VERSION 5.7 ;
  NOWIREEXTENSIONATPIN ON ;
  DIVIDERCHAR "/" ;
  BUSBITCHARS "[]" ;
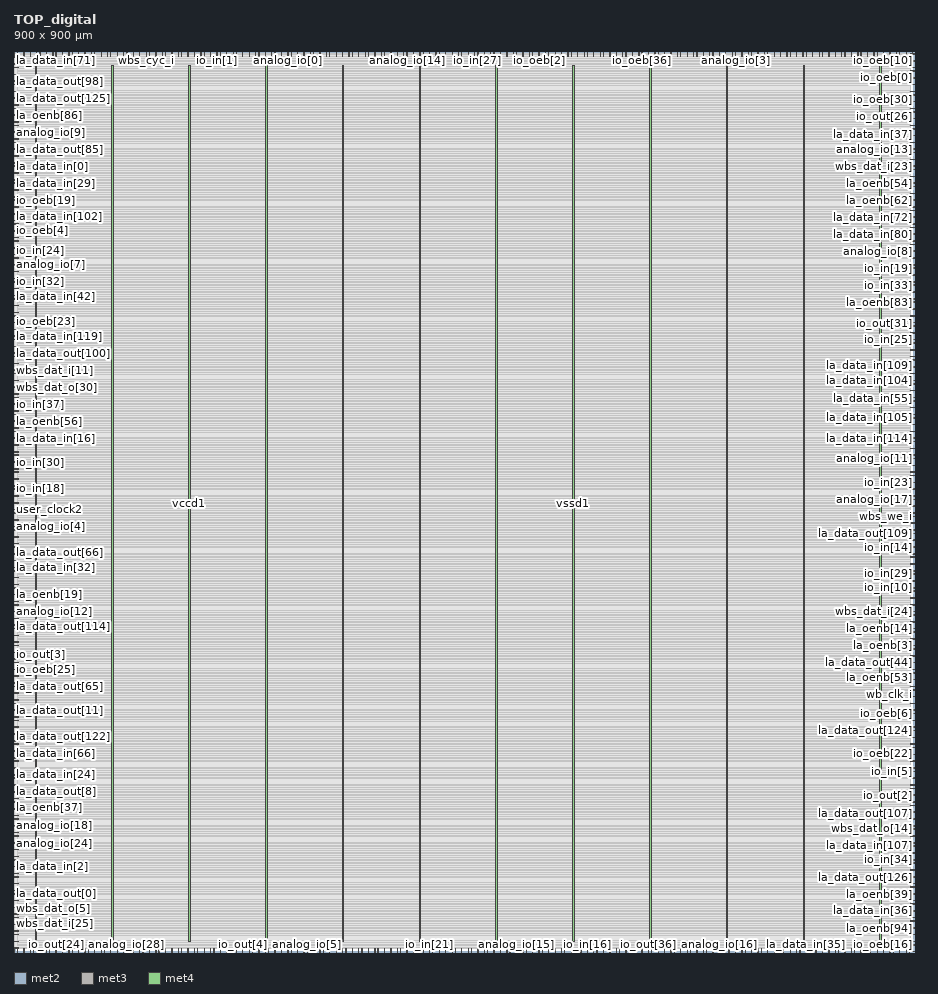
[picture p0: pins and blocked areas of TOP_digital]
MACRO TOP_digital
  CLASS BLOCK ;
  FOREIGN TOP_digital ;
  ORIGIN 0.000 0.000 ;
  SIZE 900.000 BY 900.000 ;
  PIN analog_io[0]
    DIRECTION INOUT ;
    USE SIGNAL ;
    PORT
      LAYER met2 ;
        RECT 273.790 896.000 274.070 900.000 ;
    END
  END analog_io[0]
  PIN analog_io[10]
    DIRECTION INOUT ;
    USE SIGNAL ;
    PORT
      LAYER met2 ;
        RECT 77.370 896.000 77.650 900.000 ;
    END
  END analog_io[10]
  PIN analog_io[11]
    DIRECTION INOUT ;
    USE SIGNAL ;
    PORT
      LAYER met3 ;
        RECT 896.000 493.040 900.000 493.640 ;
    END
  END analog_io[11]
  PIN analog_io[12]
    DIRECTION INOUT ;
    USE SIGNAL ;
    PORT
      LAYER met3 ;
        RECT 0.000 340.040 4.000 340.640 ;
    END
  END analog_io[12]
  PIN analog_io[13]
    DIRECTION INOUT ;
    USE SIGNAL ;
    PORT
      LAYER met3 ;
        RECT 896.000 802.440 900.000 803.040 ;
    END
  END analog_io[13]
  PIN analog_io[14]
    DIRECTION INOUT ;
    USE SIGNAL ;
    PORT
      LAYER met2 ;
        RECT 392.930 896.000 393.210 900.000 ;
    END
  END analog_io[14]
  PIN analog_io[15]
    DIRECTION INOUT ;
    USE SIGNAL ;
    PORT
      LAYER met2 ;
        RECT 502.410 0.000 502.690 4.000 ;
    END
  END analog_io[15]
  PIN analog_io[16]
    DIRECTION INOUT ;
    USE SIGNAL ;
    PORT
      LAYER met2 ;
        RECT 705.270 0.000 705.550 4.000 ;
    END
  END analog_io[16]
  PIN analog_io[17]
    DIRECTION INOUT ;
    USE SIGNAL ;
    PORT
      LAYER met3 ;
        RECT 896.000 452.240 900.000 452.840 ;
    END
  END analog_io[17]
  PIN analog_io[18]
    DIRECTION INOUT ;
    USE SIGNAL ;
    PORT
      LAYER met3 ;
        RECT 0.000 125.840 4.000 126.440 ;
    END
  END analog_io[18]
  PIN analog_io[19]
    DIRECTION INOUT ;
    USE SIGNAL ;
    PORT
      LAYER met3 ;
        RECT 0.000 537.240 4.000 537.840 ;
    END
  END analog_io[19]
  PIN analog_io[1]
    DIRECTION INOUT ;
    USE SIGNAL ;
    PORT
      LAYER met2 ;
        RECT 25.850 0.000 26.130 4.000 ;
    END
  END analog_io[1]
  PIN analog_io[20]
    DIRECTION INOUT ;
    USE SIGNAL ;
    PORT
      LAYER met2 ;
        RECT 512.070 0.000 512.350 4.000 ;
    END
  END analog_io[20]
  PIN analog_io[21]
    DIRECTION INOUT ;
    USE SIGNAL ;
    PORT
      LAYER met3 ;
        RECT 0.000 887.440 4.000 888.040 ;
    END
  END analog_io[21]
  PIN analog_io[22]
    DIRECTION INOUT ;
    USE SIGNAL ;
    PORT
      LAYER met3 ;
        RECT 896.000 799.040 900.000 799.640 ;
    END
  END analog_io[22]
  PIN analog_io[23]
    DIRECTION INOUT ;
    USE SIGNAL ;
    PORT
      LAYER met2 ;
        RECT 219.050 0.000 219.330 4.000 ;
    END
  END analog_io[23]
  PIN analog_io[24]
    DIRECTION INOUT ;
    USE SIGNAL ;
    PORT
      LAYER met3 ;
        RECT 0.000 115.640 4.000 116.240 ;
    END
  END analog_io[24]
  PIN analog_io[25]
    DIRECTION INOUT ;
    USE SIGNAL ;
    PORT
      LAYER met3 ;
        RECT 896.000 652.840 900.000 653.440 ;
    END
  END analog_io[25]
  PIN analog_io[26]
    DIRECTION INOUT ;
    USE SIGNAL ;
    PORT
      LAYER met2 ;
        RECT 714.930 0.000 715.210 4.000 ;
    END
  END analog_io[26]
  PIN analog_io[27]
    DIRECTION INOUT ;
    USE SIGNAL ;
    PORT
      LAYER met2 ;
        RECT 322.090 896.000 322.370 900.000 ;
    END
  END analog_io[27]
  PIN analog_io[28]
    DIRECTION INOUT ;
    USE SIGNAL ;
    PORT
      LAYER met2 ;
        RECT 112.790 0.000 113.070 4.000 ;
    END
  END analog_io[28]
  PIN analog_io[2]
    DIRECTION INOUT ;
    USE SIGNAL ;
    PORT
      LAYER met2 ;
        RECT 260.910 896.000 261.190 900.000 ;
    END
  END analog_io[2]
  PIN analog_io[3]
    DIRECTION INOUT ;
    USE SIGNAL ;
    PORT
      LAYER met2 ;
        RECT 721.370 896.000 721.650 900.000 ;
    END
  END analog_io[3]
  PIN analog_io[4]
    DIRECTION INOUT ;
    USE SIGNAL ;
    PORT
      LAYER met3 ;
        RECT 0.000 425.040 4.000 425.640 ;
    END
  END analog_io[4]
  PIN analog_io[5]
    DIRECTION INOUT ;
    USE SIGNAL ;
    PORT
      LAYER met2 ;
        RECT 293.110 0.000 293.390 4.000 ;
    END
  END analog_io[5]
  PIN analog_io[6]
    DIRECTION INOUT ;
    USE SIGNAL ;
    PORT
      LAYER met2 ;
        RECT 296.330 896.000 296.610 900.000 ;
    END
  END analog_io[6]
  PIN analog_io[7]
    DIRECTION INOUT ;
    USE SIGNAL ;
    PORT
      LAYER met3 ;
        RECT 0.000 686.840 4.000 687.440 ;
    END
  END analog_io[7]
  PIN analog_io[8]
    DIRECTION INOUT ;
    USE SIGNAL ;
    PORT
      LAYER met3 ;
        RECT 896.000 700.440 900.000 701.040 ;
    END
  END analog_io[8]
  PIN analog_io[9]
    DIRECTION INOUT ;
    USE SIGNAL ;
    PORT
      LAYER met3 ;
        RECT 0.000 819.440 4.000 820.040 ;
    END
  END analog_io[9]
  PIN analog_trigger_in
    DIRECTION INOUT ;
    USE SIGNAL ;
    PORT
      LAYER met3 ;
        RECT 0.000 78.240 4.000 78.840 ;
    END
  END analog_trigger_in
  PIN analog_trigger_out
    DIRECTION INOUT ;
    USE SIGNAL ;
    PORT
      LAYER met3 ;
        RECT 0.000 95.240 4.000 95.840 ;
    END
  END analog_trigger_out
  PIN io_in[0]
    DIRECTION INPUT ;
    USE SIGNAL ;
    PORT
      LAYER met2 ;
        RECT 151.430 896.000 151.710 900.000 ;
    END
  END io_in[0]
  PIN io_in[10]
    DIRECTION INPUT ;
    USE SIGNAL ;
    PORT
      LAYER met3 ;
        RECT 896.000 363.840 900.000 364.440 ;
    END
  END io_in[10]
  PIN io_in[11]
    DIRECTION INPUT ;
    USE SIGNAL ;
    PORT
      LAYER met2 ;
        RECT 673.070 896.000 673.350 900.000 ;
    END
  END io_in[11]
  PIN io_in[12]
    DIRECTION INPUT ;
    USE SIGNAL ;
    PORT
      LAYER met2 ;
        RECT 376.830 0.000 377.110 4.000 ;
    END
  END io_in[12]
  PIN io_in[13]
    DIRECTION INPUT ;
    USE SIGNAL ;
    PORT
      LAYER met3 ;
        RECT 896.000 455.640 900.000 456.240 ;
    END
  END io_in[13]
  PIN io_in[14]
    DIRECTION INPUT ;
    USE SIGNAL ;
    PORT
      LAYER met3 ;
        RECT 896.000 411.440 900.000 412.040 ;
    END
  END io_in[14]
  PIN io_in[15]
    DIRECTION INPUT ;
    USE SIGNAL ;
    PORT
      LAYER met3 ;
        RECT 896.000 10.240 900.000 10.840 ;
    END
  END io_in[15]
  PIN io_in[16]
    DIRECTION INPUT ;
    USE SIGNAL ;
    PORT
      LAYER met2 ;
        RECT 573.250 0.000 573.530 4.000 ;
    END
  END io_in[16]
  PIN io_in[17]
    DIRECTION INPUT ;
    USE SIGNAL ;
    PORT
      LAYER met2 ;
        RECT 109.570 896.000 109.850 900.000 ;
    END
  END io_in[17]
  PIN io_in[18]
    DIRECTION INPUT ;
    USE SIGNAL ;
    PORT
      LAYER met3 ;
        RECT 0.000 455.640 4.000 456.240 ;
    END
  END io_in[18]
  PIN io_in[19]
    DIRECTION INPUT ;
    USE SIGNAL ;
    PORT
      LAYER met3 ;
        RECT 896.000 683.440 900.000 684.040 ;
    END
  END io_in[19]
  PIN io_in[1]
    DIRECTION INPUT ;
    USE SIGNAL ;
    PORT
      LAYER met2 ;
        RECT 202.950 896.000 203.230 900.000 ;
    END
  END io_in[1]
  PIN io_in[20]
    DIRECTION INPUT ;
    USE SIGNAL ;
    PORT
      LAYER met3 ;
        RECT 896.000 421.640 900.000 422.240 ;
    END
  END io_in[20]
  PIN io_in[21]
    DIRECTION INPUT ;
    USE SIGNAL ;
    PORT
      LAYER met2 ;
        RECT 415.470 0.000 415.750 4.000 ;
    END
  END io_in[21]
  PIN io_in[22]
    DIRECTION INPUT ;
    USE SIGNAL ;
    PORT
      LAYER met2 ;
        RECT 48.390 896.000 48.670 900.000 ;
    END
  END io_in[22]
  PIN io_in[23]
    DIRECTION INPUT ;
    USE SIGNAL ;
    PORT
      LAYER met3 ;
        RECT 896.000 469.240 900.000 469.840 ;
    END
  END io_in[23]
  PIN io_in[24]
    DIRECTION INPUT ;
    USE SIGNAL ;
    PORT
      LAYER met3 ;
        RECT 0.000 693.640 4.000 694.240 ;
    END
  END io_in[24]
  PIN io_in[25]
    DIRECTION INPUT ;
    USE SIGNAL ;
    PORT
      LAYER met3 ;
        RECT 896.000 612.040 900.000 612.640 ;
    END
  END io_in[25]
  PIN io_in[26]
    DIRECTION INPUT ;
    USE SIGNAL ;
    PORT
      LAYER met3 ;
        RECT 896.000 445.440 900.000 446.040 ;
    END
  END io_in[26]
  PIN io_in[27]
    DIRECTION INPUT ;
    USE SIGNAL ;
    PORT
      LAYER met2 ;
        RECT 463.770 896.000 464.050 900.000 ;
    END
  END io_in[27]
  PIN io_in[28]
    DIRECTION INPUT ;
    USE SIGNAL ;
    PORT
      LAYER met2 ;
        RECT 135.330 896.000 135.610 900.000 ;
    END
  END io_in[28]
  PIN io_in[29]
    DIRECTION INPUT ;
    USE SIGNAL ;
    PORT
      LAYER met3 ;
        RECT 896.000 370.640 900.000 371.240 ;
    END
  END io_in[29]
  PIN io_in[2]
    DIRECTION INPUT ;
    USE SIGNAL ;
    PORT
      LAYER met2 ;
        RECT 80.590 896.000 80.870 900.000 ;
    END
  END io_in[2]
  PIN io_in[30]
    DIRECTION INPUT ;
    USE SIGNAL ;
    PORT
      LAYER met3 ;
        RECT 0.000 489.640 4.000 490.240 ;
    END
  END io_in[30]
  PIN io_in[31]
    DIRECTION INPUT ;
    USE SIGNAL ;
    PORT
      LAYER met2 ;
        RECT 376.830 896.000 377.110 900.000 ;
    END
  END io_in[31]
  PIN io_in[32]
    DIRECTION INPUT ;
    USE SIGNAL ;
    PORT
      LAYER met3 ;
        RECT 0.000 669.840 4.000 670.440 ;
    END
  END io_in[32]
  PIN io_in[33]
    DIRECTION INPUT ;
    USE SIGNAL ;
    PORT
      LAYER met3 ;
        RECT 896.000 666.440 900.000 667.040 ;
    END
  END io_in[33]
  PIN io_in[34]
    DIRECTION INPUT ;
    USE SIGNAL ;
    PORT
      LAYER met3 ;
        RECT 896.000 91.840 900.000 92.440 ;
    END
  END io_in[34]
  PIN io_in[35]
    DIRECTION INPUT ;
    USE SIGNAL ;
    PORT
      LAYER met2 ;
        RECT 80.590 0.000 80.870 4.000 ;
    END
  END io_in[35]
  PIN io_in[36]
    DIRECTION INPUT ;
    USE SIGNAL ;
    PORT
      LAYER met3 ;
        RECT 0.000 309.440 4.000 310.040 ;
    END
  END io_in[36]
  PIN io_in[37]
    DIRECTION INPUT ;
    USE SIGNAL ;
    PORT
      LAYER met3 ;
        RECT 0.000 547.440 4.000 548.040 ;
    END
  END io_in[37]
  PIN io_in[3]
    DIRECTION INPUT ;
    USE SIGNAL ;
    PORT
      LAYER met2 ;
        RECT 566.810 0.000 567.090 4.000 ;
    END
  END io_in[3]
  PIN io_in[4]
    DIRECTION INPUT ;
    USE SIGNAL ;
    PORT
      LAYER met3 ;
        RECT 0.000 275.440 4.000 276.040 ;
    END
  END io_in[4]
  PIN io_in[5]
    DIRECTION INPUT ;
    USE SIGNAL ;
    PORT
      LAYER met3 ;
        RECT 896.000 180.240 900.000 180.840 ;
    END
  END io_in[5]
  PIN io_in[6]
    DIRECTION INPUT ;
    USE SIGNAL ;
    PORT
      LAYER met2 ;
        RECT 347.850 0.000 348.130 4.000 ;
    END
  END io_in[6]
  PIN io_in[7]
    DIRECTION INPUT ;
    USE SIGNAL ;
    PORT
      LAYER met3 ;
        RECT 0.000 166.640 4.000 167.240 ;
    END
  END io_in[7]
  PIN io_in[8]
    DIRECTION INPUT ;
    USE SIGNAL ;
    PORT
      LAYER met3 ;
        RECT 896.000 394.440 900.000 395.040 ;
    END
  END io_in[8]
  PIN io_in[9]
    DIRECTION INPUT ;
    USE SIGNAL ;
    PORT
      LAYER met3 ;
        RECT 896.000 122.440 900.000 123.040 ;
    END
  END io_in[9]
  PIN io_oeb[0]
    DIRECTION OUTPUT TRISTATE ;
    USE SIGNAL ;
    ANTENNADIFFAREA 0.445500 ;
    PORT
      LAYER met3 ;
        RECT 896.000 873.840 900.000 874.440 ;
    END
  END io_oeb[0]
  PIN io_oeb[10]
    DIRECTION OUTPUT TRISTATE ;
    USE SIGNAL ;
    ANTENNADIFFAREA 0.445500 ;
    PORT
      LAYER met2 ;
        RECT 882.370 896.000 882.650 900.000 ;
    END
  END io_oeb[10]
  PIN io_oeb[11]
    DIRECTION OUTPUT TRISTATE ;
    USE SIGNAL ;
    ANTENNADIFFAREA 0.445500 ;
    PORT
      LAYER met3 ;
        RECT 0.000 595.040 4.000 595.640 ;
    END
  END io_oeb[11]
  PIN io_oeb[12]
    DIRECTION OUTPUT TRISTATE ;
    USE SIGNAL ;
    ANTENNADIFFAREA 0.445500 ;
    PORT
      LAYER met3 ;
        RECT 896.000 897.640 900.000 898.240 ;
    END
  END io_oeb[12]
  PIN io_oeb[13]
    DIRECTION OUTPUT TRISTATE ;
    USE SIGNAL ;
    ANTENNADIFFAREA 0.445500 ;
    PORT
      LAYER met2 ;
        RECT 344.630 896.000 344.910 900.000 ;
    END
  END io_oeb[13]
  PIN io_oeb[14]
    DIRECTION OUTPUT TRISTATE ;
    USE SIGNAL ;
    ANTENNADIFFAREA 0.445500 ;
    PORT
      LAYER met2 ;
        RECT 595.790 0.000 596.070 4.000 ;
    END
  END io_oeb[14]
  PIN io_oeb[15]
    DIRECTION OUTPUT TRISTATE ;
    USE SIGNAL ;
    ANTENNADIFFAREA 0.445500 ;
    PORT
      LAYER met2 ;
        RECT 251.250 896.000 251.530 900.000 ;
    END
  END io_oeb[15]
  PIN io_oeb[16]
    DIRECTION OUTPUT TRISTATE ;
    USE SIGNAL ;
    ANTENNADIFFAREA 0.445500 ;
    PORT
      LAYER met2 ;
        RECT 885.590 0.000 885.870 4.000 ;
    END
  END io_oeb[16]
  PIN io_oeb[17]
    DIRECTION OUTPUT TRISTATE ;
    USE SIGNAL ;
    ANTENNADIFFAREA 0.445500 ;
    PORT
      LAYER met3 ;
        RECT 896.000 758.240 900.000 758.840 ;
    END
  END io_oeb[17]
  PIN io_oeb[18]
    DIRECTION OUTPUT TRISTATE ;
    USE SIGNAL ;
    ANTENNADIFFAREA 0.445500 ;
    PORT
      LAYER met2 ;
        RECT 846.950 0.000 847.230 4.000 ;
    END
  END io_oeb[18]
  PIN io_oeb[19]
    DIRECTION OUTPUT TRISTATE ;
    USE SIGNAL ;
    ANTENNADIFFAREA 0.445500 ;
    PORT
      LAYER met3 ;
        RECT 0.000 751.440 4.000 752.040 ;
    END
  END io_oeb[19]
  PIN io_oeb[1]
    DIRECTION OUTPUT TRISTATE ;
    USE SIGNAL ;
    ANTENNADIFFAREA 0.445500 ;
    PORT
      LAYER met2 ;
        RECT 460.550 896.000 460.830 900.000 ;
    END
  END io_oeb[1]
  PIN io_oeb[20]
    DIRECTION OUTPUT TRISTATE ;
    USE SIGNAL ;
    ANTENNADIFFAREA 0.445500 ;
    PORT
      LAYER met3 ;
        RECT 896.000 132.640 900.000 133.240 ;
    END
  END io_oeb[20]
  PIN io_oeb[21]
    DIRECTION OUTPUT TRISTATE ;
    USE SIGNAL ;
    ANTENNADIFFAREA 0.445500 ;
    PORT
      LAYER met3 ;
        RECT 896.000 744.640 900.000 745.240 ;
    END
  END io_oeb[21]
  PIN io_oeb[22]
    DIRECTION OUTPUT TRISTATE ;
    USE SIGNAL ;
    ANTENNADIFFAREA 0.445500 ;
    PORT
      LAYER met3 ;
        RECT 896.000 190.440 900.000 191.040 ;
    END
  END io_oeb[22]
  PIN io_oeb[23]
    DIRECTION OUTPUT TRISTATE ;
    USE SIGNAL ;
    ANTENNADIFFAREA 0.445500 ;
    PORT
      LAYER met3 ;
        RECT 0.000 622.240 4.000 622.840 ;
    END
  END io_oeb[23]
  PIN io_oeb[24]
    DIRECTION OUTPUT TRISTATE ;
    USE SIGNAL ;
    ANTENNADIFFAREA 0.445500 ;
    PORT
      LAYER met3 ;
        RECT 0.000 34.040 4.000 34.640 ;
    END
  END io_oeb[24]
  PIN io_oeb[25]
    DIRECTION OUTPUT TRISTATE ;
    USE SIGNAL ;
    ANTENNADIFFAREA 0.445500 ;
    PORT
      LAYER met3 ;
        RECT 0.000 282.240 4.000 282.840 ;
    END
  END io_oeb[25]
  PIN io_oeb[26]
    DIRECTION OUTPUT TRISTATE ;
    USE SIGNAL ;
    ANTENNADIFFAREA 0.445500 ;
    PORT
      LAYER met2 ;
        RECT 772.890 896.000 773.170 900.000 ;
    END
  END io_oeb[26]
  PIN io_oeb[27]
    DIRECTION OUTPUT TRISTATE ;
    USE SIGNAL ;
    ANTENNADIFFAREA 0.445500 ;
    PORT
      LAYER met2 ;
        RECT 676.290 0.000 676.570 4.000 ;
    END
  END io_oeb[27]
  PIN io_oeb[28]
    DIRECTION OUTPUT TRISTATE ;
    USE SIGNAL ;
    ANTENNADIFFAREA 0.445500 ;
    PORT
      LAYER met2 ;
        RECT 305.990 0.000 306.270 4.000 ;
    END
  END io_oeb[28]
  PIN io_oeb[29]
    DIRECTION OUTPUT TRISTATE ;
    USE SIGNAL ;
    ANTENNADIFFAREA 0.445500 ;
    PORT
      LAYER met3 ;
        RECT 0.000 183.640 4.000 184.240 ;
    END
  END io_oeb[29]
  PIN io_oeb[2]
    DIRECTION OUTPUT TRISTATE ;
    USE SIGNAL ;
    ANTENNADIFFAREA 0.445500 ;
    PORT
      LAYER met2 ;
        RECT 524.950 896.000 525.230 900.000 ;
    END
  END io_oeb[2]
  PIN io_oeb[30]
    DIRECTION OUTPUT TRISTATE ;
    USE SIGNAL ;
    ANTENNADIFFAREA 0.445500 ;
    PORT
      LAYER met3 ;
        RECT 896.000 860.240 900.000 860.840 ;
    END
  END io_oeb[30]
  PIN io_oeb[31]
    DIRECTION OUTPUT TRISTATE ;
    USE SIGNAL ;
    ANTENNADIFFAREA 0.445500 ;
    PORT
      LAYER met2 ;
        RECT 827.630 896.000 827.910 900.000 ;
    END
  END io_oeb[31]
  PIN io_oeb[32]
    DIRECTION OUTPUT TRISTATE ;
    USE SIGNAL ;
    ANTENNADIFFAREA 0.445500 ;
    PORT
      LAYER met3 ;
        RECT 0.000 326.440 4.000 327.040 ;
    END
  END io_oeb[32]
  PIN io_oeb[33]
    DIRECTION OUTPUT TRISTATE ;
    USE SIGNAL ;
    ANTENNADIFFAREA 0.445500 ;
    PORT
      LAYER met3 ;
        RECT 0.000 754.840 4.000 755.440 ;
    END
  END io_oeb[33]
  PIN io_oeb[34]
    DIRECTION OUTPUT TRISTATE ;
    USE SIGNAL ;
    ANTENNADIFFAREA 0.445500 ;
    PORT
      LAYER met2 ;
        RECT 438.010 896.000 438.290 900.000 ;
    END
  END io_oeb[34]
  PIN io_oeb[35]
    DIRECTION OUTPUT TRISTATE ;
    USE SIGNAL ;
    ANTENNADIFFAREA 0.445500 ;
    PORT
      LAYER met3 ;
        RECT 0.000 829.640 4.000 830.240 ;
    END
  END io_oeb[35]
  PIN io_oeb[36]
    DIRECTION OUTPUT TRISTATE ;
    USE SIGNAL ;
    ANTENNADIFFAREA 0.445500 ;
    PORT
      LAYER met2 ;
        RECT 627.990 896.000 628.270 900.000 ;
    END
  END io_oeb[36]
  PIN io_oeb[37]
    DIRECTION OUTPUT TRISTATE ;
    USE SIGNAL ;
    ANTENNADIFFAREA 0.445500 ;
    PORT
      LAYER met2 ;
        RECT 3.310 896.000 3.590 900.000 ;
    END
  END io_oeb[37]
  PIN io_oeb[3]
    DIRECTION OUTPUT TRISTATE ;
    USE SIGNAL ;
    ANTENNADIFFAREA 0.445500 ;
    PORT
      LAYER met3 ;
        RECT 0.000 523.640 4.000 524.240 ;
    END
  END io_oeb[3]
  PIN io_oeb[4]
    DIRECTION OUTPUT TRISTATE ;
    USE SIGNAL ;
    ANTENNADIFFAREA 0.445500 ;
    PORT
      LAYER met3 ;
        RECT 0.000 720.840 4.000 721.440 ;
    END
  END io_oeb[4]
  PIN io_oeb[5]
    DIRECTION OUTPUT TRISTATE ;
    USE SIGNAL ;
    ANTENNADIFFAREA 0.445500 ;
    PORT
      LAYER met2 ;
        RECT 58.050 896.000 58.330 900.000 ;
    END
  END io_oeb[5]
  PIN io_oeb[6]
    DIRECTION OUTPUT TRISTATE ;
    USE SIGNAL ;
    ANTENNADIFFAREA 0.445500 ;
    PORT
      LAYER met3 ;
        RECT 896.000 238.040 900.000 238.640 ;
    END
  END io_oeb[6]
  PIN io_oeb[7]
    DIRECTION OUTPUT TRISTATE ;
    USE SIGNAL ;
    ANTENNADIFFAREA 0.445500 ;
    PORT
      LAYER met3 ;
        RECT 896.000 241.440 900.000 242.040 ;
    END
  END io_oeb[7]
  PIN io_oeb[8]
    DIRECTION OUTPUT TRISTATE ;
    USE SIGNAL ;
    ANTENNADIFFAREA 0.445500 ;
    PORT
      LAYER met2 ;
        RECT 895.250 0.000 895.530 4.000 ;
    END
  END io_oeb[8]
  PIN io_oeb[9]
    DIRECTION OUTPUT TRISTATE ;
    USE SIGNAL ;
    ANTENNADIFFAREA 0.445500 ;
    PORT
      LAYER met2 ;
        RECT 415.470 896.000 415.750 900.000 ;
    END
  END io_oeb[9]
  PIN io_out[0]
    DIRECTION OUTPUT TRISTATE ;
    USE SIGNAL ;
    ANTENNADIFFAREA 0.445500 ;
    PORT
      LAYER met2 ;
        RECT 74.150 0.000 74.430 4.000 ;
    END
  END io_out[0]
  PIN io_out[10]
    DIRECTION OUTPUT TRISTATE ;
    USE SIGNAL ;
    ANTENNADIFFAREA 0.445500 ;
    PORT
      LAYER met3 ;
        RECT 0.000 37.440 4.000 38.040 ;
    END
  END io_out[10]
  PIN io_out[11]
    DIRECTION OUTPUT TRISTATE ;
    USE SIGNAL ;
    ANTENNADIFFAREA 0.445500 ;
    PORT
      LAYER met2 ;
        RECT 180.410 896.000 180.690 900.000 ;
    END
  END io_out[11]
  PIN io_out[12]
    DIRECTION OUTPUT TRISTATE ;
    USE SIGNAL ;
    ANTENNADIFFAREA 0.445500 ;
    PORT
      LAYER met2 ;
        RECT 447.670 0.000 447.950 4.000 ;
    END
  END io_out[12]
  PIN io_out[13]
    DIRECTION OUTPUT TRISTATE ;
    USE SIGNAL ;
    ANTENNADIFFAREA 0.445500 ;
    PORT
      LAYER met3 ;
        RECT 0.000 448.840 4.000 449.440 ;
    END
  END io_out[13]
  PIN io_out[14]
    DIRECTION OUTPUT TRISTATE ;
    USE SIGNAL ;
    ANTENNADIFFAREA 0.445500 ;
    PORT
      LAYER met2 ;
        RECT 164.310 896.000 164.590 900.000 ;
    END
  END io_out[14]
  PIN io_out[15]
    DIRECTION OUTPUT TRISTATE ;
    USE SIGNAL ;
    ANTENNADIFFAREA 0.445500 ;
    PORT
      LAYER met3 ;
        RECT 0.000 697.040 4.000 697.640 ;
    END
  END io_out[15]
  PIN io_out[16]
    DIRECTION OUTPUT TRISTATE ;
    USE SIGNAL ;
    ANTENNADIFFAREA 0.445500 ;
    PORT
      LAYER met2 ;
        RECT 322.090 0.000 322.370 4.000 ;
    END
  END io_out[16]
  PIN io_out[17]
    DIRECTION OUTPUT TRISTATE ;
    USE SIGNAL ;
    ANTENNADIFFAREA 0.445500 ;
    PORT
      LAYER met2 ;
        RECT 157.870 0.000 158.150 4.000 ;
    END
  END io_out[17]
  PIN io_out[18]
    DIRECTION OUTPUT TRISTATE ;
    USE SIGNAL ;
    ANTENNADIFFAREA 0.445500 ;
    PORT
      LAYER met3 ;
        RECT 0.000 578.040 4.000 578.640 ;
    END
  END io_out[18]
  PIN io_out[19]
    DIRECTION OUTPUT TRISTATE ;
    USE SIGNAL ;
    ANTENNADIFFAREA 0.445500 ;
    PORT
      LAYER met2 ;
        RECT 96.690 896.000 96.970 900.000 ;
    END
  END io_out[19]
  PIN io_out[1]
    DIRECTION OUTPUT TRISTATE ;
    USE SIGNAL ;
    ANTENNADIFFAREA 0.445500 ;
    PORT
      LAYER met2 ;
        RECT 682.730 0.000 683.010 4.000 ;
    END
  END io_out[1]
  PIN io_out[20]
    DIRECTION OUTPUT TRISTATE ;
    USE SIGNAL ;
    ANTENNADIFFAREA 0.445500 ;
    PORT
      LAYER met2 ;
        RECT 846.950 896.000 847.230 900.000 ;
    END
  END io_out[20]
  PIN io_out[21]
    DIRECTION OUTPUT TRISTATE ;
    USE SIGNAL ;
    ANTENNADIFFAREA 0.445500 ;
    PORT
      LAYER met2 ;
        RECT 402.590 0.000 402.870 4.000 ;
    END
  END io_out[21]
  PIN io_out[22]
    DIRECTION OUTPUT TRISTATE ;
    USE SIGNAL ;
    ANTENNADIFFAREA 0.445500 ;
    PORT
      LAYER met2 ;
        RECT 135.330 0.000 135.610 4.000 ;
    END
  END io_out[22]
  PIN io_out[23]
    DIRECTION OUTPUT TRISTATE ;
    USE SIGNAL ;
    ANTENNADIFFAREA 0.445500 ;
    PORT
      LAYER met2 ;
        RECT 776.110 896.000 776.390 900.000 ;
    END
  END io_out[23]
  PIN io_out[24]
    DIRECTION OUTPUT TRISTATE ;
    USE SIGNAL ;
    ANTENNADIFFAREA 0.445500 ;
    PORT
      LAYER met2 ;
        RECT 41.950 0.000 42.230 4.000 ;
    END
  END io_out[24]
  PIN io_out[25]
    DIRECTION OUTPUT TRISTATE ;
    USE SIGNAL ;
    ANTENNADIFFAREA 0.445500 ;
    PORT
      LAYER met3 ;
        RECT 896.000 166.640 900.000 167.240 ;
    END
  END io_out[25]
  PIN io_out[26]
    DIRECTION OUTPUT TRISTATE ;
    USE SIGNAL ;
    ANTENNADIFFAREA 0.445500 ;
    PORT
      LAYER met3 ;
        RECT 896.000 843.240 900.000 843.840 ;
    END
  END io_out[26]
  PIN io_out[27]
    DIRECTION OUTPUT TRISTATE ;
    USE SIGNAL ;
    ANTENNADIFFAREA 0.445500 ;
    PORT
      LAYER met2 ;
        RECT 492.750 896.000 493.030 900.000 ;
    END
  END io_out[27]
  PIN io_out[28]
    DIRECTION OUTPUT TRISTATE ;
    USE SIGNAL ;
    ANTENNADIFFAREA 0.445500 ;
    PORT
      LAYER met2 ;
        RECT 589.350 0.000 589.630 4.000 ;
    END
  END io_out[28]
  PIN io_out[29]
    DIRECTION OUTPUT TRISTATE ;
    USE SIGNAL ;
    ANTENNADIFFAREA 0.445500 ;
    PORT
      LAYER met2 ;
        RECT 875.930 896.000 876.210 900.000 ;
    END
  END io_out[29]
  PIN io_out[2]
    DIRECTION OUTPUT TRISTATE ;
    USE SIGNAL ;
    ANTENNADIFFAREA 0.445500 ;
    PORT
      LAYER met3 ;
        RECT 896.000 156.440 900.000 157.040 ;
    END
  END io_out[2]
  PIN io_out[30]
    DIRECTION OUTPUT TRISTATE ;
    USE SIGNAL ;
    ANTENNADIFFAREA 0.445500 ;
    PORT
      LAYER met2 ;
        RECT 392.930 0.000 393.210 4.000 ;
    END
  END io_out[30]
  PIN io_out[31]
    DIRECTION OUTPUT TRISTATE ;
    USE SIGNAL ;
    ANTENNADIFFAREA 0.445500 ;
    PORT
      LAYER met3 ;
        RECT 896.000 635.840 900.000 636.440 ;
    END
  END io_out[31]
  PIN io_out[32]
    DIRECTION OUTPUT TRISTATE ;
    USE SIGNAL ;
    ANTENNADIFFAREA 0.445500 ;
    PORT
      LAYER met2 ;
        RECT 119.230 0.000 119.510 4.000 ;
    END
  END io_out[32]
  PIN io_out[33]
    DIRECTION OUTPUT TRISTATE ;
    USE SIGNAL ;
    ANTENNADIFFAREA 0.445500 ;
    PORT
      LAYER met2 ;
        RECT 354.290 0.000 354.570 4.000 ;
    END
  END io_out[33]
  PIN io_out[34]
    DIRECTION OUTPUT TRISTATE ;
    USE SIGNAL ;
    ANTENNADIFFAREA 0.445500 ;
    PORT
      LAYER met2 ;
        RECT 863.050 0.000 863.330 4.000 ;
    END
  END io_out[34]
  PIN io_out[35]
    DIRECTION OUTPUT TRISTATE ;
    USE SIGNAL ;
    ANTENNADIFFAREA 0.445500 ;
    PORT
      LAYER met3 ;
        RECT 0.000 894.240 4.000 894.840 ;
    END
  END io_out[35]
  PIN io_out[36]
    DIRECTION OUTPUT TRISTATE ;
    USE SIGNAL ;
    ANTENNADIFFAREA 0.445500 ;
    PORT
      LAYER met2 ;
        RECT 634.430 0.000 634.710 4.000 ;
    END
  END io_out[36]
  PIN io_out[37]
    DIRECTION OUTPUT TRISTATE ;
    USE SIGNAL ;
    ANTENNADIFFAREA 0.445500 ;
    PORT
      LAYER met2 ;
        RECT 148.210 896.000 148.490 900.000 ;
    END
  END io_out[37]
  PIN io_out[3]
    DIRECTION OUTPUT TRISTATE ;
    USE SIGNAL ;
    ANTENNADIFFAREA 0.445500 ;
    PORT
      LAYER met3 ;
        RECT 0.000 289.040 4.000 289.640 ;
    END
  END io_out[3]
  PIN io_out[4]
    DIRECTION OUTPUT TRISTATE ;
    USE SIGNAL ;
    ANTENNADIFFAREA 0.445500 ;
    PORT
      LAYER met2 ;
        RECT 228.710 0.000 228.990 4.000 ;
    END
  END io_out[4]
  PIN io_out[5]
    DIRECTION OUTPUT TRISTATE ;
    USE SIGNAL ;
    ANTENNADIFFAREA 0.445500 ;
    PORT
      LAYER met2 ;
        RECT 222.270 0.000 222.550 4.000 ;
    END
  END io_out[5]
  PIN io_out[6]
    DIRECTION OUTPUT TRISTATE ;
    USE SIGNAL ;
    ANTENNADIFFAREA 0.445500 ;
    PORT
      LAYER met2 ;
        RECT 54.830 0.000 55.110 4.000 ;
    END
  END io_out[6]
  PIN io_out[7]
    DIRECTION OUTPUT TRISTATE ;
    USE SIGNAL ;
    ANTENNADIFFAREA 0.445500 ;
    PORT
      LAYER met3 ;
        RECT 0.000 588.240 4.000 588.840 ;
    END
  END io_out[7]
  PIN io_out[8]
    DIRECTION OUTPUT TRISTATE ;
    USE SIGNAL ;
    ANTENNADIFFAREA 0.445500 ;
    PORT
      LAYER met3 ;
        RECT 0.000 397.840 4.000 398.440 ;
    END
  END io_out[8]
  PIN io_out[9]
    DIRECTION OUTPUT TRISTATE ;
    USE SIGNAL ;
    ANTENNADIFFAREA 0.445500 ;
    PORT
      LAYER met2 ;
        RECT 760.010 0.000 760.290 4.000 ;
    END
  END io_out[9]
  PIN la_data_in[0]
    DIRECTION INPUT ;
    USE SIGNAL ;
    ANTENNAGATEAREA 0.742500 ;
    PORT
      LAYER met3 ;
        RECT 0.000 785.440 4.000 786.040 ;
    END
  END la_data_in[0]
  PIN la_data_in[100]
    DIRECTION INPUT ;
    USE SIGNAL ;
    PORT
      LAYER met2 ;
        RECT 766.450 896.000 766.730 900.000 ;
    END
  END la_data_in[100]
  PIN la_data_in[101]
    DIRECTION INPUT ;
    USE SIGNAL ;
    PORT
      LAYER met2 ;
        RECT 805.090 896.000 805.370 900.000 ;
    END
  END la_data_in[101]
  PIN la_data_in[102]
    DIRECTION INPUT ;
    USE SIGNAL ;
    PORT
      LAYER met3 ;
        RECT 0.000 727.640 4.000 728.240 ;
    END
  END la_data_in[102]
  PIN la_data_in[103]
    DIRECTION INPUT ;
    USE SIGNAL ;
    PORT
      LAYER met2 ;
        RECT 219.050 896.000 219.330 900.000 ;
    END
  END la_data_in[103]
  PIN la_data_in[104]
    DIRECTION INPUT ;
    USE SIGNAL ;
    PORT
      LAYER met3 ;
        RECT 896.000 571.240 900.000 571.840 ;
    END
  END la_data_in[104]
  PIN la_data_in[105]
    DIRECTION INPUT ;
    USE SIGNAL ;
    PORT
      LAYER met3 ;
        RECT 896.000 533.840 900.000 534.440 ;
    END
  END la_data_in[105]
  PIN la_data_in[106]
    DIRECTION INPUT ;
    USE SIGNAL ;
    PORT
      LAYER met2 ;
        RECT 808.310 896.000 808.590 900.000 ;
    END
  END la_data_in[106]
  PIN la_data_in[107]
    DIRECTION INPUT ;
    USE SIGNAL ;
    PORT
      LAYER met3 ;
        RECT 896.000 98.640 900.000 99.240 ;
    END
  END la_data_in[107]
  PIN la_data_in[108]
    DIRECTION INPUT ;
    USE SIGNAL ;
    PORT
      LAYER met3 ;
        RECT 896.000 816.040 900.000 816.640 ;
    END
  END la_data_in[108]
  PIN la_data_in[109]
    DIRECTION INPUT ;
    USE SIGNAL ;
    PORT
      LAYER met3 ;
        RECT 896.000 578.040 900.000 578.640 ;
    END
  END la_data_in[109]
  PIN la_data_in[10]
    DIRECTION INPUT ;
    USE SIGNAL ;
    PORT
      LAYER met3 ;
        RECT 896.000 479.440 900.000 480.040 ;
    END
  END la_data_in[10]
  PIN la_data_in[110]
    DIRECTION INPUT ;
    USE SIGNAL ;
    PORT
      LAYER met2 ;
        RECT 238.370 0.000 238.650 4.000 ;
    END
  END la_data_in[110]
  PIN la_data_in[111]
    DIRECTION INPUT ;
    USE SIGNAL ;
    PORT
      LAYER met2 ;
        RECT 875.930 0.000 876.210 4.000 ;
    END
  END la_data_in[111]
  PIN la_data_in[112]
    DIRECTION INPUT ;
    USE SIGNAL ;
    PORT
      LAYER met2 ;
        RECT 257.690 896.000 257.970 900.000 ;
    END
  END la_data_in[112]
  PIN la_data_in[113]
    DIRECTION INPUT ;
    USE SIGNAL ;
    PORT
      LAYER met3 ;
        RECT 896.000 782.040 900.000 782.640 ;
    END
  END la_data_in[113]
  PIN la_data_in[114]
    DIRECTION INPUT ;
    USE SIGNAL ;
    PORT
      LAYER met3 ;
        RECT 896.000 513.440 900.000 514.040 ;
    END
  END la_data_in[114]
  PIN la_data_in[115]
    DIRECTION INPUT ;
    USE SIGNAL ;
    PORT
      LAYER met2 ;
        RECT 360.730 896.000 361.010 900.000 ;
    END
  END la_data_in[115]
  PIN la_data_in[116]
    DIRECTION INPUT ;
    USE SIGNAL ;
    PORT
      LAYER met3 ;
        RECT 0.000 680.040 4.000 680.640 ;
    END
  END la_data_in[116]
  PIN la_data_in[117]
    DIRECTION INPUT ;
    USE SIGNAL ;
    PORT
      LAYER met3 ;
        RECT 896.000 595.040 900.000 595.640 ;
    END
  END la_data_in[117]
  PIN la_data_in[118]
    DIRECTION INPUT ;
    USE SIGNAL ;
    PORT
      LAYER met2 ;
        RECT 692.390 0.000 692.670 4.000 ;
    END
  END la_data_in[118]
  PIN la_data_in[119]
    DIRECTION INPUT ;
    USE SIGNAL ;
    PORT
      LAYER met3 ;
        RECT 0.000 615.440 4.000 616.040 ;
    END
  END la_data_in[119]
  PIN la_data_in[11]
    DIRECTION INPUT ;
    USE SIGNAL ;
    PORT
      LAYER met3 ;
        RECT 0.000 496.440 4.000 497.040 ;
    END
  END la_data_in[11]
  PIN la_data_in[120]
    DIRECTION INPUT ;
    USE SIGNAL ;
    PORT
      LAYER met2 ;
        RECT 711.710 896.000 711.990 900.000 ;
    END
  END la_data_in[120]
  PIN la_data_in[121]
    DIRECTION INPUT ;
    USE SIGNAL ;
    PORT
      LAYER met3 ;
        RECT 0.000 44.240 4.000 44.840 ;
    END
  END la_data_in[121]
  PIN la_data_in[122]
    DIRECTION INPUT ;
    USE SIGNAL ;
    PORT
      LAYER met3 ;
        RECT 896.000 163.240 900.000 163.840 ;
    END
  END la_data_in[122]
  PIN la_data_in[123]
    DIRECTION INPUT ;
    USE SIGNAL ;
    PORT
      LAYER met2 ;
        RECT 212.610 0.000 212.890 4.000 ;
    END
  END la_data_in[123]
  PIN la_data_in[124]
    DIRECTION INPUT ;
    USE SIGNAL ;
    PORT
      LAYER met2 ;
        RECT 180.410 0.000 180.690 4.000 ;
    END
  END la_data_in[124]
  PIN la_data_in[125]
    DIRECTION INPUT ;
    USE SIGNAL ;
    PORT
      LAYER met3 ;
        RECT 896.000 353.640 900.000 354.240 ;
    END
  END la_data_in[125]
  PIN la_data_in[126]
    DIRECTION INPUT ;
    USE SIGNAL ;
    PORT
      LAYER met2 ;
        RECT 328.530 896.000 328.810 900.000 ;
    END
  END la_data_in[126]
  PIN la_data_in[127]
    DIRECTION INPUT ;
    USE SIGNAL ;
    PORT
      LAYER met2 ;
        RECT 547.490 896.000 547.770 900.000 ;
    END
  END la_data_in[127]
  PIN la_data_in[12]
    DIRECTION INPUT ;
    USE SIGNAL ;
    PORT
      LAYER met3 ;
        RECT 896.000 741.240 900.000 741.840 ;
    END
  END la_data_in[12]
  PIN la_data_in[13]
    DIRECTION INPUT ;
    USE SIGNAL ;
    PORT
      LAYER met3 ;
        RECT 896.000 707.240 900.000 707.840 ;
    END
  END la_data_in[13]
  PIN la_data_in[14]
    DIRECTION INPUT ;
    USE SIGNAL ;
    PORT
      LAYER met2 ;
        RECT 289.890 896.000 290.170 900.000 ;
    END
  END la_data_in[14]
  PIN la_data_in[15]
    DIRECTION INPUT ;
    USE SIGNAL ;
    PORT
      LAYER met3 ;
        RECT 896.000 336.640 900.000 337.240 ;
    END
  END la_data_in[15]
  PIN la_data_in[16]
    DIRECTION INPUT ;
    USE SIGNAL ;
    PORT
      LAYER met3 ;
        RECT 0.000 513.440 4.000 514.040 ;
    END
  END la_data_in[16]
  PIN la_data_in[17]
    DIRECTION INPUT ;
    USE SIGNAL ;
    PORT
      LAYER met2 ;
        RECT 431.570 0.000 431.850 4.000 ;
    END
  END la_data_in[17]
  PIN la_data_in[18]
    DIRECTION INPUT ;
    USE SIGNAL ;
    PORT
      LAYER met2 ;
        RECT 186.850 896.000 187.130 900.000 ;
    END
  END la_data_in[18]
  PIN la_data_in[19]
    DIRECTION INPUT ;
    USE SIGNAL ;
    PORT
      LAYER met2 ;
        RECT 518.510 896.000 518.790 900.000 ;
    END
  END la_data_in[19]
  PIN la_data_in[1]
    DIRECTION INPUT ;
    USE SIGNAL ;
    PORT
      LAYER met3 ;
        RECT 896.000 0.040 900.000 0.640 ;
    END
  END la_data_in[1]
  PIN la_data_in[20]
    DIRECTION INPUT ;
    USE SIGNAL ;
    PORT
      LAYER met2 ;
        RECT 409.030 896.000 409.310 900.000 ;
    END
  END la_data_in[20]
  PIN la_data_in[21]
    DIRECTION INPUT ;
    USE SIGNAL ;
    PORT
      LAYER met2 ;
        RECT 399.370 0.000 399.650 4.000 ;
    END
  END la_data_in[21]
  PIN la_data_in[22]
    DIRECTION INPUT ;
    USE SIGNAL ;
    PORT
      LAYER met2 ;
        RECT 579.690 896.000 579.970 900.000 ;
    END
  END la_data_in[22]
  PIN la_data_in[23]
    DIRECTION INPUT ;
    USE SIGNAL ;
    PORT
      LAYER met2 ;
        RECT 843.730 896.000 844.010 900.000 ;
    END
  END la_data_in[23]
  PIN la_data_in[24]
    DIRECTION INPUT ;
    USE SIGNAL ;
    PORT
      LAYER met3 ;
        RECT 0.000 176.840 4.000 177.440 ;
    END
  END la_data_in[24]
  PIN la_data_in[25]
    DIRECTION INPUT ;
    USE SIGNAL ;
    PORT
      LAYER met2 ;
        RECT 792.210 896.000 792.490 900.000 ;
    END
  END la_data_in[25]
  PIN la_data_in[26]
    DIRECTION INPUT ;
    USE SIGNAL ;
    PORT
      LAYER met2 ;
        RECT 682.730 896.000 683.010 900.000 ;
    END
  END la_data_in[26]
  PIN la_data_in[27]
    DIRECTION INPUT ;
    USE SIGNAL ;
    PORT
      LAYER met2 ;
        RECT 277.010 0.000 277.290 4.000 ;
    END
  END la_data_in[27]
  PIN la_data_in[28]
    DIRECTION INPUT ;
    USE SIGNAL ;
    PORT
      LAYER met2 ;
        RECT 673.070 0.000 673.350 4.000 ;
    END
  END la_data_in[28]
  PIN la_data_in[29]
    DIRECTION INPUT ;
    USE SIGNAL ;
    PORT
      LAYER met3 ;
        RECT 0.000 768.440 4.000 769.040 ;
    END
  END la_data_in[29]
  PIN la_data_in[2]
    DIRECTION INPUT ;
    USE SIGNAL ;
    PORT
      LAYER met3 ;
        RECT 0.000 85.040 4.000 85.640 ;
    END
  END la_data_in[2]
  PIN la_data_in[30]
    DIRECTION INPUT ;
    USE SIGNAL ;
    PORT
      LAYER met2 ;
        RECT 196.510 896.000 196.790 900.000 ;
    END
  END la_data_in[30]
  PIN la_data_in[31]
    DIRECTION INPUT ;
    USE SIGNAL ;
    PORT
      LAYER met2 ;
        RECT 502.410 896.000 502.690 900.000 ;
    END
  END la_data_in[31]
  PIN la_data_in[32]
    DIRECTION INPUT ;
    USE SIGNAL ;
    PORT
      LAYER met3 ;
        RECT 0.000 384.240 4.000 384.840 ;
    END
  END la_data_in[32]
  PIN la_data_in[33]
    DIRECTION INPUT ;
    USE SIGNAL ;
    PORT
      LAYER met2 ;
        RECT 331.750 0.000 332.030 4.000 ;
    END
  END la_data_in[33]
  PIN la_data_in[34]
    DIRECTION INPUT ;
    USE SIGNAL ;
    PORT
      LAYER met3 ;
        RECT 0.000 299.240 4.000 299.840 ;
    END
  END la_data_in[34]
  PIN la_data_in[35]
    DIRECTION INPUT ;
    USE SIGNAL ;
    PORT
      LAYER met2 ;
        RECT 792.210 0.000 792.490 4.000 ;
    END
  END la_data_in[35]
  PIN la_data_in[36]
    DIRECTION INPUT ;
    USE SIGNAL ;
    PORT
      LAYER met3 ;
        RECT 896.000 40.840 900.000 41.440 ;
    END
  END la_data_in[36]
  PIN la_data_in[37]
    DIRECTION INPUT ;
    USE SIGNAL ;
    PORT
      LAYER met3 ;
        RECT 896.000 809.240 900.000 809.840 ;
    END
  END la_data_in[37]
  PIN la_data_in[38]
    DIRECTION INPUT ;
    USE SIGNAL ;
    PORT
      LAYER met2 ;
        RECT 727.810 0.000 728.090 4.000 ;
    END
  END la_data_in[38]
  PIN la_data_in[39]
    DIRECTION INPUT ;
    USE SIGNAL ;
    PORT
      LAYER met3 ;
        RECT 0.000 778.640 4.000 779.240 ;
    END
  END la_data_in[39]
  PIN la_data_in[3]
    DIRECTION INPUT ;
    USE SIGNAL ;
    PORT
      LAYER met3 ;
        RECT 0.000 3.440 4.000 4.040 ;
    END
  END la_data_in[3]
  PIN la_data_in[40]
    DIRECTION INPUT ;
    USE SIGNAL ;
    PORT
      LAYER met3 ;
        RECT 896.000 278.840 900.000 279.440 ;
    END
  END la_data_in[40]
  PIN la_data_in[41]
    DIRECTION INPUT ;
    USE SIGNAL ;
    PORT
      LAYER met3 ;
        RECT 896.000 591.640 900.000 592.240 ;
    END
  END la_data_in[41]
  PIN la_data_in[42]
    DIRECTION INPUT ;
    USE SIGNAL ;
    PORT
      LAYER met3 ;
        RECT 0.000 663.040 4.000 663.640 ;
    END
  END la_data_in[42]
  PIN la_data_in[43]
    DIRECTION INPUT ;
    USE SIGNAL ;
    PORT
      LAYER met3 ;
        RECT 896.000 724.240 900.000 724.840 ;
    END
  END la_data_in[43]
  PIN la_data_in[44]
    DIRECTION INPUT ;
    USE SIGNAL ;
    PORT
      LAYER met2 ;
        RECT 16.190 0.000 16.470 4.000 ;
    END
  END la_data_in[44]
  PIN la_data_in[45]
    DIRECTION INPUT ;
    USE SIGNAL ;
    PORT
      LAYER met2 ;
        RECT 125.670 896.000 125.950 900.000 ;
    END
  END la_data_in[45]
  PIN la_data_in[46]
    DIRECTION INPUT ;
    USE SIGNAL ;
    PORT
      LAYER met3 ;
        RECT 0.000 605.240 4.000 605.840 ;
    END
  END la_data_in[46]
  PIN la_data_in[47]
    DIRECTION INPUT ;
    USE SIGNAL ;
    PORT
      LAYER met2 ;
        RECT 814.750 896.000 815.030 900.000 ;
    END
  END la_data_in[47]
  PIN la_data_in[48]
    DIRECTION INPUT ;
    USE SIGNAL ;
    PORT
      LAYER met3 ;
        RECT 896.000 360.440 900.000 361.040 ;
    END
  END la_data_in[48]
  PIN la_data_in[49]
    DIRECTION INPUT ;
    USE SIGNAL ;
    PORT
      LAYER met2 ;
        RECT 898.470 896.000 898.750 900.000 ;
    END
  END la_data_in[49]
  PIN la_data_in[4]
    DIRECTION INPUT ;
    USE SIGNAL ;
    PORT
      LAYER met2 ;
        RECT 334.970 896.000 335.250 900.000 ;
    END
  END la_data_in[4]
  PIN la_data_in[50]
    DIRECTION INPUT ;
    USE SIGNAL ;
    PORT
      LAYER met2 ;
        RECT 824.410 0.000 824.690 4.000 ;
    END
  END la_data_in[50]
  PIN la_data_in[51]
    DIRECTION INPUT ;
    USE SIGNAL ;
    PORT
      LAYER met2 ;
        RECT 718.150 896.000 718.430 900.000 ;
    END
  END la_data_in[51]
  PIN la_data_in[52]
    DIRECTION INPUT ;
    USE SIGNAL ;
    PORT
      LAYER met2 ;
        RECT 354.290 896.000 354.570 900.000 ;
    END
  END la_data_in[52]
  PIN la_data_in[53]
    DIRECTION INPUT ;
    USE SIGNAL ;
    PORT
      LAYER met2 ;
        RECT 367.170 896.000 367.450 900.000 ;
    END
  END la_data_in[53]
  PIN la_data_in[54]
    DIRECTION INPUT ;
    USE SIGNAL ;
    PORT
      LAYER met2 ;
        RECT 190.070 0.000 190.350 4.000 ;
    END
  END la_data_in[54]
  PIN la_data_in[55]
    DIRECTION INPUT ;
    USE SIGNAL ;
    PORT
      LAYER met3 ;
        RECT 896.000 561.040 900.000 561.640 ;
    END
  END la_data_in[55]
  PIN la_data_in[56]
    DIRECTION INPUT ;
    USE SIGNAL ;
    PORT
      LAYER met2 ;
        RECT 3.310 0.000 3.590 4.000 ;
    END
  END la_data_in[56]
  PIN la_data_in[57]
    DIRECTION INPUT ;
    USE SIGNAL ;
    PORT
      LAYER met3 ;
        RECT 896.000 319.640 900.000 320.240 ;
    END
  END la_data_in[57]
  PIN la_data_in[58]
    DIRECTION INPUT ;
    USE SIGNAL ;
    PORT
      LAYER met3 ;
        RECT 896.000 890.840 900.000 891.440 ;
    END
  END la_data_in[58]
  PIN la_data_in[59]
    DIRECTION INPUT ;
    USE SIGNAL ;
    PORT
      LAYER met3 ;
        RECT 896.000 629.040 900.000 629.640 ;
    END
  END la_data_in[59]
  PIN la_data_in[5]
    DIRECTION INPUT ;
    USE SIGNAL ;
    PORT
      LAYER met2 ;
        RECT 666.630 896.000 666.910 900.000 ;
    END
  END la_data_in[5]
  PIN la_data_in[60]
    DIRECTION INPUT ;
    USE SIGNAL ;
    PORT
      LAYER met2 ;
        RECT 351.070 896.000 351.350 900.000 ;
    END
  END la_data_in[60]
  PIN la_data_in[61]
    DIRECTION INPUT ;
    USE SIGNAL ;
    PORT
      LAYER met2 ;
        RECT 553.930 896.000 554.210 900.000 ;
    END
  END la_data_in[61]
  PIN la_data_in[62]
    DIRECTION INPUT ;
    USE SIGNAL ;
    PORT
      LAYER met2 ;
        RECT 731.030 0.000 731.310 4.000 ;
    END
  END la_data_in[62]
  PIN la_data_in[63]
    DIRECTION INPUT ;
    USE SIGNAL ;
    PORT
      LAYER met2 ;
        RECT 479.870 896.000 480.150 900.000 ;
    END
  END la_data_in[63]
  PIN la_data_in[64]
    DIRECTION INPUT ;
    USE SIGNAL ;
    PORT
      LAYER met3 ;
        RECT 896.000 822.840 900.000 823.440 ;
    END
  END la_data_in[64]
  PIN la_data_in[65]
    DIRECTION INPUT ;
    USE SIGNAL ;
    PORT
      LAYER met3 ;
        RECT 0.000 27.240 4.000 27.840 ;
    END
  END la_data_in[65]
  PIN la_data_in[66]
    DIRECTION INPUT ;
    USE SIGNAL ;
    PORT
      LAYER met3 ;
        RECT 0.000 190.440 4.000 191.040 ;
    END
  END la_data_in[66]
  PIN la_data_in[67]
    DIRECTION INPUT ;
    USE SIGNAL ;
    PORT
      LAYER met3 ;
        RECT 896.000 676.640 900.000 677.240 ;
    END
  END la_data_in[67]
  PIN la_data_in[68]
    DIRECTION INPUT ;
    USE SIGNAL ;
    PORT
      LAYER met2 ;
        RECT 0.090 896.000 0.370 900.000 ;
    END
  END la_data_in[68]
  PIN la_data_in[69]
    DIRECTION INPUT ;
    USE SIGNAL ;
    PORT
      LAYER met2 ;
        RECT 109.570 0.000 109.850 4.000 ;
    END
  END la_data_in[69]
  PIN la_data_in[6]
    DIRECTION INPUT ;
    USE SIGNAL ;
    PORT
      LAYER met2 ;
        RECT 570.030 896.000 570.310 900.000 ;
    END
  END la_data_in[6]
  PIN la_data_in[70]
    DIRECTION INPUT ;
    USE SIGNAL ;
    PORT
      LAYER met2 ;
        RECT 840.510 0.000 840.790 4.000 ;
    END
  END la_data_in[70]
  PIN la_data_in[71]
    DIRECTION INPUT ;
    USE SIGNAL ;
    PORT
      LAYER met2 ;
        RECT 41.950 896.000 42.230 900.000 ;
    END
  END la_data_in[71]
  PIN la_data_in[72]
    DIRECTION INPUT ;
    USE SIGNAL ;
    PORT
      LAYER met3 ;
        RECT 896.000 734.440 900.000 735.040 ;
    END
  END la_data_in[72]
  PIN la_data_in[73]
    DIRECTION INPUT ;
    USE SIGNAL ;
    PORT
      LAYER met2 ;
        RECT 283.450 896.000 283.730 900.000 ;
    END
  END la_data_in[73]
  PIN la_data_in[74]
    DIRECTION INPUT ;
    USE SIGNAL ;
    PORT
      LAYER met2 ;
        RECT 454.110 896.000 454.390 900.000 ;
    END
  END la_data_in[74]
  PIN la_data_in[75]
    DIRECTION INPUT ;
    USE SIGNAL ;
    PORT
      LAYER met3 ;
        RECT 896.000 261.840 900.000 262.440 ;
    END
  END la_data_in[75]
  PIN la_data_in[76]
    DIRECTION INPUT ;
    USE SIGNAL ;
    PORT
      LAYER met2 ;
        RECT 837.290 896.000 837.570 900.000 ;
    END
  END la_data_in[76]
  PIN la_data_in[77]
    DIRECTION INPUT ;
    USE SIGNAL ;
    PORT
      LAYER met3 ;
        RECT 896.000 255.040 900.000 255.640 ;
    END
  END la_data_in[77]
  PIN la_data_in[78]
    DIRECTION INPUT ;
    USE SIGNAL ;
    PORT
      LAYER met3 ;
        RECT 896.000 88.440 900.000 89.040 ;
    END
  END la_data_in[78]
  PIN la_data_in[79]
    DIRECTION INPUT ;
    USE SIGNAL ;
    PORT
      LAYER met2 ;
        RECT 64.490 896.000 64.770 900.000 ;
    END
  END la_data_in[79]
  PIN la_data_in[7]
    DIRECTION INPUT ;
    USE SIGNAL ;
    PORT
      LAYER met2 ;
        RECT 473.430 0.000 473.710 4.000 ;
    END
  END la_data_in[7]
  PIN la_data_in[80]
    DIRECTION INPUT ;
    USE SIGNAL ;
    PORT
      LAYER met3 ;
        RECT 896.000 717.440 900.000 718.040 ;
    END
  END la_data_in[80]
  PIN la_data_in[81]
    DIRECTION INPUT ;
    USE SIGNAL ;
    PORT
      LAYER met2 ;
        RECT 463.770 0.000 464.050 4.000 ;
    END
  END la_data_in[81]
  PIN la_data_in[82]
    DIRECTION INPUT ;
    USE SIGNAL ;
    PORT
      LAYER met3 ;
        RECT 896.000 601.840 900.000 602.440 ;
    END
  END la_data_in[82]
  PIN la_data_in[83]
    DIRECTION INPUT ;
    USE SIGNAL ;
    PORT
      LAYER met2 ;
        RECT 879.150 0.000 879.430 4.000 ;
    END
  END la_data_in[83]
  PIN la_data_in[84]
    DIRECTION INPUT ;
    USE SIGNAL ;
    PORT
      LAYER met3 ;
        RECT 896.000 346.840 900.000 347.440 ;
    END
  END la_data_in[84]
  PIN la_data_in[85]
    DIRECTION INPUT ;
    USE SIGNAL ;
    PORT
      LAYER met2 ;
        RECT 315.650 896.000 315.930 900.000 ;
    END
  END la_data_in[85]
  PIN la_data_in[86]
    DIRECTION INPUT ;
    USE SIGNAL ;
    PORT
      LAYER met3 ;
        RECT 0.000 744.640 4.000 745.240 ;
    END
  END la_data_in[86]
  PIN la_data_in[87]
    DIRECTION INPUT ;
    USE SIGNAL ;
    PORT
      LAYER met3 ;
        RECT 0.000 540.640 4.000 541.240 ;
    END
  END la_data_in[87]
  PIN la_data_in[88]
    DIRECTION INPUT ;
    USE SIGNAL ;
    PORT
      LAYER met3 ;
        RECT 896.000 496.440 900.000 497.040 ;
    END
  END la_data_in[88]
  PIN la_data_in[89]
    DIRECTION INPUT ;
    USE SIGNAL ;
    PORT
      LAYER met2 ;
        RECT 128.890 0.000 129.170 4.000 ;
    END
  END la_data_in[89]
  PIN la_data_in[8]
    DIRECTION INPUT ;
    USE SIGNAL ;
    PORT
      LAYER met3 ;
        RECT 0.000 884.040 4.000 884.640 ;
    END
  END la_data_in[8]
  PIN la_data_in[90]
    DIRECTION INPUT ;
    USE SIGNAL ;
    PORT
      LAYER met3 ;
        RECT 0.000 462.440 4.000 463.040 ;
    END
  END la_data_in[90]
  PIN la_data_in[91]
    DIRECTION INPUT ;
    USE SIGNAL ;
    PORT
      LAYER met3 ;
        RECT 0.000 465.840 4.000 466.440 ;
    END
  END la_data_in[91]
  PIN la_data_in[92]
    DIRECTION INPUT ;
    USE SIGNAL ;
    PORT
      LAYER met3 ;
        RECT 0.000 10.240 4.000 10.840 ;
    END
  END la_data_in[92]
  PIN la_data_in[93]
    DIRECTION INPUT ;
    USE SIGNAL ;
    PORT
      LAYER met2 ;
        RECT 267.350 896.000 267.630 900.000 ;
    END
  END la_data_in[93]
  PIN la_data_in[94]
    DIRECTION INPUT ;
    USE SIGNAL ;
    PORT
      LAYER met3 ;
        RECT 896.000 693.640 900.000 694.240 ;
    END
  END la_data_in[94]
  PIN la_data_in[95]
    DIRECTION INPUT ;
    USE SIGNAL ;
    PORT
      LAYER met3 ;
        RECT 896.000 567.840 900.000 568.440 ;
    END
  END la_data_in[95]
  PIN la_data_in[96]
    DIRECTION INPUT ;
    USE SIGNAL ;
    PORT
      LAYER met3 ;
        RECT 0.000 414.840 4.000 415.440 ;
    END
  END la_data_in[96]
  PIN la_data_in[97]
    DIRECTION INPUT ;
    USE SIGNAL ;
    PORT
      LAYER met2 ;
        RECT 235.150 896.000 235.430 900.000 ;
    END
  END la_data_in[97]
  PIN la_data_in[98]
    DIRECTION INPUT ;
    USE SIGNAL ;
    PORT
      LAYER met2 ;
        RECT 389.710 896.000 389.990 900.000 ;
    END
  END la_data_in[98]
  PIN la_data_in[99]
    DIRECTION INPUT ;
    USE SIGNAL ;
    PORT
      LAYER met3 ;
        RECT 0.000 173.440 4.000 174.040 ;
    END
  END la_data_in[99]
  PIN la_data_in[9]
    DIRECTION INPUT ;
    USE SIGNAL ;
    PORT
      LAYER met2 ;
        RECT 383.270 0.000 383.550 4.000 ;
    END
  END la_data_in[9]
  PIN la_data_out[0]
    DIRECTION OUTPUT TRISTATE ;
    USE SIGNAL ;
    ANTENNADIFFAREA 0.445500 ;
    PORT
      LAYER met3 ;
        RECT 0.000 57.840 4.000 58.440 ;
    END
  END la_data_out[0]
  PIN la_data_out[100]
    DIRECTION OUTPUT TRISTATE ;
    USE SIGNAL ;
    ANTENNADIFFAREA 0.445500 ;
    PORT
      LAYER met3 ;
        RECT 0.000 598.440 4.000 599.040 ;
    END
  END la_data_out[100]
  PIN la_data_out[101]
    DIRECTION OUTPUT TRISTATE ;
    USE SIGNAL ;
    ANTENNADIFFAREA 0.445500 ;
    PORT
      LAYER met3 ;
        RECT 0.000 346.840 4.000 347.440 ;
    END
  END la_data_out[101]
  PIN la_data_out[102]
    DIRECTION OUTPUT TRISTATE ;
    USE SIGNAL ;
    ANTENNADIFFAREA 0.445500 ;
    PORT
      LAYER met3 ;
        RECT 896.000 856.840 900.000 857.440 ;
    END
  END la_data_out[102]
  PIN la_data_out[103]
    DIRECTION OUTPUT TRISTATE ;
    USE SIGNAL ;
    ANTENNADIFFAREA 0.445500 ;
    PORT
      LAYER met2 ;
        RECT 315.650 0.000 315.930 4.000 ;
    END
  END la_data_out[103]
  PIN la_data_out[104]
    DIRECTION OUTPUT TRISTATE ;
    USE SIGNAL ;
    ANTENNADIFFAREA 0.445500 ;
    PORT
      LAYER met2 ;
        RECT 167.530 0.000 167.810 4.000 ;
    END
  END la_data_out[104]
  PIN la_data_out[105]
    DIRECTION OUTPUT TRISTATE ;
    USE SIGNAL ;
    ANTENNADIFFAREA 0.445500 ;
    PORT
      LAYER met3 ;
        RECT 0.000 132.640 4.000 133.240 ;
    END
  END la_data_out[105]
  PIN la_data_out[106]
    DIRECTION OUTPUT TRISTATE ;
    USE SIGNAL ;
    ANTENNADIFFAREA 0.445500 ;
    PORT
      LAYER met2 ;
        RECT 93.470 896.000 93.750 900.000 ;
    END
  END la_data_out[106]
  PIN la_data_out[107]
    DIRECTION OUTPUT TRISTATE ;
    USE SIGNAL ;
    ANTENNADIFFAREA 0.445500 ;
    PORT
      LAYER met3 ;
        RECT 896.000 146.240 900.000 146.840 ;
    END
  END la_data_out[107]
  PIN la_data_out[108]
    DIRECTION OUTPUT TRISTATE ;
    USE SIGNAL ;
    ANTENNADIFFAREA 0.445500 ;
    PORT
      LAYER met2 ;
        RECT 206.170 0.000 206.450 4.000 ;
    END
  END la_data_out[108]
  PIN la_data_out[109]
    DIRECTION OUTPUT TRISTATE ;
    USE SIGNAL ;
    ANTENNADIFFAREA 0.445500 ;
    PORT
      LAYER met3 ;
        RECT 896.000 418.240 900.000 418.840 ;
    END
  END la_data_out[109]
  PIN la_data_out[10]
    DIRECTION OUTPUT TRISTATE ;
    USE SIGNAL ;
    ANTENNADIFFAREA 0.445500 ;
    PORT
      LAYER met3 ;
        RECT 896.000 584.840 900.000 585.440 ;
    END
  END la_data_out[10]
  PIN la_data_out[110]
    DIRECTION OUTPUT TRISTATE ;
    USE SIGNAL ;
    ANTENNADIFFAREA 0.445500 ;
    PORT
      LAYER met2 ;
        RECT 808.310 0.000 808.590 4.000 ;
    END
  END la_data_out[110]
  PIN la_data_out[111]
    DIRECTION OUTPUT TRISTATE ;
    USE SIGNAL ;
    ANTENNADIFFAREA 0.445500 ;
    PORT
      LAYER met2 ;
        RECT 602.230 0.000 602.510 4.000 ;
    END
  END la_data_out[111]
  PIN la_data_out[112]
    DIRECTION OUTPUT TRISTATE ;
    USE SIGNAL ;
    ANTENNADIFFAREA 0.445500 ;
    PORT
      LAYER met2 ;
        RECT 621.550 0.000 621.830 4.000 ;
    END
  END la_data_out[112]
  PIN la_data_out[113]
    DIRECTION OUTPUT TRISTATE ;
    USE SIGNAL ;
    ANTENNADIFFAREA 0.445500 ;
    PORT
      LAYER met3 ;
        RECT 896.000 197.240 900.000 197.840 ;
    END
  END la_data_out[113]
  PIN la_data_out[114]
    DIRECTION OUTPUT TRISTATE ;
    USE SIGNAL ;
    ANTENNADIFFAREA 0.445500 ;
    PORT
      LAYER met3 ;
        RECT 0.000 333.240 4.000 333.840 ;
    END
  END la_data_out[114]
  PIN la_data_out[115]
    DIRECTION OUTPUT TRISTATE ;
    USE SIGNAL ;
    ANTENNADIFFAREA 0.445500 ;
    PORT
      LAYER met2 ;
        RECT 273.790 0.000 274.070 4.000 ;
    END
  END la_data_out[115]
  PIN la_data_out[116]
    DIRECTION OUTPUT TRISTATE ;
    USE SIGNAL ;
    ANTENNADIFFAREA 0.445500 ;
    PORT
      LAYER met3 ;
        RECT 896.000 880.640 900.000 881.240 ;
    END
  END la_data_out[116]
  PIN la_data_out[117]
    DIRECTION OUTPUT TRISTATE ;
    USE SIGNAL ;
    ANTENNADIFFAREA 0.445500 ;
    PORT
      LAYER met3 ;
        RECT 896.000 139.440 900.000 140.040 ;
    END
  END la_data_out[117]
  PIN la_data_out[118]
    DIRECTION OUTPUT TRISTATE ;
    USE SIGNAL ;
    ANTENNADIFFAREA 0.445500 ;
    PORT
      LAYER met2 ;
        RECT 557.150 0.000 557.430 4.000 ;
    END
  END la_data_out[118]
  PIN la_data_out[119]
    DIRECTION OUTPUT TRISTATE ;
    USE SIGNAL ;
    ANTENNADIFFAREA 0.445500 ;
    PORT
      LAYER met3 ;
        RECT 896.000 775.240 900.000 775.840 ;
    END
  END la_data_out[119]
  PIN la_data_out[11]
    DIRECTION OUTPUT TRISTATE ;
    USE SIGNAL ;
    ANTENNADIFFAREA 0.445500 ;
    PORT
      LAYER met3 ;
        RECT 0.000 241.440 4.000 242.040 ;
    END
  END la_data_out[11]
  PIN la_data_out[120]
    DIRECTION OUTPUT TRISTATE ;
    USE SIGNAL ;
    ANTENNADIFFAREA 0.445500 ;
    PORT
      LAYER met2 ;
        RECT 830.850 0.000 831.130 4.000 ;
    END
  END la_data_out[120]
  PIN la_data_out[121]
    DIRECTION OUTPUT TRISTATE ;
    USE SIGNAL ;
    ANTENNADIFFAREA 0.445500 ;
    PORT
      LAYER met3 ;
        RECT 0.000 612.040 4.000 612.640 ;
    END
  END la_data_out[121]
  PIN la_data_out[122]
    DIRECTION OUTPUT TRISTATE ;
    USE SIGNAL ;
    ANTENNADIFFAREA 0.445500 ;
    PORT
      LAYER met3 ;
        RECT 0.000 207.440 4.000 208.040 ;
    END
  END la_data_out[122]
  PIN la_data_out[123]
    DIRECTION OUTPUT TRISTATE ;
    USE SIGNAL ;
    ANTENNADIFFAREA 0.445500 ;
    PORT
      LAYER met2 ;
        RECT 360.730 0.000 361.010 4.000 ;
    END
  END la_data_out[123]
  PIN la_data_out[124]
    DIRECTION OUTPUT TRISTATE ;
    USE SIGNAL ;
    ANTENNADIFFAREA 0.445500 ;
    PORT
      LAYER met3 ;
        RECT 896.000 221.040 900.000 221.640 ;
    END
  END la_data_out[124]
  PIN la_data_out[125]
    DIRECTION OUTPUT TRISTATE ;
    USE SIGNAL ;
    ANTENNADIFFAREA 0.445500 ;
    PORT
      LAYER met3 ;
        RECT 0.000 853.440 4.000 854.040 ;
    END
  END la_data_out[125]
  PIN la_data_out[126]
    DIRECTION OUTPUT TRISTATE ;
    USE SIGNAL ;
    ANTENNADIFFAREA 0.445500 ;
    PORT
      LAYER met3 ;
        RECT 896.000 81.640 900.000 82.240 ;
    END
  END la_data_out[126]
  PIN la_data_out[127]
    DIRECTION OUTPUT TRISTATE ;
    USE SIGNAL ;
    ANTENNADIFFAREA 0.445500 ;
    PORT
      LAYER met2 ;
        RECT 119.230 896.000 119.510 900.000 ;
    END
  END la_data_out[127]
  PIN la_data_out[12]
    DIRECTION OUTPUT TRISTATE ;
    USE SIGNAL ;
    ANTENNADIFFAREA 0.445500 ;
    PORT
      LAYER met2 ;
        RECT 737.470 896.000 737.750 900.000 ;
    END
  END la_data_out[12]
  PIN la_data_out[13]
    DIRECTION OUTPUT TRISTATE ;
    USE SIGNAL ;
    ANTENNADIFFAREA 0.445500 ;
    PORT
      LAYER met3 ;
        RECT 0.000 860.240 4.000 860.840 ;
    END
  END la_data_out[13]
  PIN la_data_out[14]
    DIRECTION OUTPUT TRISTATE ;
    USE SIGNAL ;
    ANTENNADIFFAREA 0.445500 ;
    PORT
      LAYER met2 ;
        RECT 309.210 0.000 309.490 4.000 ;
    END
  END la_data_out[14]
  PIN la_data_out[15]
    DIRECTION OUTPUT TRISTATE ;
    USE SIGNAL ;
    ANTENNADIFFAREA 0.445500 ;
    PORT
      LAYER met2 ;
        RECT 853.390 0.000 853.670 4.000 ;
    END
  END la_data_out[15]
  PIN la_data_out[16]
    DIRECTION OUTPUT TRISTATE ;
    USE SIGNAL ;
    ANTENNADIFFAREA 0.445500 ;
    PORT
      LAYER met3 ;
        RECT 0.000 826.240 4.000 826.840 ;
    END
  END la_data_out[16]
  PIN la_data_out[17]
    DIRECTION OUTPUT TRISTATE ;
    USE SIGNAL ;
    ANTENNADIFFAREA 0.445500 ;
    PORT
      LAYER met3 ;
        RECT 0.000 652.840 4.000 653.440 ;
    END
  END la_data_out[17]
  PIN la_data_out[18]
    DIRECTION OUTPUT TRISTATE ;
    USE SIGNAL ;
    ANTENNADIFFAREA 0.445500 ;
    PORT
      LAYER met2 ;
        RECT 25.850 896.000 26.130 900.000 ;
    END
  END la_data_out[18]
  PIN la_data_out[19]
    DIRECTION OUTPUT TRISTATE ;
    USE SIGNAL ;
    ANTENNADIFFAREA 0.445500 ;
    PORT
      LAYER met2 ;
        RECT 869.490 896.000 869.770 900.000 ;
    END
  END la_data_out[19]
  PIN la_data_out[1]
    DIRECTION OUTPUT TRISTATE ;
    USE SIGNAL ;
    ANTENNADIFFAREA 0.445500 ;
    PORT
      LAYER met2 ;
        RECT 151.430 0.000 151.710 4.000 ;
    END
  END la_data_out[1]
  PIN la_data_out[20]
    DIRECTION OUTPUT TRISTATE ;
    USE SIGNAL ;
    ANTENNADIFFAREA 0.445500 ;
    PORT
      LAYER met3 ;
        RECT 896.000 527.040 900.000 527.640 ;
    END
  END la_data_out[20]
  PIN la_data_out[21]
    DIRECTION OUTPUT TRISTATE ;
    USE SIGNAL ;
    ANTENNADIFFAREA 0.445500 ;
    PORT
      LAYER met3 ;
        RECT 896.000 17.040 900.000 17.640 ;
    END
  END la_data_out[21]
  PIN la_data_out[22]
    DIRECTION OUTPUT TRISTATE ;
    USE SIGNAL ;
    ANTENNADIFFAREA 0.445500 ;
    PORT
      LAYER met2 ;
        RECT 608.670 896.000 608.950 900.000 ;
    END
  END la_data_out[22]
  PIN la_data_out[23]
    DIRECTION OUTPUT TRISTATE ;
    USE SIGNAL ;
    ANTENNADIFFAREA 0.445500 ;
    PORT
      LAYER met3 ;
        RECT 896.000 204.040 900.000 204.640 ;
    END
  END la_data_out[23]
  PIN la_data_out[24]
    DIRECTION OUTPUT TRISTATE ;
    USE SIGNAL ;
    ANTENNADIFFAREA 0.445500 ;
    PORT
      LAYER met2 ;
        RECT 87.030 896.000 87.310 900.000 ;
    END
  END la_data_out[24]
  PIN la_data_out[25]
    DIRECTION OUTPUT TRISTATE ;
    USE SIGNAL ;
    ANTENNADIFFAREA 0.445500 ;
    PORT
      LAYER met3 ;
        RECT 896.000 207.440 900.000 208.040 ;
    END
  END la_data_out[25]
  PIN la_data_out[26]
    DIRECTION OUTPUT TRISTATE ;
    USE SIGNAL ;
    ANTENNADIFFAREA 0.445500 ;
    PORT
      LAYER met3 ;
        RECT 0.000 771.840 4.000 772.440 ;
    END
  END la_data_out[26]
  PIN la_data_out[27]
    DIRECTION OUTPUT TRISTATE ;
    USE SIGNAL ;
    ANTENNADIFFAREA 0.445500 ;
    PORT
      LAYER met3 ;
        RECT 0.000 472.640 4.000 473.240 ;
    END
  END la_data_out[27]
  PIN la_data_out[28]
    DIRECTION OUTPUT TRISTATE ;
    USE SIGNAL ;
    ANTENNADIFFAREA 0.445500 ;
    PORT
      LAYER met2 ;
        RECT 650.530 896.000 650.810 900.000 ;
    END
  END la_data_out[28]
  PIN la_data_out[29]
    DIRECTION OUTPUT TRISTATE ;
    USE SIGNAL ;
    ANTENNADIFFAREA 0.445500 ;
    PORT
      LAYER met3 ;
        RECT 896.000 404.640 900.000 405.240 ;
    END
  END la_data_out[29]
  PIN la_data_out[2]
    DIRECTION OUTPUT TRISTATE ;
    USE SIGNAL ;
    ANTENNADIFFAREA 0.445500 ;
    PORT
      LAYER met2 ;
        RECT 425.130 0.000 425.410 4.000 ;
    END
  END la_data_out[2]
  PIN la_data_out[30]
    DIRECTION OUTPUT TRISTATE ;
    USE SIGNAL ;
    ANTENNADIFFAREA 0.445500 ;
    PORT
      LAYER met2 ;
        RECT 418.690 0.000 418.970 4.000 ;
    END
  END la_data_out[30]
  PIN la_data_out[31]
    DIRECTION OUTPUT TRISTATE ;
    USE SIGNAL ;
    ANTENNADIFFAREA 0.445500 ;
    PORT
      LAYER met2 ;
        RECT 656.970 0.000 657.250 4.000 ;
    END
  END la_data_out[31]
  PIN la_data_out[32]
    DIRECTION OUTPUT TRISTATE ;
    USE SIGNAL ;
    ANTENNADIFFAREA 0.445500 ;
    PORT
      LAYER met2 ;
        RECT 476.650 896.000 476.930 900.000 ;
    END
  END la_data_out[32]
  PIN la_data_out[33]
    DIRECTION OUTPUT TRISTATE ;
    USE SIGNAL ;
    ANTENNADIFFAREA 0.445500 ;
    PORT
      LAYER met2 ;
        RECT 141.770 0.000 142.050 4.000 ;
    END
  END la_data_out[33]
  PIN la_data_out[34]
    DIRECTION OUTPUT TRISTATE ;
    USE SIGNAL ;
    ANTENNADIFFAREA 0.445500 ;
    PORT
      LAYER met2 ;
        RECT 277.010 896.000 277.290 900.000 ;
    END
  END la_data_out[34]
  PIN la_data_out[35]
    DIRECTION OUTPUT TRISTATE ;
    USE SIGNAL ;
    ANTENNADIFFAREA 0.445500 ;
    PORT
      LAYER met2 ;
        RECT 563.590 896.000 563.870 900.000 ;
    END
  END la_data_out[35]
  PIN la_data_out[36]
    DIRECTION OUTPUT TRISTATE ;
    USE SIGNAL ;
    ANTENNADIFFAREA 0.445500 ;
    PORT
      LAYER met2 ;
        RECT 634.430 896.000 634.710 900.000 ;
    END
  END la_data_out[36]
  PIN la_data_out[37]
    DIRECTION OUTPUT TRISTATE ;
    USE SIGNAL ;
    ANTENNADIFFAREA 0.445500 ;
    PORT
      LAYER met3 ;
        RECT 0.000 731.040 4.000 731.640 ;
    END
  END la_data_out[37]
  PIN la_data_out[38]
    DIRECTION OUTPUT TRISTATE ;
    USE SIGNAL ;
    ANTENNADIFFAREA 0.445500 ;
    PORT
      LAYER met2 ;
        RECT 32.290 896.000 32.570 900.000 ;
    END
  END la_data_out[38]
  PIN la_data_out[39]
    DIRECTION OUTPUT TRISTATE ;
    USE SIGNAL ;
    ANTENNADIFFAREA 0.445500 ;
    PORT
      LAYER met2 ;
        RECT 814.750 0.000 815.030 4.000 ;
    END
  END la_data_out[39]
  PIN la_data_out[3]
    DIRECTION OUTPUT TRISTATE ;
    USE SIGNAL ;
    ANTENNADIFFAREA 0.445500 ;
    PORT
      LAYER met2 ;
        RECT 892.030 0.000 892.310 4.000 ;
    END
  END la_data_out[3]
  PIN la_data_out[40]
    DIRECTION OUTPUT TRISTATE ;
    USE SIGNAL ;
    ANTENNADIFFAREA 0.445500 ;
    PORT
      LAYER met3 ;
        RECT 896.000 74.840 900.000 75.440 ;
    END
  END la_data_out[40]
  PIN la_data_out[41]
    DIRECTION OUTPUT TRISTATE ;
    USE SIGNAL ;
    ANTENNADIFFAREA 0.445500 ;
    PORT
      LAYER met2 ;
        RECT 338.190 896.000 338.470 900.000 ;
    END
  END la_data_out[41]
  PIN la_data_out[42]
    DIRECTION OUTPUT TRISTATE ;
    USE SIGNAL ;
    ANTENNADIFFAREA 0.445500 ;
    PORT
      LAYER met3 ;
        RECT 896.000 377.440 900.000 378.040 ;
    END
  END la_data_out[42]
  PIN la_data_out[43]
    DIRECTION OUTPUT TRISTATE ;
    USE SIGNAL ;
    ANTENNADIFFAREA 0.445500 ;
    PORT
      LAYER met2 ;
        RECT 441.230 0.000 441.510 4.000 ;
    END
  END la_data_out[43]
  PIN la_data_out[44]
    DIRECTION OUTPUT TRISTATE ;
    USE SIGNAL ;
    ANTENNADIFFAREA 0.445500 ;
    PORT
      LAYER met3 ;
        RECT 896.000 289.040 900.000 289.640 ;
    END
  END la_data_out[44]
  PIN la_data_out[45]
    DIRECTION OUTPUT TRISTATE ;
    USE SIGNAL ;
    ANTENNADIFFAREA 0.445500 ;
    PORT
      LAYER met3 ;
        RECT 896.000 833.040 900.000 833.640 ;
    END
  END la_data_out[45]
  PIN la_data_out[46]
    DIRECTION OUTPUT TRISTATE ;
    USE SIGNAL ;
    ANTENNADIFFAREA 0.445500 ;
    PORT
      LAYER met2 ;
        RECT 644.090 0.000 644.370 4.000 ;
    END
  END la_data_out[46]
  PIN la_data_out[47]
    DIRECTION OUTPUT TRISTATE ;
    USE SIGNAL ;
    ANTENNADIFFAREA 0.445500 ;
    PORT
      LAYER met2 ;
        RECT 518.510 0.000 518.790 4.000 ;
    END
  END la_data_out[47]
  PIN la_data_out[48]
    DIRECTION OUTPUT TRISTATE ;
    USE SIGNAL ;
    ANTENNADIFFAREA 0.445500 ;
    PORT
      LAYER met2 ;
        RECT 222.270 896.000 222.550 900.000 ;
    END
  END la_data_out[48]
  PIN la_data_out[49]
    DIRECTION OUTPUT TRISTATE ;
    USE SIGNAL ;
    ANTENNADIFFAREA 0.445500 ;
    PORT
      LAYER met2 ;
        RECT 90.250 0.000 90.530 4.000 ;
    END
  END la_data_out[49]
  PIN la_data_out[4]
    DIRECTION OUTPUT TRISTATE ;
    USE SIGNAL ;
    ANTENNADIFFAREA 0.445500 ;
    PORT
      LAYER met2 ;
        RECT 776.110 0.000 776.390 4.000 ;
    END
  END la_data_out[4]
  PIN la_data_out[50]
    DIRECTION OUTPUT TRISTATE ;
    USE SIGNAL ;
    ANTENNADIFFAREA 0.445500 ;
    PORT
      LAYER met3 ;
        RECT 0.000 258.440 4.000 259.040 ;
    END
  END la_data_out[50]
  PIN la_data_out[51]
    DIRECTION OUTPUT TRISTATE ;
    USE SIGNAL ;
    ANTENNADIFFAREA 0.445500 ;
    PORT
      LAYER met2 ;
        RECT 798.650 896.000 798.930 900.000 ;
    END
  END la_data_out[51]
  PIN la_data_out[52]
    DIRECTION OUTPUT TRISTATE ;
    USE SIGNAL ;
    ANTENNADIFFAREA 0.445500 ;
    PORT
      LAYER met3 ;
        RECT 0.000 809.240 4.000 809.840 ;
    END
  END la_data_out[52]
  PIN la_data_out[53]
    DIRECTION OUTPUT TRISTATE ;
    USE SIGNAL ;
    ANTENNADIFFAREA 0.445500 ;
    PORT
      LAYER met2 ;
        RECT 508.850 0.000 509.130 4.000 ;
    END
  END la_data_out[53]
  PIN la_data_out[54]
    DIRECTION OUTPUT TRISTATE ;
    USE SIGNAL ;
    ANTENNADIFFAREA 0.445500 ;
    PORT
      LAYER met3 ;
        RECT 0.000 119.040 4.000 119.640 ;
    END
  END la_data_out[54]
  PIN la_data_out[55]
    DIRECTION OUTPUT TRISTATE ;
    USE SIGNAL ;
    ANTENNADIFFAREA 0.445500 ;
    PORT
      LAYER met2 ;
        RECT 618.330 896.000 618.610 900.000 ;
    END
  END la_data_out[55]
  PIN la_data_out[56]
    DIRECTION OUTPUT TRISTATE ;
    USE SIGNAL ;
    ANTENNADIFFAREA 0.445500 ;
    PORT
      LAYER met3 ;
        RECT 0.000 571.240 4.000 571.840 ;
    END
  END la_data_out[56]
  PIN la_data_out[57]
    DIRECTION OUTPUT TRISTATE ;
    USE SIGNAL ;
    ANTENNADIFFAREA 0.445500 ;
    PORT
      LAYER met2 ;
        RECT 283.450 0.000 283.730 4.000 ;
    END
  END la_data_out[57]
  PIN la_data_out[58]
    DIRECTION OUTPUT TRISTATE ;
    USE SIGNAL ;
    ANTENNADIFFAREA 0.445500 ;
    PORT
      LAYER met2 ;
        RECT 579.690 0.000 579.970 4.000 ;
    END
  END la_data_out[58]
  PIN la_data_out[59]
    DIRECTION OUTPUT TRISTATE ;
    USE SIGNAL ;
    ANTENNADIFFAREA 0.445500 ;
    PORT
      LAYER met2 ;
        RECT 515.290 896.000 515.570 900.000 ;
    END
  END la_data_out[59]
  PIN la_data_out[5]
    DIRECTION OUTPUT TRISTATE ;
    USE SIGNAL ;
    ANTENNADIFFAREA 0.445500 ;
    PORT
      LAYER met3 ;
        RECT 896.000 68.040 900.000 68.640 ;
    END
  END la_data_out[5]
  PIN la_data_out[60]
    DIRECTION OUTPUT TRISTATE ;
    USE SIGNAL ;
    ANTENNADIFFAREA 0.445500 ;
    PORT
      LAYER met3 ;
        RECT 896.000 486.240 900.000 486.840 ;
    END
  END la_data_out[60]
  PIN la_data_out[61]
    DIRECTION OUTPUT TRISTATE ;
    USE SIGNAL ;
    ANTENNADIFFAREA 0.445500 ;
    PORT
      LAYER met2 ;
        RECT 492.750 0.000 493.030 4.000 ;
    END
  END la_data_out[61]
  PIN la_data_out[62]
    DIRECTION OUTPUT TRISTATE ;
    USE SIGNAL ;
    ANTENNADIFFAREA 0.445500 ;
    PORT
      LAYER met2 ;
        RECT 479.870 0.000 480.150 4.000 ;
    END
  END la_data_out[62]
  PIN la_data_out[63]
    DIRECTION OUTPUT TRISTATE ;
    USE SIGNAL ;
    ANTENNADIFFAREA 0.445500 ;
    PORT
      LAYER met2 ;
        RECT 157.870 896.000 158.150 900.000 ;
    END
  END la_data_out[63]
  PIN la_data_out[64]
    DIRECTION OUTPUT TRISTATE ;
    USE SIGNAL ;
    ANTENNADIFFAREA 0.445500 ;
    PORT
      LAYER met2 ;
        RECT 611.890 896.000 612.170 900.000 ;
    END
  END la_data_out[64]
  PIN la_data_out[65]
    DIRECTION OUTPUT TRISTATE ;
    USE SIGNAL ;
    ANTENNADIFFAREA 0.445500 ;
    PORT
      LAYER met3 ;
        RECT 0.000 265.240 4.000 265.840 ;
    END
  END la_data_out[65]
  PIN la_data_out[66]
    DIRECTION OUTPUT TRISTATE ;
    USE SIGNAL ;
    ANTENNADIFFAREA 0.445500 ;
    PORT
      LAYER met3 ;
        RECT 0.000 391.040 4.000 391.640 ;
    END
  END la_data_out[66]
  PIN la_data_out[67]
    DIRECTION OUTPUT TRISTATE ;
    USE SIGNAL ;
    ANTENNADIFFAREA 0.445500 ;
    PORT
      LAYER met2 ;
        RECT 721.370 0.000 721.650 4.000 ;
    END
  END la_data_out[67]
  PIN la_data_out[68]
    DIRECTION OUTPUT TRISTATE ;
    USE SIGNAL ;
    ANTENNADIFFAREA 0.445500 ;
    PORT
      LAYER met2 ;
        RECT 70.930 896.000 71.210 900.000 ;
    END
  END la_data_out[68]
  PIN la_data_out[69]
    DIRECTION OUTPUT TRISTATE ;
    USE SIGNAL ;
    ANTENNADIFFAREA 0.445500 ;
    PORT
      LAYER met3 ;
        RECT 896.000 537.240 900.000 537.840 ;
    END
  END la_data_out[69]
  PIN la_data_out[6]
    DIRECTION OUTPUT TRISTATE ;
    USE SIGNAL ;
    ANTENNADIFFAREA 0.445500 ;
    PORT
      LAYER met3 ;
        RECT 896.000 231.240 900.000 231.840 ;
    END
  END la_data_out[6]
  PIN la_data_out[70]
    DIRECTION OUTPUT TRISTATE ;
    USE SIGNAL ;
    ANTENNADIFFAREA 0.445500 ;
    PORT
      LAYER met2 ;
        RECT 141.770 896.000 142.050 900.000 ;
    END
  END la_data_out[70]
  PIN la_data_out[71]
    DIRECTION OUTPUT TRISTATE ;
    USE SIGNAL ;
    ANTENNADIFFAREA 0.445500 ;
    PORT
      LAYER met2 ;
        RECT 438.010 0.000 438.290 4.000 ;
    END
  END la_data_out[71]
  PIN la_data_out[72]
    DIRECTION OUTPUT TRISTATE ;
    USE SIGNAL ;
    ANTENNADIFFAREA 0.445500 ;
    PORT
      LAYER met2 ;
        RECT 650.530 0.000 650.810 4.000 ;
    END
  END la_data_out[72]
  PIN la_data_out[73]
    DIRECTION OUTPUT TRISTATE ;
    USE SIGNAL ;
    ANTENNADIFFAREA 0.445500 ;
    PORT
      LAYER met3 ;
        RECT 0.000 68.040 4.000 68.640 ;
    END
  END la_data_out[73]
  PIN la_data_out[74]
    DIRECTION OUTPUT TRISTATE ;
    USE SIGNAL ;
    ANTENNADIFFAREA 0.445500 ;
    PORT
      LAYER met2 ;
        RECT 734.250 896.000 734.530 900.000 ;
    END
  END la_data_out[74]
  PIN la_data_out[75]
    DIRECTION OUTPUT TRISTATE ;
    USE SIGNAL ;
    ANTENNADIFFAREA 0.445500 ;
    PORT
      LAYER met2 ;
        RECT 495.970 0.000 496.250 4.000 ;
    END
  END la_data_out[75]
  PIN la_data_out[76]
    DIRECTION OUTPUT TRISTATE ;
    USE SIGNAL ;
    ANTENNADIFFAREA 0.445500 ;
    PORT
      LAYER met2 ;
        RECT 486.310 896.000 486.590 900.000 ;
    END
  END la_data_out[76]
  PIN la_data_out[77]
    DIRECTION OUTPUT TRISTATE ;
    USE SIGNAL ;
    ANTENNADIFFAREA 0.445500 ;
    PORT
      LAYER met2 ;
        RECT 550.710 0.000 550.990 4.000 ;
    END
  END la_data_out[77]
  PIN la_data_out[78]
    DIRECTION OUTPUT TRISTATE ;
    USE SIGNAL ;
    ANTENNADIFFAREA 0.445500 ;
    PORT
      LAYER met2 ;
        RECT 54.830 896.000 55.110 900.000 ;
    END
  END la_data_out[78]
  PIN la_data_out[79]
    DIRECTION OUTPUT TRISTATE ;
    USE SIGNAL ;
    ANTENNADIFFAREA 0.445500 ;
    PORT
      LAYER met3 ;
        RECT 0.000 482.840 4.000 483.440 ;
    END
  END la_data_out[79]
  PIN la_data_out[7]
    DIRECTION OUTPUT TRISTATE ;
    USE SIGNAL ;
    ANTENNADIFFAREA 0.445500 ;
    PORT
      LAYER met2 ;
        RECT 457.330 0.000 457.610 4.000 ;
    END
  END la_data_out[7]
  PIN la_data_out[80]
    DIRECTION OUTPUT TRISTATE ;
    USE SIGNAL ;
    ANTENNADIFFAREA 0.445500 ;
    PORT
      LAYER met3 ;
        RECT 896.000 108.840 900.000 109.440 ;
    END
  END la_data_out[80]
  PIN la_data_out[81]
    DIRECTION OUTPUT TRISTATE ;
    USE SIGNAL ;
    ANTENNADIFFAREA 0.445500 ;
    PORT
      LAYER met2 ;
        RECT 869.490 0.000 869.770 4.000 ;
    END
  END la_data_out[81]
  PIN la_data_out[82]
    DIRECTION OUTPUT TRISTATE ;
    USE SIGNAL ;
    ANTENNADIFFAREA 0.445500 ;
    PORT
      LAYER met3 ;
        RECT 896.000 224.440 900.000 225.040 ;
    END
  END la_data_out[82]
  PIN la_data_out[83]
    DIRECTION OUTPUT TRISTATE ;
    USE SIGNAL ;
    ANTENNADIFFAREA 0.445500 ;
    PORT
      LAYER met2 ;
        RECT 228.710 896.000 228.990 900.000 ;
    END
  END la_data_out[83]
  PIN la_data_out[84]
    DIRECTION OUTPUT TRISTATE ;
    USE SIGNAL ;
    ANTENNADIFFAREA 0.445500 ;
    PORT
      LAYER met2 ;
        RECT 344.630 0.000 344.910 4.000 ;
    END
  END la_data_out[84]
  PIN la_data_out[85]
    DIRECTION OUTPUT TRISTATE ;
    USE SIGNAL ;
    ANTENNADIFFAREA 0.445500 ;
    PORT
      LAYER met3 ;
        RECT 0.000 802.440 4.000 803.040 ;
    END
  END la_data_out[85]
  PIN la_data_out[86]
    DIRECTION OUTPUT TRISTATE ;
    USE SIGNAL ;
    ANTENNADIFFAREA 0.445500 ;
    PORT
      LAYER met3 ;
        RECT 0.000 306.040 4.000 306.640 ;
    END
  END la_data_out[86]
  PIN la_data_out[87]
    DIRECTION OUTPUT TRISTATE ;
    USE SIGNAL ;
    ANTENNADIFFAREA 0.445500 ;
    PORT
      LAYER met2 ;
        RECT 830.850 896.000 831.130 900.000 ;
    END
  END la_data_out[87]
  PIN la_data_out[88]
    DIRECTION OUTPUT TRISTATE ;
    USE SIGNAL ;
    ANTENNADIFFAREA 0.445500 ;
    PORT
      LAYER met2 ;
        RECT 743.910 0.000 744.190 4.000 ;
    END
  END la_data_out[88]
  PIN la_data_out[89]
    DIRECTION OUTPUT TRISTATE ;
    USE SIGNAL ;
    ANTENNADIFFAREA 0.445500 ;
    PORT
      LAYER met2 ;
        RECT 206.170 896.000 206.450 900.000 ;
    END
  END la_data_out[89]
  PIN la_data_out[8]
    DIRECTION OUTPUT TRISTATE ;
    USE SIGNAL ;
    ANTENNADIFFAREA 0.445500 ;
    PORT
      LAYER met3 ;
        RECT 0.000 159.840 4.000 160.440 ;
    END
  END la_data_out[8]
  PIN la_data_out[90]
    DIRECTION OUTPUT TRISTATE ;
    USE SIGNAL ;
    ANTENNADIFFAREA 0.445500 ;
    PORT
      LAYER met3 ;
        RECT 896.000 6.840 900.000 7.440 ;
    END
  END la_data_out[90]
  PIN la_data_out[91]
    DIRECTION OUTPUT TRISTATE ;
    USE SIGNAL ;
    ANTENNADIFFAREA 0.445500 ;
    PORT
      LAYER met3 ;
        RECT 896.000 510.040 900.000 510.640 ;
    END
  END la_data_out[91]
  PIN la_data_out[92]
    DIRECTION OUTPUT TRISTATE ;
    USE SIGNAL ;
    ANTENNADIFFAREA 0.445500 ;
    PORT
      LAYER met2 ;
        RECT 425.130 896.000 425.410 900.000 ;
    END
  END la_data_out[92]
  PIN la_data_out[93]
    DIRECTION OUTPUT TRISTATE ;
    USE SIGNAL ;
    ANTENNADIFFAREA 0.445500 ;
    PORT
      LAYER met2 ;
        RECT 299.550 896.000 299.830 900.000 ;
    END
  END la_data_out[93]
  PIN la_data_out[94]
    DIRECTION OUTPUT TRISTATE ;
    USE SIGNAL ;
    ANTENNADIFFAREA 0.445500 ;
    PORT
      LAYER met2 ;
        RECT 405.810 896.000 406.090 900.000 ;
    END
  END la_data_out[94]
  PIN la_data_out[95]
    DIRECTION OUTPUT TRISTATE ;
    USE SIGNAL ;
    ANTENNADIFFAREA 0.445500 ;
    PORT
      LAYER met2 ;
        RECT 689.170 896.000 689.450 900.000 ;
    END
  END la_data_out[95]
  PIN la_data_out[96]
    DIRECTION OUTPUT TRISTATE ;
    USE SIGNAL ;
    ANTENNADIFFAREA 0.445500 ;
    PORT
      LAYER met2 ;
        RECT 689.170 0.000 689.450 4.000 ;
    END
  END la_data_out[96]
  PIN la_data_out[97]
    DIRECTION OUTPUT TRISTATE ;
    USE SIGNAL ;
    ANTENNADIFFAREA 0.445500 ;
    PORT
      LAYER met2 ;
        RECT 769.670 0.000 769.950 4.000 ;
    END
  END la_data_out[97]
  PIN la_data_out[98]
    DIRECTION OUTPUT TRISTATE ;
    USE SIGNAL ;
    ANTENNADIFFAREA 0.445500 ;
    PORT
      LAYER met3 ;
        RECT 0.000 870.440 4.000 871.040 ;
    END
  END la_data_out[98]
  PIN la_data_out[99]
    DIRECTION OUTPUT TRISTATE ;
    USE SIGNAL ;
    ANTENNADIFFAREA 0.445500 ;
    PORT
      LAYER met2 ;
        RECT 260.910 0.000 261.190 4.000 ;
    END
  END la_data_out[99]
  PIN la_data_out[9]
    DIRECTION OUTPUT TRISTATE ;
    USE SIGNAL ;
    ANTENNADIFFAREA 0.445500 ;
    PORT
      LAYER met2 ;
        RECT 885.590 896.000 885.870 900.000 ;
    END
  END la_data_out[9]
  PIN la_oenb[0]
    DIRECTION INPUT ;
    USE SIGNAL ;
    PORT
      LAYER met3 ;
        RECT 0.000 438.640 4.000 439.240 ;
    END
  END la_oenb[0]
  PIN la_oenb[100]
    DIRECTION INPUT ;
    USE SIGNAL ;
    PORT
      LAYER met3 ;
        RECT 0.000 268.640 4.000 269.240 ;
    END
  END la_oenb[100]
  PIN la_oenb[101]
    DIRECTION INPUT ;
    USE SIGNAL ;
    PORT
      LAYER met2 ;
        RECT 705.270 896.000 705.550 900.000 ;
    END
  END la_oenb[101]
  PIN la_oenb[102]
    DIRECTION INPUT ;
    USE SIGNAL ;
    PORT
      LAYER met2 ;
        RECT 679.510 896.000 679.790 900.000 ;
    END
  END la_oenb[102]
  PIN la_oenb[103]
    DIRECTION INPUT ;
    USE SIGNAL ;
    PORT
      LAYER met3 ;
        RECT 896.000 23.840 900.000 24.440 ;
    END
  END la_oenb[103]
  PIN la_oenb[104]
    DIRECTION INPUT ;
    USE SIGNAL ;
    PORT
      LAYER met2 ;
        RECT 409.030 0.000 409.310 4.000 ;
    END
  END la_oenb[104]
  PIN la_oenb[105]
    DIRECTION INPUT ;
    USE SIGNAL ;
    PORT
      LAYER met2 ;
        RECT 22.630 896.000 22.910 900.000 ;
    END
  END la_oenb[105]
  PIN la_oenb[106]
    DIRECTION INPUT ;
    USE SIGNAL ;
    PORT
      LAYER met2 ;
        RECT 859.830 896.000 860.110 900.000 ;
    END
  END la_oenb[106]
  PIN la_oenb[107]
    DIRECTION INPUT ;
    USE SIGNAL ;
    PORT
      LAYER met3 ;
        RECT 896.000 125.840 900.000 126.440 ;
    END
  END la_oenb[107]
  PIN la_oenb[108]
    DIRECTION INPUT ;
    USE SIGNAL ;
    PORT
      LAYER met2 ;
        RECT 695.610 896.000 695.890 900.000 ;
    END
  END la_oenb[108]
  PIN la_oenb[109]
    DIRECTION INPUT ;
    USE SIGNAL ;
    PORT
      LAYER met2 ;
        RECT 235.150 0.000 235.430 4.000 ;
    END
  END la_oenb[109]
  PIN la_oenb[10]
    DIRECTION INPUT ;
    USE SIGNAL ;
    PORT
      LAYER met3 ;
        RECT 0.000 210.840 4.000 211.440 ;
    END
  END la_oenb[10]
  PIN la_oenb[110]
    DIRECTION INPUT ;
    USE SIGNAL ;
    PORT
      LAYER met2 ;
        RECT 666.630 0.000 666.910 4.000 ;
    END
  END la_oenb[110]
  PIN la_oenb[111]
    DIRECTION INPUT ;
    USE SIGNAL ;
    PORT
      LAYER met2 ;
        RECT 821.190 896.000 821.470 900.000 ;
    END
  END la_oenb[111]
  PIN la_oenb[112]
    DIRECTION INPUT ;
    USE SIGNAL ;
    PORT
      LAYER met2 ;
        RECT 305.990 896.000 306.270 900.000 ;
    END
  END la_oenb[112]
  PIN la_oenb[113]
    DIRECTION INPUT ;
    USE SIGNAL ;
    PORT
      LAYER met3 ;
        RECT 0.000 639.240 4.000 639.840 ;
    END
  END la_oenb[113]
  PIN la_oenb[114]
    DIRECTION INPUT ;
    USE SIGNAL ;
    PORT
      LAYER met2 ;
        RECT 640.870 896.000 641.150 900.000 ;
    END
  END la_oenb[114]
  PIN la_oenb[115]
    DIRECTION INPUT ;
    USE SIGNAL ;
    PORT
      LAYER met2 ;
        RECT 363.950 0.000 364.230 4.000 ;
    END
  END la_oenb[115]
  PIN la_oenb[116]
    DIRECTION INPUT ;
    USE SIGNAL ;
    PORT
      LAYER met3 ;
        RECT 896.000 727.640 900.000 728.240 ;
    END
  END la_oenb[116]
  PIN la_oenb[117]
    DIRECTION INPUT ;
    USE SIGNAL ;
    PORT
      LAYER met2 ;
        RECT 660.190 0.000 660.470 4.000 ;
    END
  END la_oenb[117]
  PIN la_oenb[118]
    DIRECTION INPUT ;
    USE SIGNAL ;
    PORT
      LAYER met3 ;
        RECT 896.000 503.240 900.000 503.840 ;
    END
  END la_oenb[118]
  PIN la_oenb[119]
    DIRECTION INPUT ;
    USE SIGNAL ;
    PORT
      LAYER met2 ;
        RECT 173.970 0.000 174.250 4.000 ;
    END
  END la_oenb[119]
  PIN la_oenb[11]
    DIRECTION INPUT ;
    USE SIGNAL ;
    PORT
      LAYER met2 ;
        RECT 470.210 896.000 470.490 900.000 ;
    END
  END la_oenb[11]
  PIN la_oenb[120]
    DIRECTION INPUT ;
    USE SIGNAL ;
    PORT
      LAYER met2 ;
        RECT 528.170 0.000 528.450 4.000 ;
    END
  END la_oenb[120]
  PIN la_oenb[121]
    DIRECTION INPUT ;
    USE SIGNAL ;
    PORT
      LAYER met2 ;
        RECT 470.210 0.000 470.490 4.000 ;
    END
  END la_oenb[121]
  PIN la_oenb[122]
    DIRECTION INPUT ;
    USE SIGNAL ;
    PORT
      LAYER met3 ;
        RECT 0.000 404.640 4.000 405.240 ;
    END
  END la_oenb[122]
  PIN la_oenb[123]
    DIRECTION INPUT ;
    USE SIGNAL ;
    PORT
      LAYER met3 ;
        RECT 896.000 380.840 900.000 381.440 ;
    END
  END la_oenb[123]
  PIN la_oenb[124]
    DIRECTION INPUT ;
    USE SIGNAL ;
    PORT
      LAYER met3 ;
        RECT 0.000 408.040 4.000 408.640 ;
    END
  END la_oenb[124]
  PIN la_oenb[125]
    DIRECTION INPUT ;
    USE SIGNAL ;
    PORT
      LAYER met3 ;
        RECT 896.000 544.040 900.000 544.640 ;
    END
  END la_oenb[125]
  PIN la_oenb[126]
    DIRECTION INPUT ;
    USE SIGNAL ;
    PORT
      LAYER met2 ;
        RECT 173.970 896.000 174.250 900.000 ;
    END
  END la_oenb[126]
  PIN la_oenb[127]
    DIRECTION INPUT ;
    USE SIGNAL ;
    PORT
      LAYER met2 ;
        RECT 328.530 0.000 328.810 4.000 ;
    END
  END la_oenb[127]
  PIN la_oenb[12]
    DIRECTION INPUT ;
    USE SIGNAL ;
    PORT
      LAYER met2 ;
        RECT 508.850 896.000 509.130 900.000 ;
    END
  END la_oenb[12]
  PIN la_oenb[13]
    DIRECTION INPUT ;
    USE SIGNAL ;
    PORT
      LAYER met3 ;
        RECT 0.000 656.240 4.000 656.840 ;
    END
  END la_oenb[13]
  PIN la_oenb[14]
    DIRECTION INPUT ;
    USE SIGNAL ;
    PORT
      LAYER met3 ;
        RECT 896.000 323.040 900.000 323.640 ;
    END
  END la_oenb[14]
  PIN la_oenb[15]
    DIRECTION INPUT ;
    USE SIGNAL ;
    PORT
      LAYER met3 ;
        RECT 896.000 462.440 900.000 463.040 ;
    END
  END la_oenb[15]
  PIN la_oenb[16]
    DIRECTION INPUT ;
    USE SIGNAL ;
    PORT
      LAYER met2 ;
        RECT 747.130 0.000 747.410 4.000 ;
    END
  END la_oenb[16]
  PIN la_oenb[17]
    DIRECTION INPUT ;
    USE SIGNAL ;
    PORT
      LAYER met3 ;
        RECT 0.000 91.840 4.000 92.440 ;
    END
  END la_oenb[17]
  PIN la_oenb[18]
    DIRECTION INPUT ;
    USE SIGNAL ;
    PORT
      LAYER met3 ;
        RECT 0.000 714.040 4.000 714.640 ;
    END
  END la_oenb[18]
  PIN la_oenb[19]
    DIRECTION INPUT ;
    USE SIGNAL ;
    PORT
      LAYER met3 ;
        RECT 0.000 357.040 4.000 357.640 ;
    END
  END la_oenb[19]
  PIN la_oenb[1]
    DIRECTION INPUT ;
    USE SIGNAL ;
    PORT
      LAYER met3 ;
        RECT 0.000 217.640 4.000 218.240 ;
    END
  END la_oenb[1]
  PIN la_oenb[20]
    DIRECTION INPUT ;
    USE SIGNAL ;
    PORT
      LAYER met3 ;
        RECT 0.000 102.040 4.000 102.640 ;
    END
  END la_oenb[20]
  PIN la_oenb[21]
    DIRECTION INPUT ;
    USE SIGNAL ;
    PORT
      LAYER met2 ;
        RECT 254.470 0.000 254.750 4.000 ;
    END
  END la_oenb[21]
  PIN la_oenb[22]
    DIRECTION INPUT ;
    USE SIGNAL ;
    PORT
      LAYER met3 ;
        RECT 896.000 173.440 900.000 174.040 ;
    END
  END la_oenb[22]
  PIN la_oenb[23]
    DIRECTION INPUT ;
    USE SIGNAL ;
    PORT
      LAYER met2 ;
        RECT 58.050 0.000 58.330 4.000 ;
    END
  END la_oenb[23]
  PIN la_oenb[24]
    DIRECTION INPUT ;
    USE SIGNAL ;
    PORT
      LAYER met2 ;
        RECT 267.350 0.000 267.630 4.000 ;
    END
  END la_oenb[24]
  PIN la_oenb[25]
    DIRECTION INPUT ;
    USE SIGNAL ;
    PORT
      LAYER met3 ;
        RECT 896.000 149.640 900.000 150.240 ;
    END
  END la_oenb[25]
  PIN la_oenb[26]
    DIRECTION INPUT ;
    USE SIGNAL ;
    PORT
      LAYER met3 ;
        RECT 0.000 629.040 4.000 629.640 ;
    END
  END la_oenb[26]
  PIN la_oenb[27]
    DIRECTION INPUT ;
    USE SIGNAL ;
    PORT
      LAYER met3 ;
        RECT 896.000 397.840 900.000 398.440 ;
    END
  END la_oenb[27]
  PIN la_oenb[28]
    DIRECTION INPUT ;
    USE SIGNAL ;
    PORT
      LAYER met2 ;
        RECT 96.690 0.000 96.970 4.000 ;
    END
  END la_oenb[28]
  PIN la_oenb[29]
    DIRECTION INPUT ;
    USE SIGNAL ;
    PORT
      LAYER met3 ;
        RECT 896.000 329.840 900.000 330.440 ;
    END
  END la_oenb[29]
  PIN la_oenb[2]
    DIRECTION INPUT ;
    USE SIGNAL ;
    PORT
      LAYER met2 ;
        RECT 627.990 0.000 628.270 4.000 ;
    END
  END la_oenb[2]
  PIN la_oenb[30]
    DIRECTION INPUT ;
    USE SIGNAL ;
    PORT
      LAYER met3 ;
        RECT 0.000 867.040 4.000 867.640 ;
    END
  END la_oenb[30]
  PIN la_oenb[31]
    DIRECTION INPUT ;
    USE SIGNAL ;
    PORT
      LAYER met2 ;
        RECT 582.910 0.000 583.190 4.000 ;
    END
  END la_oenb[31]
  PIN la_oenb[32]
    DIRECTION INPUT ;
    USE SIGNAL ;
    PORT
      LAYER met3 ;
        RECT 896.000 520.240 900.000 520.840 ;
    END
  END la_oenb[32]
  PIN la_oenb[33]
    DIRECTION INPUT ;
    USE SIGNAL ;
    PORT
      LAYER met2 ;
        RECT 853.390 896.000 853.670 900.000 ;
    END
  END la_oenb[33]
  PIN la_oenb[34]
    DIRECTION INPUT ;
    USE SIGNAL ;
    PORT
      LAYER met2 ;
        RECT 753.570 896.000 753.850 900.000 ;
    END
  END la_oenb[34]
  PIN la_oenb[35]
    DIRECTION INPUT ;
    USE SIGNAL ;
    PORT
      LAYER met3 ;
        RECT 0.000 703.840 4.000 704.440 ;
    END
  END la_oenb[35]
  PIN la_oenb[36]
    DIRECTION INPUT ;
    USE SIGNAL ;
    PORT
      LAYER met2 ;
        RECT 863.050 896.000 863.330 900.000 ;
    END
  END la_oenb[36]
  PIN la_oenb[37]
    DIRECTION INPUT ;
    USE SIGNAL ;
    PORT
      LAYER met3 ;
        RECT 0.000 136.040 4.000 136.640 ;
    END
  END la_oenb[37]
  PIN la_oenb[38]
    DIRECTION INPUT ;
    USE SIGNAL ;
    PORT
      LAYER met2 ;
        RECT 16.190 896.000 16.470 900.000 ;
    END
  END la_oenb[38]
  PIN la_oenb[39]
    DIRECTION INPUT ;
    USE SIGNAL ;
    PORT
      LAYER met3 ;
        RECT 896.000 64.640 900.000 65.240 ;
    END
  END la_oenb[39]
  PIN la_oenb[3]
    DIRECTION INPUT ;
    USE SIGNAL ;
    PORT
      LAYER met3 ;
        RECT 896.000 306.040 900.000 306.640 ;
    END
  END la_oenb[3]
  PIN la_oenb[40]
    DIRECTION INPUT ;
    USE SIGNAL ;
    PORT
      LAYER met3 ;
        RECT 0.000 367.240 4.000 367.840 ;
    END
  END la_oenb[40]
  PIN la_oenb[41]
    DIRECTION INPUT ;
    USE SIGNAL ;
    PORT
      LAYER met2 ;
        RECT 399.370 896.000 399.650 900.000 ;
    END
  END la_oenb[41]
  PIN la_oenb[42]
    DIRECTION INPUT ;
    USE SIGNAL ;
    PORT
      LAYER met2 ;
        RECT 698.830 0.000 699.110 4.000 ;
    END
  END la_oenb[42]
  PIN la_oenb[43]
    DIRECTION INPUT ;
    USE SIGNAL ;
    PORT
      LAYER met3 ;
        RECT 0.000 557.640 4.000 558.240 ;
    END
  END la_oenb[43]
  PIN la_oenb[44]
    DIRECTION INPUT ;
    USE SIGNAL ;
    PORT
      LAYER met3 ;
        RECT 0.000 479.440 4.000 480.040 ;
    END
  END la_oenb[44]
  PIN la_oenb[45]
    DIRECTION INPUT ;
    USE SIGNAL ;
    PORT
      LAYER met2 ;
        RECT 782.550 896.000 782.830 900.000 ;
    END
  END la_oenb[45]
  PIN la_oenb[46]
    DIRECTION INPUT ;
    USE SIGNAL ;
    PORT
      LAYER met3 ;
        RECT 896.000 850.040 900.000 850.640 ;
    END
  END la_oenb[46]
  PIN la_oenb[47]
    DIRECTION INPUT ;
    USE SIGNAL ;
    PORT
      LAYER met2 ;
        RECT 837.290 0.000 837.570 4.000 ;
    END
  END la_oenb[47]
  PIN la_oenb[48]
    DIRECTION INPUT ;
    USE SIGNAL ;
    PORT
      LAYER met2 ;
        RECT 9.750 896.000 10.030 900.000 ;
    END
  END la_oenb[48]
  PIN la_oenb[49]
    DIRECTION INPUT ;
    USE SIGNAL ;
    PORT
      LAYER met2 ;
        RECT 801.870 0.000 802.150 4.000 ;
    END
  END la_oenb[49]
  PIN la_oenb[4]
    DIRECTION INPUT ;
    USE SIGNAL ;
    PORT
      LAYER met3 ;
        RECT 0.000 224.440 4.000 225.040 ;
    END
  END la_oenb[4]
  PIN la_oenb[50]
    DIRECTION INPUT ;
    USE SIGNAL ;
    PORT
      LAYER met2 ;
        RECT 164.310 0.000 164.590 4.000 ;
    END
  END la_oenb[50]
  PIN la_oenb[51]
    DIRECTION INPUT ;
    USE SIGNAL ;
    PORT
      LAYER met2 ;
        RECT 244.810 0.000 245.090 4.000 ;
    END
  END la_oenb[51]
  PIN la_oenb[52]
    DIRECTION INPUT ;
    USE SIGNAL ;
    PORT
      LAYER met2 ;
        RECT 856.610 0.000 856.890 4.000 ;
    END
  END la_oenb[52]
  PIN la_oenb[53]
    DIRECTION INPUT ;
    USE SIGNAL ;
    PORT
      LAYER met3 ;
        RECT 896.000 282.240 900.000 282.840 ;
    END
  END la_oenb[53]
  PIN la_oenb[54]
    DIRECTION INPUT ;
    USE SIGNAL ;
    PORT
      LAYER met3 ;
        RECT 896.000 768.440 900.000 769.040 ;
    END
  END la_oenb[54]
  PIN la_oenb[55]
    DIRECTION INPUT ;
    USE SIGNAL ;
    PORT
      LAYER met2 ;
        RECT 421.910 896.000 422.190 900.000 ;
    END
  END la_oenb[55]
  PIN la_oenb[56]
    DIRECTION INPUT ;
    USE SIGNAL ;
    PORT
      LAYER met3 ;
        RECT 0.000 530.440 4.000 531.040 ;
    END
  END la_oenb[56]
  PIN la_oenb[57]
    DIRECTION INPUT ;
    USE SIGNAL ;
    PORT
      LAYER met3 ;
        RECT 0.000 108.840 4.000 109.440 ;
    END
  END la_oenb[57]
  PIN la_oenb[58]
    DIRECTION INPUT ;
    USE SIGNAL ;
    PORT
      LAYER met3 ;
        RECT 0.000 431.840 4.000 432.440 ;
    END
  END la_oenb[58]
  PIN la_oenb[59]
    DIRECTION INPUT ;
    USE SIGNAL ;
    PORT
      LAYER met3 ;
        RECT 0.000 231.240 4.000 231.840 ;
    END
  END la_oenb[59]
  PIN la_oenb[5]
    DIRECTION INPUT ;
    USE SIGNAL ;
    PORT
      LAYER met3 ;
        RECT 0.000 646.040 4.000 646.640 ;
    END
  END la_oenb[5]
  PIN la_oenb[60]
    DIRECTION INPUT ;
    USE SIGNAL ;
    PORT
      LAYER met2 ;
        RECT 190.070 896.000 190.350 900.000 ;
    END
  END la_oenb[60]
  PIN la_oenb[61]
    DIRECTION INPUT ;
    USE SIGNAL ;
    PORT
      LAYER met3 ;
        RECT 0.000 74.840 4.000 75.440 ;
    END
  END la_oenb[61]
  PIN la_oenb[62]
    DIRECTION INPUT ;
    USE SIGNAL ;
    PORT
      LAYER met3 ;
        RECT 896.000 751.440 900.000 752.040 ;
    END
  END la_oenb[62]
  PIN la_oenb[63]
    DIRECTION INPUT ;
    USE SIGNAL ;
    PORT
      LAYER met2 ;
        RECT 589.350 896.000 589.630 900.000 ;
    END
  END la_oenb[63]
  PIN la_oenb[64]
    DIRECTION INPUT ;
    USE SIGNAL ;
    PORT
      LAYER met2 ;
        RECT 534.610 896.000 534.890 900.000 ;
    END
  END la_oenb[64]
  PIN la_oenb[65]
    DIRECTION INPUT ;
    USE SIGNAL ;
    PORT
      LAYER met2 ;
        RECT 698.830 896.000 699.110 900.000 ;
    END
  END la_oenb[65]
  PIN la_oenb[66]
    DIRECTION INPUT ;
    USE SIGNAL ;
    PORT
      LAYER met2 ;
        RECT 743.910 896.000 744.190 900.000 ;
    END
  END la_oenb[66]
  PIN la_oenb[67]
    DIRECTION INPUT ;
    USE SIGNAL ;
    PORT
      LAYER met2 ;
        RECT 750.350 896.000 750.630 900.000 ;
    END
  END la_oenb[67]
  PIN la_oenb[68]
    DIRECTION INPUT ;
    USE SIGNAL ;
    PORT
      LAYER met3 ;
        RECT 0.000 149.640 4.000 150.240 ;
    END
  END la_oenb[68]
  PIN la_oenb[69]
    DIRECTION INPUT ;
    USE SIGNAL ;
    PORT
      LAYER met2 ;
        RECT 447.670 896.000 447.950 900.000 ;
    END
  END la_oenb[69]
  PIN la_oenb[6]
    DIRECTION INPUT ;
    USE SIGNAL ;
    PORT
      LAYER met2 ;
        RECT 32.290 0.000 32.570 4.000 ;
    END
  END la_oenb[6]
  PIN la_oenb[70]
    DIRECTION INPUT ;
    USE SIGNAL ;
    PORT
      LAYER met2 ;
        RECT 9.750 0.000 10.030 4.000 ;
    END
  END la_oenb[70]
  PIN la_oenb[71]
    DIRECTION INPUT ;
    USE SIGNAL ;
    PORT
      LAYER met2 ;
        RECT 798.650 0.000 798.930 4.000 ;
    END
  END la_oenb[71]
  PIN la_oenb[72]
    DIRECTION INPUT ;
    USE SIGNAL ;
    PORT
      LAYER met2 ;
        RECT 541.050 0.000 541.330 4.000 ;
    END
  END la_oenb[72]
  PIN la_oenb[73]
    DIRECTION INPUT ;
    USE SIGNAL ;
    PORT
      LAYER met3 ;
        RECT 896.000 183.640 900.000 184.240 ;
    END
  END la_oenb[73]
  PIN la_oenb[74]
    DIRECTION INPUT ;
    USE SIGNAL ;
    PORT
      LAYER met3 ;
        RECT 0.000 635.840 4.000 636.440 ;
    END
  END la_oenb[74]
  PIN la_oenb[75]
    DIRECTION INPUT ;
    USE SIGNAL ;
    PORT
      LAYER met3 ;
        RECT 896.000 272.040 900.000 272.640 ;
    END
  END la_oenb[75]
  PIN la_oenb[76]
    DIRECTION INPUT ;
    USE SIGNAL ;
    PORT
      LAYER met3 ;
        RECT 0.000 142.840 4.000 143.440 ;
    END
  END la_oenb[76]
  PIN la_oenb[77]
    DIRECTION INPUT ;
    USE SIGNAL ;
    PORT
      LAYER met3 ;
        RECT 0.000 380.840 4.000 381.440 ;
    END
  END la_oenb[77]
  PIN la_oenb[78]
    DIRECTION INPUT ;
    USE SIGNAL ;
    PORT
      LAYER met3 ;
        RECT 0.000 323.040 4.000 323.640 ;
    END
  END la_oenb[78]
  PIN la_oenb[79]
    DIRECTION INPUT ;
    USE SIGNAL ;
    PORT
      LAYER met3 ;
        RECT 0.000 248.240 4.000 248.840 ;
    END
  END la_oenb[79]
  PIN la_oenb[7]
    DIRECTION INPUT ;
    USE SIGNAL ;
    PORT
      LAYER met2 ;
        RECT 431.570 896.000 431.850 900.000 ;
    END
  END la_oenb[7]
  PIN la_oenb[80]
    DIRECTION INPUT ;
    USE SIGNAL ;
    PORT
      LAYER met2 ;
        RECT 821.190 0.000 821.470 4.000 ;
    END
  END la_oenb[80]
  PIN la_oenb[81]
    DIRECTION INPUT ;
    USE SIGNAL ;
    PORT
      LAYER met2 ;
        RECT 386.490 0.000 386.770 4.000 ;
    END
  END la_oenb[81]
  PIN la_oenb[82]
    DIRECTION INPUT ;
    USE SIGNAL ;
    PORT
      LAYER met3 ;
        RECT 0.000 710.640 4.000 711.240 ;
    END
  END la_oenb[82]
  PIN la_oenb[83]
    DIRECTION INPUT ;
    USE SIGNAL ;
    PORT
      LAYER met3 ;
        RECT 896.000 649.440 900.000 650.040 ;
    END
  END la_oenb[83]
  PIN la_oenb[84]
    DIRECTION INPUT ;
    USE SIGNAL ;
    PORT
      LAYER met3 ;
        RECT 896.000 839.840 900.000 840.440 ;
    END
  END la_oenb[84]
  PIN la_oenb[85]
    DIRECTION INPUT ;
    USE SIGNAL ;
    PORT
      LAYER met2 ;
        RECT 785.770 0.000 786.050 4.000 ;
    END
  END la_oenb[85]
  PIN la_oenb[86]
    DIRECTION INPUT ;
    USE SIGNAL ;
    PORT
      LAYER met3 ;
        RECT 0.000 836.440 4.000 837.040 ;
    END
  END la_oenb[86]
  PIN la_oenb[87]
    DIRECTION INPUT ;
    USE SIGNAL ;
    PORT
      LAYER met3 ;
        RECT 896.000 105.440 900.000 106.040 ;
    END
  END la_oenb[87]
  PIN la_oenb[88]
    DIRECTION INPUT ;
    USE SIGNAL ;
    PORT
      LAYER met3 ;
        RECT 896.000 792.240 900.000 792.840 ;
    END
  END la_oenb[88]
  PIN la_oenb[89]
    DIRECTION INPUT ;
    USE SIGNAL ;
    PORT
      LAYER met2 ;
        RECT 312.430 896.000 312.710 900.000 ;
    END
  END la_oenb[89]
  PIN la_oenb[8]
    DIRECTION INPUT ;
    USE SIGNAL ;
    PORT
      LAYER met3 ;
        RECT 896.000 659.640 900.000 660.240 ;
    END
  END la_oenb[8]
  PIN la_oenb[90]
    DIRECTION INPUT ;
    USE SIGNAL ;
    PORT
      LAYER met2 ;
        RECT 766.450 0.000 766.730 4.000 ;
    END
  END la_oenb[90]
  PIN la_oenb[91]
    DIRECTION INPUT ;
    USE SIGNAL ;
    PORT
      LAYER met2 ;
        RECT 531.390 896.000 531.670 900.000 ;
    END
  END la_oenb[91]
  PIN la_oenb[92]
    DIRECTION INPUT ;
    USE SIGNAL ;
    PORT
      LAYER met3 ;
        RECT 896.000 214.240 900.000 214.840 ;
    END
  END la_oenb[92]
  PIN la_oenb[93]
    DIRECTION INPUT ;
    USE SIGNAL ;
    PORT
      LAYER met2 ;
        RECT 244.810 896.000 245.090 900.000 ;
    END
  END la_oenb[93]
  PIN la_oenb[94]
    DIRECTION INPUT ;
    USE SIGNAL ;
    PORT
      LAYER met3 ;
        RECT 896.000 30.640 900.000 31.240 ;
    END
  END la_oenb[94]
  PIN la_oenb[95]
    DIRECTION INPUT ;
    USE SIGNAL ;
    PORT
      LAYER met3 ;
        RECT 0.000 795.640 4.000 796.240 ;
    END
  END la_oenb[95]
  PIN la_oenb[96]
    DIRECTION INPUT ;
    USE SIGNAL ;
    PORT
      LAYER met2 ;
        RECT 125.670 0.000 125.950 4.000 ;
    END
  END la_oenb[96]
  PIN la_oenb[97]
    DIRECTION INPUT ;
    USE SIGNAL ;
    PORT
      LAYER met3 ;
        RECT 896.000 625.640 900.000 626.240 ;
    END
  END la_oenb[97]
  PIN la_oenb[98]
    DIRECTION INPUT ;
    USE SIGNAL ;
    PORT
      LAYER met2 ;
        RECT 563.590 0.000 563.870 4.000 ;
    END
  END la_oenb[98]
  PIN la_oenb[99]
    DIRECTION INPUT ;
    USE SIGNAL ;
    PORT
      LAYER met3 ;
        RECT 0.000 316.240 4.000 316.840 ;
    END
  END la_oenb[99]
  PIN la_oenb[9]
    DIRECTION INPUT ;
    USE SIGNAL ;
    PORT
      LAYER met2 ;
        RECT 251.250 0.000 251.530 4.000 ;
    END
  END la_oenb[9]
  PIN pwm_fall_out
    DIRECTION OUTPUT TRISTATE ;
    USE SIGNAL ;
    ANTENNADIFFAREA 0.445500 ;
    PORT
      LAYER met3 ;
        RECT 0.000 421.640 4.000 422.240 ;
    END
  END pwm_fall_out
  PIN pwm_rise_out
    DIRECTION OUTPUT TRISTATE ;
    USE SIGNAL ;
    ANTENNADIFFAREA 0.445500 ;
    PORT
      LAYER met3 ;
        RECT 0.000 877.240 4.000 877.840 ;
    END
  END pwm_rise_out
  PIN user_clock2
    DIRECTION INPUT ;
    USE SIGNAL ;
    PORT
      LAYER met3 ;
        RECT 0.000 442.040 4.000 442.640 ;
    END
  END user_clock2
  PIN user_irq[0]
    DIRECTION OUTPUT TRISTATE ;
    USE SIGNAL ;
    ANTENNADIFFAREA 0.445500 ;
    PORT
      LAYER met3 ;
        RECT 0.000 200.640 4.000 201.240 ;
    END
  END user_irq[0]
  PIN user_irq[1]
    DIRECTION OUTPUT TRISTATE ;
    USE SIGNAL ;
    ANTENNADIFFAREA 0.445500 ;
    PORT
      LAYER met3 ;
        RECT 0.000 846.640 4.000 847.240 ;
    END
  END user_irq[1]
  PIN user_irq[2]
    DIRECTION OUTPUT TRISTATE ;
    USE SIGNAL ;
    ANTENNADIFFAREA 0.445500 ;
    PORT
      LAYER met2 ;
        RECT 38.730 896.000 39.010 900.000 ;
    END
  END user_irq[2]
  PIN vccd1
    DIRECTION INOUT ;
    USE POWER ;
    PORT
      LAYER met4 ;
        RECT 21.040 10.640 22.640 886.960 ;
    END
    PORT
      LAYER met4 ;
        RECT 174.640 10.640 176.240 886.960 ;
    END
    PORT
      LAYER met4 ;
        RECT 328.240 10.640 329.840 886.960 ;
    END
    PORT
      LAYER met4 ;
        RECT 481.840 10.640 483.440 886.960 ;
    END
    PORT
      LAYER met4 ;
        RECT 635.440 10.640 637.040 886.960 ;
    END
    PORT
      LAYER met4 ;
        RECT 789.040 10.640 790.640 886.960 ;
    END
  END vccd1
  PIN vssd1
    DIRECTION INOUT ;
    USE GROUND ;
    PORT
      LAYER met4 ;
        RECT 97.840 10.640 99.440 886.960 ;
    END
    PORT
      LAYER met4 ;
        RECT 251.440 10.640 253.040 886.960 ;
    END
    PORT
      LAYER met4 ;
        RECT 405.040 10.640 406.640 886.960 ;
    END
    PORT
      LAYER met4 ;
        RECT 558.640 10.640 560.240 886.960 ;
    END
    PORT
      LAYER met4 ;
        RECT 712.240 10.640 713.840 886.960 ;
    END
    PORT
      LAYER met4 ;
        RECT 865.840 10.640 867.440 886.960 ;
    END
  END vssd1
  PIN wb_clk_i
    DIRECTION INPUT ;
    USE SIGNAL ;
    ANTENNAGATEAREA 0.213000 ;
    PORT
      LAYER met3 ;
        RECT 896.000 265.240 900.000 265.840 ;
    END
  END wb_clk_i
  PIN wb_rst_i
    DIRECTION INPUT ;
    USE SIGNAL ;
    PORT
      LAYER met3 ;
        RECT 0.000 499.840 4.000 500.440 ;
    END
  END wb_rst_i
  PIN wbs_ack_o
    DIRECTION OUTPUT TRISTATE ;
    USE SIGNAL ;
    ANTENNADIFFAREA 0.445500 ;
    PORT
      LAYER met3 ;
        RECT 896.000 438.640 900.000 439.240 ;
    END
  END wbs_ack_o
  PIN wbs_adr_i[0]
    DIRECTION INPUT ;
    USE SIGNAL ;
    ANTENNAGATEAREA 0.213000 ;
    PORT
      LAYER met2 ;
        RECT 370.390 896.000 370.670 900.000 ;
    END
  END wbs_adr_i[0]
  PIN wbs_adr_i[10]
    DIRECTION INPUT ;
    USE SIGNAL ;
    ANTENNAGATEAREA 0.247500 ;
    PORT
      LAYER met2 ;
        RECT 167.530 896.000 167.810 900.000 ;
    END
  END wbs_adr_i[10]
  PIN wbs_adr_i[11]
    DIRECTION INPUT ;
    USE SIGNAL ;
    ANTENNAGATEAREA 0.247500 ;
    PORT
      LAYER met3 ;
        RECT 0.000 673.240 4.000 673.840 ;
    END
  END wbs_adr_i[11]
  PIN wbs_adr_i[12]
    DIRECTION INPUT ;
    USE SIGNAL ;
    ANTENNAGATEAREA 0.426000 ;
    PORT
      LAYER met2 ;
        RECT 87.030 0.000 87.310 4.000 ;
    END
  END wbs_adr_i[12]
  PIN wbs_adr_i[13]
    DIRECTION INPUT ;
    USE SIGNAL ;
    ANTENNAGATEAREA 0.159000 ;
    PORT
      LAYER met3 ;
        RECT 0.000 520.240 4.000 520.840 ;
    END
  END wbs_adr_i[13]
  PIN wbs_adr_i[14]
    DIRECTION INPUT ;
    USE SIGNAL ;
    ANTENNAGATEAREA 0.426000 ;
    PORT
      LAYER met3 ;
        RECT 896.000 826.240 900.000 826.840 ;
    END
  END wbs_adr_i[14]
  PIN wbs_adr_i[15]
    DIRECTION INPUT ;
    USE SIGNAL ;
    ANTENNAGATEAREA 0.247500 ;
    PORT
      LAYER met3 ;
        RECT 896.000 765.040 900.000 765.640 ;
    END
  END wbs_adr_i[15]
  PIN wbs_adr_i[16]
    DIRECTION INPUT ;
    USE SIGNAL ;
    ANTENNAGATEAREA 0.247500 ;
    PORT
      LAYER met2 ;
        RECT 618.330 0.000 618.610 4.000 ;
    END
  END wbs_adr_i[16]
  PIN wbs_adr_i[17]
    DIRECTION INPUT ;
    USE SIGNAL ;
    ANTENNAGATEAREA 0.159000 ;
    PORT
      LAYER met3 ;
        RECT 896.000 686.840 900.000 687.440 ;
    END
  END wbs_adr_i[17]
  PIN wbs_adr_i[18]
    DIRECTION INPUT ;
    USE SIGNAL ;
    ANTENNAGATEAREA 0.196500 ;
    PORT
      LAYER met3 ;
        RECT 896.000 387.640 900.000 388.240 ;
    END
  END wbs_adr_i[18]
  PIN wbs_adr_i[19]
    DIRECTION INPUT ;
    USE SIGNAL ;
    ANTENNAGATEAREA 0.159000 ;
    PORT
      LAYER met3 ;
        RECT 896.000 34.040 900.000 34.640 ;
    END
  END wbs_adr_i[19]
  PIN wbs_adr_i[1]
    DIRECTION INPUT ;
    USE SIGNAL ;
    ANTENNAGATEAREA 0.213000 ;
    PORT
      LAYER met2 ;
        RECT 383.270 896.000 383.550 900.000 ;
    END
  END wbs_adr_i[1]
  PIN wbs_adr_i[20]
    DIRECTION INPUT ;
    USE SIGNAL ;
    ANTENNAGATEAREA 0.247500 ;
    PORT
      LAYER met2 ;
        RECT 656.970 896.000 657.250 900.000 ;
    END
  END wbs_adr_i[20]
  PIN wbs_adr_i[21]
    DIRECTION INPUT ;
    USE SIGNAL ;
    ANTENNAGATEAREA 0.159000 ;
    PORT
      LAYER met2 ;
        RECT 547.490 0.000 547.770 4.000 ;
    END
  END wbs_adr_i[21]
  PIN wbs_adr_i[22]
    DIRECTION INPUT ;
    USE SIGNAL ;
    ANTENNAGATEAREA 0.159000 ;
    PORT
      LAYER met2 ;
        RECT 782.550 0.000 782.830 4.000 ;
    END
  END wbs_adr_i[22]
  PIN wbs_adr_i[23]
    DIRECTION INPUT ;
    USE SIGNAL ;
    ANTENNAGATEAREA 0.213000 ;
    PORT
      LAYER met3 ;
        RECT 896.000 295.840 900.000 296.440 ;
    END
  END wbs_adr_i[23]
  PIN wbs_adr_i[24]
    DIRECTION INPUT ;
    USE SIGNAL ;
    ANTENNAGATEAREA 0.247500 ;
    PORT
      LAYER met3 ;
        RECT 0.000 788.840 4.000 789.440 ;
    END
  END wbs_adr_i[24]
  PIN wbs_adr_i[25]
    DIRECTION INPUT ;
    USE SIGNAL ;
    ANTENNAGATEAREA 0.247500 ;
    PORT
      LAYER met2 ;
        RECT 524.950 0.000 525.230 4.000 ;
    END
  END wbs_adr_i[25]
  PIN wbs_adr_i[26]
    DIRECTION INPUT ;
    USE SIGNAL ;
    ANTENNAGATEAREA 0.159000 ;
    PORT
      LAYER met2 ;
        RECT 103.130 0.000 103.410 4.000 ;
    END
  END wbs_adr_i[26]
  PIN wbs_adr_i[27]
    DIRECTION INPUT ;
    USE SIGNAL ;
    ANTENNAGATEAREA 0.196500 ;
    PORT
      LAYER met3 ;
        RECT 0.000 292.440 4.000 293.040 ;
    END
  END wbs_adr_i[27]
  PIN wbs_adr_i[28]
    DIRECTION INPUT ;
    USE SIGNAL ;
    ANTENNAGATEAREA 0.196500 ;
    PORT
      LAYER met3 ;
        RECT 896.000 642.640 900.000 643.240 ;
    END
  END wbs_adr_i[28]
  PIN wbs_adr_i[29]
    DIRECTION INPUT ;
    USE SIGNAL ;
    ANTENNAGATEAREA 0.213000 ;
    PORT
      LAYER met2 ;
        RECT 788.990 896.000 789.270 900.000 ;
    END
  END wbs_adr_i[29]
  PIN wbs_adr_i[2]
    DIRECTION INPUT ;
    USE SIGNAL ;
    ANTENNAGATEAREA 0.213000 ;
    PORT
      LAYER met2 ;
        RECT 370.390 0.000 370.670 4.000 ;
    END
  END wbs_adr_i[2]
  PIN wbs_adr_i[30]
    DIRECTION INPUT ;
    USE SIGNAL ;
    ANTENNAGATEAREA 0.213000 ;
    PORT
      LAYER met2 ;
        RECT 557.150 896.000 557.430 900.000 ;
    END
  END wbs_adr_i[30]
  PIN wbs_adr_i[31]
    DIRECTION INPUT ;
    USE SIGNAL ;
    ANTENNAGATEAREA 0.213000 ;
    PORT
      LAYER met3 ;
        RECT 896.000 476.040 900.000 476.640 ;
    END
  END wbs_adr_i[31]
  PIN wbs_adr_i[3]
    DIRECTION INPUT ;
    USE SIGNAL ;
    ANTENNAGATEAREA 0.426000 ;
    PORT
      LAYER met2 ;
        RECT 737.470 0.000 737.750 4.000 ;
    END
  END wbs_adr_i[3]
  PIN wbs_adr_i[4]
    DIRECTION INPUT ;
    USE SIGNAL ;
    ANTENNAGATEAREA 0.495000 ;
    PORT
      LAYER met2 ;
        RECT 541.050 896.000 541.330 900.000 ;
    END
  END wbs_adr_i[4]
  PIN wbs_adr_i[5]
    DIRECTION INPUT ;
    USE SIGNAL ;
    ANTENNAGATEAREA 0.159000 ;
    PORT
      LAYER met3 ;
        RECT 0.000 153.040 4.000 153.640 ;
    END
  END wbs_adr_i[5]
  PIN wbs_adr_i[6]
    DIRECTION INPUT ;
    USE SIGNAL ;
    ANTENNAGATEAREA 0.196500 ;
    PORT
      LAYER met2 ;
        RECT 299.550 0.000 299.830 4.000 ;
    END
  END wbs_adr_i[6]
  PIN wbs_adr_i[7]
    DIRECTION INPUT ;
    USE SIGNAL ;
    ANTENNAGATEAREA 0.159000 ;
    PORT
      LAYER met2 ;
        RECT 48.390 0.000 48.670 4.000 ;
    END
  END wbs_adr_i[7]
  PIN wbs_adr_i[8]
    DIRECTION INPUT ;
    USE SIGNAL ;
    ANTENNAGATEAREA 0.426000 ;
    PORT
      LAYER met3 ;
        RECT 896.000 47.640 900.000 48.240 ;
    END
  END wbs_adr_i[8]
  PIN wbs_adr_i[9]
    DIRECTION INPUT ;
    USE SIGNAL ;
    ANTENNAGATEAREA 0.247500 ;
    PORT
      LAYER met3 ;
        RECT 896.000 312.840 900.000 313.440 ;
    END
  END wbs_adr_i[9]
  PIN wbs_cyc_i
    DIRECTION INPUT ;
    USE SIGNAL ;
    ANTENNAGATEAREA 0.247500 ;
    PORT
      LAYER met2 ;
        RECT 132.110 896.000 132.390 900.000 ;
    END
  END wbs_cyc_i
  PIN wbs_dat_i[0]
    DIRECTION INPUT ;
    USE SIGNAL ;
    ANTENNAGATEAREA 0.495000 ;
    PORT
      LAYER met2 ;
        RECT 892.030 896.000 892.310 900.000 ;
    END
  END wbs_dat_i[0]
  PIN wbs_dat_i[10]
    DIRECTION INPUT ;
    USE SIGNAL ;
    PORT
      LAYER met3 ;
        RECT 0.000 506.640 4.000 507.240 ;
    END
  END wbs_dat_i[10]
  PIN wbs_dat_i[11]
    DIRECTION INPUT ;
    USE SIGNAL ;
    PORT
      LAYER met3 ;
        RECT 0.000 581.440 4.000 582.040 ;
    END
  END wbs_dat_i[11]
  PIN wbs_dat_i[12]
    DIRECTION INPUT ;
    USE SIGNAL ;
    PORT
      LAYER met3 ;
        RECT 0.000 554.240 4.000 554.840 ;
    END
  END wbs_dat_i[12]
  PIN wbs_dat_i[13]
    DIRECTION INPUT ;
    USE SIGNAL ;
    PORT
      LAYER met2 ;
        RECT 35.510 0.000 35.790 4.000 ;
    END
  END wbs_dat_i[13]
  PIN wbs_dat_i[14]
    DIRECTION INPUT ;
    USE SIGNAL ;
    PORT
      LAYER met2 ;
        RECT 199.730 0.000 200.010 4.000 ;
    END
  END wbs_dat_i[14]
  PIN wbs_dat_i[15]
    DIRECTION INPUT ;
    USE SIGNAL ;
    PORT
      LAYER met3 ;
        RECT 896.000 550.840 900.000 551.440 ;
    END
  END wbs_dat_i[15]
  PIN wbs_dat_i[16]
    DIRECTION INPUT ;
    USE SIGNAL ;
    PORT
      LAYER met3 ;
        RECT 0.000 61.240 4.000 61.840 ;
    END
  END wbs_dat_i[16]
  PIN wbs_dat_i[17]
    DIRECTION INPUT ;
    USE SIGNAL ;
    PORT
      LAYER met2 ;
        RECT 499.190 896.000 499.470 900.000 ;
    END
  END wbs_dat_i[17]
  PIN wbs_dat_i[18]
    DIRECTION INPUT ;
    USE SIGNAL ;
    PORT
      LAYER met2 ;
        RECT 727.810 896.000 728.090 900.000 ;
    END
  END wbs_dat_i[18]
  PIN wbs_dat_i[19]
    DIRECTION INPUT ;
    USE SIGNAL ;
    PORT
      LAYER met3 ;
        RECT 0.000 812.640 4.000 813.240 ;
    END
  END wbs_dat_i[19]
  PIN wbs_dat_i[1]
    DIRECTION INPUT ;
    USE SIGNAL ;
    ANTENNAGATEAREA 0.247500 ;
    PORT
      LAYER met3 ;
        RECT 0.000 251.640 4.000 252.240 ;
    END
  END wbs_dat_i[1]
  PIN wbs_dat_i[20]
    DIRECTION INPUT ;
    USE SIGNAL ;
    PORT
      LAYER met3 ;
        RECT 896.000 618.840 900.000 619.440 ;
    END
  END wbs_dat_i[20]
  PIN wbs_dat_i[21]
    DIRECTION INPUT ;
    USE SIGNAL ;
    PORT
      LAYER met2 ;
        RECT 760.010 896.000 760.290 900.000 ;
    END
  END wbs_dat_i[21]
  PIN wbs_dat_i[22]
    DIRECTION INPUT ;
    USE SIGNAL ;
    PORT
      LAYER met3 ;
        RECT 0.000 374.040 4.000 374.640 ;
    END
  END wbs_dat_i[22]
  PIN wbs_dat_i[23]
    DIRECTION INPUT ;
    USE SIGNAL ;
    PORT
      LAYER met3 ;
        RECT 896.000 785.440 900.000 786.040 ;
    END
  END wbs_dat_i[23]
  PIN wbs_dat_i[24]
    DIRECTION INPUT ;
    USE SIGNAL ;
    PORT
      LAYER met3 ;
        RECT 896.000 340.040 900.000 340.640 ;
    END
  END wbs_dat_i[24]
  PIN wbs_dat_i[25]
    DIRECTION INPUT ;
    USE SIGNAL ;
    PORT
      LAYER met3 ;
        RECT 0.000 20.440 4.000 21.040 ;
    END
  END wbs_dat_i[25]
  PIN wbs_dat_i[26]
    DIRECTION INPUT ;
    USE SIGNAL ;
    PORT
      LAYER met2 ;
        RECT 663.410 896.000 663.690 900.000 ;
    END
  END wbs_dat_i[26]
  PIN wbs_dat_i[27]
    DIRECTION INPUT ;
    USE SIGNAL ;
    PORT
      LAYER met2 ;
        RECT 112.790 896.000 113.070 900.000 ;
    END
  END wbs_dat_i[27]
  PIN wbs_dat_i[28]
    DIRECTION INPUT ;
    USE SIGNAL ;
    PORT
      LAYER met2 ;
        RECT 289.890 0.000 290.170 4.000 ;
    END
  END wbs_dat_i[28]
  PIN wbs_dat_i[29]
    DIRECTION INPUT ;
    USE SIGNAL ;
    PORT
      LAYER met3 ;
        RECT 896.000 608.640 900.000 609.240 ;
    END
  END wbs_dat_i[29]
  PIN wbs_dat_i[2]
    DIRECTION INPUT ;
    USE SIGNAL ;
    ANTENNAGATEAREA 0.426000 ;
    PORT
      LAYER met2 ;
        RECT 753.570 0.000 753.850 4.000 ;
    END
  END wbs_dat_i[2]
  PIN wbs_dat_i[30]
    DIRECTION INPUT ;
    USE SIGNAL ;
    PORT
      LAYER met3 ;
        RECT 896.000 302.640 900.000 303.240 ;
    END
  END wbs_dat_i[30]
  PIN wbs_dat_i[31]
    DIRECTION INPUT ;
    USE SIGNAL ;
    PORT
      LAYER met3 ;
        RECT 0.000 350.240 4.000 350.840 ;
    END
  END wbs_dat_i[31]
  PIN wbs_dat_i[3]
    DIRECTION INPUT ;
    USE SIGNAL ;
    ANTENNAGATEAREA 0.426000 ;
    PORT
      LAYER met3 ;
        RECT 896.000 51.040 900.000 51.640 ;
    END
  END wbs_dat_i[3]
  PIN wbs_dat_i[4]
    DIRECTION INPUT ;
    USE SIGNAL ;
    ANTENNAGATEAREA 0.247500 ;
    PORT
      LAYER met2 ;
        RECT 144.990 0.000 145.270 4.000 ;
    END
  END wbs_dat_i[4]
  PIN wbs_dat_i[5]
    DIRECTION INPUT ;
    USE SIGNAL ;
    ANTENNAGATEAREA 0.213000 ;
    PORT
      LAYER met2 ;
        RECT 454.110 0.000 454.390 4.000 ;
    END
  END wbs_dat_i[5]
  PIN wbs_dat_i[6]
    DIRECTION INPUT ;
    USE SIGNAL ;
    ANTENNAGATEAREA 0.213000 ;
    PORT
      LAYER met3 ;
        RECT 896.000 428.440 900.000 429.040 ;
    END
  END wbs_dat_i[6]
  PIN wbs_dat_i[7]
    DIRECTION INPUT ;
    USE SIGNAL ;
    ANTENNAGATEAREA 0.247500 ;
    PORT
      LAYER met2 ;
        RECT 644.090 896.000 644.370 900.000 ;
    END
  END wbs_dat_i[7]
  PIN wbs_dat_i[8]
    DIRECTION INPUT ;
    USE SIGNAL ;
    PORT
      LAYER met3 ;
        RECT 896.000 867.040 900.000 867.640 ;
    END
  END wbs_dat_i[8]
  PIN wbs_dat_i[9]
    DIRECTION INPUT ;
    USE SIGNAL ;
    PORT
      LAYER met3 ;
        RECT 896.000 57.840 900.000 58.440 ;
    END
  END wbs_dat_i[9]
  PIN wbs_dat_o[0]
    DIRECTION OUTPUT TRISTATE ;
    USE SIGNAL ;
    ANTENNADIFFAREA 0.445500 ;
    PORT
      LAYER met2 ;
        RECT 70.930 0.000 71.210 4.000 ;
    END
  END wbs_dat_o[0]
  PIN wbs_dat_o[10]
    DIRECTION OUTPUT TRISTATE ;
    USE SIGNAL ;
    ANTENNADIFFAREA 0.445500 ;
    PORT
      LAYER met3 ;
        RECT 896.000 554.240 900.000 554.840 ;
    END
  END wbs_dat_o[10]
  PIN wbs_dat_o[11]
    DIRECTION OUTPUT TRISTATE ;
    USE SIGNAL ;
    ANTENNADIFFAREA 0.445500 ;
    PORT
      LAYER met2 ;
        RECT 19.410 0.000 19.690 4.000 ;
    END
  END wbs_dat_o[11]
  PIN wbs_dat_o[12]
    DIRECTION OUTPUT TRISTATE ;
    USE SIGNAL ;
    ANTENNADIFFAREA 0.445500 ;
    PORT
      LAYER met3 ;
        RECT 896.000 884.040 900.000 884.640 ;
    END
  END wbs_dat_o[12]
  PIN wbs_dat_o[13]
    DIRECTION OUTPUT TRISTATE ;
    USE SIGNAL ;
    ANTENNADIFFAREA 0.445500 ;
    PORT
      LAYER met2 ;
        RECT 624.770 896.000 625.050 900.000 ;
    END
  END wbs_dat_o[13]
  PIN wbs_dat_o[14]
    DIRECTION OUTPUT TRISTATE ;
    USE SIGNAL ;
    ANTENNADIFFAREA 0.445500 ;
    PORT
      LAYER met3 ;
        RECT 896.000 115.640 900.000 116.240 ;
    END
  END wbs_dat_o[14]
  PIN wbs_dat_o[15]
    DIRECTION OUTPUT TRISTATE ;
    USE SIGNAL ;
    ANTENNADIFFAREA 0.445500 ;
    PORT
      LAYER met2 ;
        RECT 595.790 896.000 596.070 900.000 ;
    END
  END wbs_dat_o[15]
  PIN wbs_dat_o[16]
    DIRECTION OUTPUT TRISTATE ;
    USE SIGNAL ;
    ANTENNADIFFAREA 0.445500 ;
    PORT
      LAYER met2 ;
        RECT 611.890 0.000 612.170 4.000 ;
    END
  END wbs_dat_o[16]
  PIN wbs_dat_o[17]
    DIRECTION OUTPUT TRISTATE ;
    USE SIGNAL ;
    ANTENNADIFFAREA 0.445500 ;
    PORT
      LAYER met3 ;
        RECT 0.000 17.040 4.000 17.640 ;
    END
  END wbs_dat_o[17]
  PIN wbs_dat_o[18]
    DIRECTION OUTPUT TRISTATE ;
    USE SIGNAL ;
    ANTENNADIFFAREA 0.445500 ;
    PORT
      LAYER met2 ;
        RECT 605.450 0.000 605.730 4.000 ;
    END
  END wbs_dat_o[18]
  PIN wbs_dat_o[19]
    DIRECTION OUTPUT TRISTATE ;
    USE SIGNAL ;
    ANTENNADIFFAREA 0.445500 ;
    PORT
      LAYER met2 ;
        RECT 0.090 0.000 0.370 4.000 ;
    END
  END wbs_dat_o[19]
  PIN wbs_dat_o[1]
    DIRECTION OUTPUT TRISTATE ;
    USE SIGNAL ;
    ANTENNADIFFAREA 0.445500 ;
    PORT
      LAYER met2 ;
        RECT 711.710 0.000 711.990 4.000 ;
    END
  END wbs_dat_o[1]
  PIN wbs_dat_o[20]
    DIRECTION OUTPUT TRISTATE ;
    USE SIGNAL ;
    ANTENNADIFFAREA 0.445500 ;
    PORT
      LAYER met3 ;
        RECT 0.000 363.840 4.000 364.440 ;
    END
  END wbs_dat_o[20]
  PIN wbs_dat_o[21]
    DIRECTION OUTPUT TRISTATE ;
    USE SIGNAL ;
    ANTENNADIFFAREA 0.445500 ;
    PORT
      LAYER met3 ;
        RECT 0.000 737.840 4.000 738.440 ;
    END
  END wbs_dat_o[21]
  PIN wbs_dat_o[22]
    DIRECTION OUTPUT TRISTATE ;
    USE SIGNAL ;
    ANTENNADIFFAREA 0.445500 ;
    PORT
      LAYER met2 ;
        RECT 212.610 896.000 212.890 900.000 ;
    END
  END wbs_dat_o[22]
  PIN wbs_dat_o[23]
    DIRECTION OUTPUT TRISTATE ;
    USE SIGNAL ;
    ANTENNADIFFAREA 0.445500 ;
    PORT
      LAYER met3 ;
        RECT 0.000 234.640 4.000 235.240 ;
    END
  END wbs_dat_o[23]
  PIN wbs_dat_o[24]
    DIRECTION OUTPUT TRISTATE ;
    USE SIGNAL ;
    ANTENNADIFFAREA 0.445500 ;
    PORT
      LAYER met2 ;
        RECT 183.630 0.000 183.910 4.000 ;
    END
  END wbs_dat_o[24]
  PIN wbs_dat_o[25]
    DIRECTION OUTPUT TRISTATE ;
    USE SIGNAL ;
    ANTENNADIFFAREA 0.445500 ;
    PORT
      LAYER met2 ;
        RECT 64.490 0.000 64.770 4.000 ;
    END
  END wbs_dat_o[25]
  PIN wbs_dat_o[26]
    DIRECTION OUTPUT TRISTATE ;
    USE SIGNAL ;
    ANTENNADIFFAREA 0.445500 ;
    PORT
      LAYER met2 ;
        RECT 444.450 896.000 444.730 900.000 ;
    END
  END wbs_dat_o[26]
  PIN wbs_dat_o[27]
    DIRECTION OUTPUT TRISTATE ;
    USE SIGNAL ;
    ANTENNADIFFAREA 0.445500 ;
    PORT
      LAYER met2 ;
        RECT 241.590 896.000 241.870 900.000 ;
    END
  END wbs_dat_o[27]
  PIN wbs_dat_o[28]
    DIRECTION OUTPUT TRISTATE ;
    USE SIGNAL ;
    ANTENNADIFFAREA 0.445500 ;
    PORT
      LAYER met2 ;
        RECT 486.310 0.000 486.590 4.000 ;
    END
  END wbs_dat_o[28]
  PIN wbs_dat_o[29]
    DIRECTION OUTPUT TRISTATE ;
    USE SIGNAL ;
    ANTENNADIFFAREA 0.445500 ;
    PORT
      LAYER met2 ;
        RECT 602.230 896.000 602.510 900.000 ;
    END
  END wbs_dat_o[29]
  PIN wbs_dat_o[2]
    DIRECTION OUTPUT TRISTATE ;
    USE SIGNAL ;
    ANTENNADIFFAREA 0.445500 ;
    PORT
      LAYER met3 ;
        RECT 896.000 248.240 900.000 248.840 ;
    END
  END wbs_dat_o[2]
  PIN wbs_dat_o[30]
    DIRECTION OUTPUT TRISTATE ;
    USE SIGNAL ;
    ANTENNADIFFAREA 0.445500 ;
    PORT
      LAYER met3 ;
        RECT 0.000 564.440 4.000 565.040 ;
    END
  END wbs_dat_o[30]
  PIN wbs_dat_o[31]
    DIRECTION OUTPUT TRISTATE ;
    USE SIGNAL ;
    ANTENNADIFFAREA 0.445500 ;
    PORT
      LAYER met3 ;
        RECT 896.000 710.640 900.000 711.240 ;
    END
  END wbs_dat_o[31]
  PIN wbs_dat_o[3]
    DIRECTION OUTPUT TRISTATE ;
    USE SIGNAL ;
    ANTENNADIFFAREA 0.445500 ;
    PORT
      LAYER met2 ;
        RECT 196.510 0.000 196.790 4.000 ;
    END
  END wbs_dat_o[3]
  PIN wbs_dat_o[4]
    DIRECTION OUTPUT TRISTATE ;
    USE SIGNAL ;
    ANTENNADIFFAREA 0.445500 ;
    PORT
      LAYER met2 ;
        RECT 338.190 0.000 338.470 4.000 ;
    END
  END wbs_dat_o[4]
  PIN wbs_dat_o[5]
    DIRECTION OUTPUT TRISTATE ;
    USE SIGNAL ;
    ANTENNADIFFAREA 0.445500 ;
    PORT
      LAYER met3 ;
        RECT 0.000 51.040 4.000 51.640 ;
    END
  END wbs_dat_o[5]
  PIN wbs_dat_o[6]
    DIRECTION OUTPUT TRISTATE ;
    USE SIGNAL ;
    ANTENNADIFFAREA 0.445500 ;
    PORT
      LAYER met3 ;
        RECT 896.000 669.840 900.000 670.440 ;
    END
  END wbs_dat_o[6]
  PIN wbs_dat_o[7]
    DIRECTION OUTPUT TRISTATE ;
    USE SIGNAL ;
    ANTENNADIFFAREA 0.445500 ;
    PORT
      LAYER met2 ;
        RECT 534.610 0.000 534.890 4.000 ;
    END
  END wbs_dat_o[7]
  PIN wbs_dat_o[8]
    DIRECTION OUTPUT TRISTATE ;
    USE SIGNAL ;
    ANTENNADIFFAREA 0.445500 ;
    PORT
      LAYER met2 ;
        RECT 586.130 896.000 586.410 900.000 ;
    END
  END wbs_dat_o[8]
  PIN wbs_dat_o[9]
    DIRECTION OUTPUT TRISTATE ;
    USE SIGNAL ;
    ANTENNADIFFAREA 0.445500 ;
    PORT
      LAYER met2 ;
        RECT 573.250 896.000 573.530 900.000 ;
    END
  END wbs_dat_o[9]
  PIN wbs_sel_i[0]
    DIRECTION INPUT ;
    USE SIGNAL ;
    PORT
      LAYER met3 ;
        RECT 0.000 843.240 4.000 843.840 ;
    END
  END wbs_sel_i[0]
  PIN wbs_sel_i[1]
    DIRECTION INPUT ;
    USE SIGNAL ;
    PORT
      LAYER met2 ;
        RECT 103.130 896.000 103.410 900.000 ;
    END
  END wbs_sel_i[1]
  PIN wbs_sel_i[2]
    DIRECTION INPUT ;
    USE SIGNAL ;
    PORT
      LAYER met2 ;
        RECT 637.650 0.000 637.930 4.000 ;
    END
  END wbs_sel_i[2]
  PIN wbs_sel_i[3]
    DIRECTION INPUT ;
    USE SIGNAL ;
    PORT
      LAYER met3 ;
        RECT 0.000 193.840 4.000 194.440 ;
    END
  END wbs_sel_i[3]
  PIN wbs_stb_i
    DIRECTION INPUT ;
    USE SIGNAL ;
    ANTENNAGATEAREA 0.247500 ;
    PORT
      LAYER met3 ;
        RECT 0.000 761.640 4.000 762.240 ;
    END
  END wbs_stb_i
  PIN wbs_we_i
    DIRECTION INPUT ;
    USE SIGNAL ;
    ANTENNAGATEAREA 0.213000 ;
    PORT
      LAYER met3 ;
        RECT 896.000 435.240 900.000 435.840 ;
    END
  END wbs_we_i
  OBS
      LAYER li1 ;
        RECT 5.520 10.795 894.240 886.805 ;
      LAYER met1 ;
        RECT 0.070 10.640 894.630 886.960 ;
      LAYER met2 ;
        RECT 0.650 895.720 3.030 898.125 ;
        RECT 3.870 895.720 9.470 898.125 ;
        RECT 10.310 895.720 15.910 898.125 ;
        RECT 16.750 895.720 22.350 898.125 ;
        RECT 23.190 895.720 25.570 898.125 ;
        RECT 26.410 895.720 32.010 898.125 ;
        RECT 32.850 895.720 38.450 898.125 ;
        RECT 39.290 895.720 41.670 898.125 ;
        RECT 42.510 895.720 48.110 898.125 ;
        RECT 48.950 895.720 54.550 898.125 ;
        RECT 55.390 895.720 57.770 898.125 ;
        RECT 58.610 895.720 64.210 898.125 ;
        RECT 65.050 895.720 70.650 898.125 ;
        RECT 71.490 895.720 77.090 898.125 ;
        RECT 77.930 895.720 80.310 898.125 ;
        RECT 81.150 895.720 86.750 898.125 ;
        RECT 87.590 895.720 93.190 898.125 ;
        RECT 94.030 895.720 96.410 898.125 ;
        RECT 97.250 895.720 102.850 898.125 ;
        RECT 103.690 895.720 109.290 898.125 ;
        RECT 110.130 895.720 112.510 898.125 ;
        RECT 113.350 895.720 118.950 898.125 ;
        RECT 119.790 895.720 125.390 898.125 ;
        RECT 126.230 895.720 131.830 898.125 ;
        RECT 132.670 895.720 135.050 898.125 ;
        RECT 135.890 895.720 141.490 898.125 ;
        RECT 142.330 895.720 147.930 898.125 ;
        RECT 148.770 895.720 151.150 898.125 ;
        RECT 151.990 895.720 157.590 898.125 ;
        RECT 158.430 895.720 164.030 898.125 ;
        RECT 164.870 895.720 167.250 898.125 ;
        RECT 168.090 895.720 173.690 898.125 ;
        RECT 174.530 895.720 180.130 898.125 ;
        RECT 180.970 895.720 186.570 898.125 ;
        RECT 187.410 895.720 189.790 898.125 ;
        RECT 190.630 895.720 196.230 898.125 ;
        RECT 197.070 895.720 202.670 898.125 ;
        RECT 203.510 895.720 205.890 898.125 ;
        RECT 206.730 895.720 212.330 898.125 ;
        RECT 213.170 895.720 218.770 898.125 ;
        RECT 219.610 895.720 221.990 898.125 ;
        RECT 222.830 895.720 228.430 898.125 ;
        RECT 229.270 895.720 234.870 898.125 ;
        RECT 235.710 895.720 241.310 898.125 ;
        RECT 242.150 895.720 244.530 898.125 ;
        RECT 245.370 895.720 250.970 898.125 ;
        RECT 251.810 895.720 257.410 898.125 ;
        RECT 258.250 895.720 260.630 898.125 ;
        RECT 261.470 895.720 267.070 898.125 ;
        RECT 267.910 895.720 273.510 898.125 ;
        RECT 274.350 895.720 276.730 898.125 ;
        RECT 277.570 895.720 283.170 898.125 ;
        RECT 284.010 895.720 289.610 898.125 ;
        RECT 290.450 895.720 296.050 898.125 ;
        RECT 296.890 895.720 299.270 898.125 ;
        RECT 300.110 895.720 305.710 898.125 ;
        RECT 306.550 895.720 312.150 898.125 ;
        RECT 312.990 895.720 315.370 898.125 ;
        RECT 316.210 895.720 321.810 898.125 ;
        RECT 322.650 895.720 328.250 898.125 ;
        RECT 329.090 895.720 334.690 898.125 ;
        RECT 335.530 895.720 337.910 898.125 ;
        RECT 338.750 895.720 344.350 898.125 ;
        RECT 345.190 895.720 350.790 898.125 ;
        RECT 351.630 895.720 354.010 898.125 ;
        RECT 354.850 895.720 360.450 898.125 ;
        RECT 361.290 895.720 366.890 898.125 ;
        RECT 367.730 895.720 370.110 898.125 ;
        RECT 370.950 895.720 376.550 898.125 ;
        RECT 377.390 895.720 382.990 898.125 ;
        RECT 383.830 895.720 389.430 898.125 ;
        RECT 390.270 895.720 392.650 898.125 ;
        RECT 393.490 895.720 399.090 898.125 ;
        RECT 399.930 895.720 405.530 898.125 ;
        RECT 406.370 895.720 408.750 898.125 ;
        RECT 409.590 895.720 415.190 898.125 ;
        RECT 416.030 895.720 421.630 898.125 ;
        RECT 422.470 895.720 424.850 898.125 ;
        RECT 425.690 895.720 431.290 898.125 ;
        RECT 432.130 895.720 437.730 898.125 ;
        RECT 438.570 895.720 444.170 898.125 ;
        RECT 445.010 895.720 447.390 898.125 ;
        RECT 448.230 895.720 453.830 898.125 ;
        RECT 454.670 895.720 460.270 898.125 ;
        RECT 461.110 895.720 463.490 898.125 ;
        RECT 464.330 895.720 469.930 898.125 ;
        RECT 470.770 895.720 476.370 898.125 ;
        RECT 477.210 895.720 479.590 898.125 ;
        RECT 480.430 895.720 486.030 898.125 ;
        RECT 486.870 895.720 492.470 898.125 ;
        RECT 493.310 895.720 498.910 898.125 ;
        RECT 499.750 895.720 502.130 898.125 ;
        RECT 502.970 895.720 508.570 898.125 ;
        RECT 509.410 895.720 515.010 898.125 ;
        RECT 515.850 895.720 518.230 898.125 ;
        RECT 519.070 895.720 524.670 898.125 ;
        RECT 525.510 895.720 531.110 898.125 ;
        RECT 531.950 895.720 534.330 898.125 ;
        RECT 535.170 895.720 540.770 898.125 ;
        RECT 541.610 895.720 547.210 898.125 ;
        RECT 548.050 895.720 553.650 898.125 ;
        RECT 554.490 895.720 556.870 898.125 ;
        RECT 557.710 895.720 563.310 898.125 ;
        RECT 564.150 895.720 569.750 898.125 ;
        RECT 570.590 895.720 572.970 898.125 ;
        RECT 573.810 895.720 579.410 898.125 ;
        RECT 580.250 895.720 585.850 898.125 ;
        RECT 586.690 895.720 589.070 898.125 ;
        RECT 589.910 895.720 595.510 898.125 ;
        RECT 596.350 895.720 601.950 898.125 ;
        RECT 602.790 895.720 608.390 898.125 ;
        RECT 609.230 895.720 611.610 898.125 ;
        RECT 612.450 895.720 618.050 898.125 ;
        RECT 618.890 895.720 624.490 898.125 ;
        RECT 625.330 895.720 627.710 898.125 ;
        RECT 628.550 895.720 634.150 898.125 ;
        RECT 634.990 895.720 640.590 898.125 ;
        RECT 641.430 895.720 643.810 898.125 ;
        RECT 644.650 895.720 650.250 898.125 ;
        RECT 651.090 895.720 656.690 898.125 ;
        RECT 657.530 895.720 663.130 898.125 ;
        RECT 663.970 895.720 666.350 898.125 ;
        RECT 667.190 895.720 672.790 898.125 ;
        RECT 673.630 895.720 679.230 898.125 ;
        RECT 680.070 895.720 682.450 898.125 ;
        RECT 683.290 895.720 688.890 898.125 ;
        RECT 689.730 895.720 695.330 898.125 ;
        RECT 696.170 895.720 698.550 898.125 ;
        RECT 699.390 895.720 704.990 898.125 ;
        RECT 705.830 895.720 711.430 898.125 ;
        RECT 712.270 895.720 717.870 898.125 ;
        RECT 718.710 895.720 721.090 898.125 ;
        RECT 721.930 895.720 727.530 898.125 ;
        RECT 728.370 895.720 733.970 898.125 ;
        RECT 734.810 895.720 737.190 898.125 ;
        RECT 738.030 895.720 743.630 898.125 ;
        RECT 744.470 895.720 750.070 898.125 ;
        RECT 750.910 895.720 753.290 898.125 ;
        RECT 754.130 895.720 759.730 898.125 ;
        RECT 760.570 895.720 766.170 898.125 ;
        RECT 767.010 895.720 772.610 898.125 ;
        RECT 773.450 895.720 775.830 898.125 ;
        RECT 776.670 895.720 782.270 898.125 ;
        RECT 783.110 895.720 788.710 898.125 ;
        RECT 789.550 895.720 791.930 898.125 ;
        RECT 792.770 895.720 798.370 898.125 ;
        RECT 799.210 895.720 804.810 898.125 ;
        RECT 805.650 895.720 808.030 898.125 ;
        RECT 808.870 895.720 814.470 898.125 ;
        RECT 815.310 895.720 820.910 898.125 ;
        RECT 821.750 895.720 827.350 898.125 ;
        RECT 828.190 895.720 830.570 898.125 ;
        RECT 831.410 895.720 837.010 898.125 ;
        RECT 837.850 895.720 843.450 898.125 ;
        RECT 844.290 895.720 846.670 898.125 ;
        RECT 847.510 895.720 853.110 898.125 ;
        RECT 853.950 895.720 859.550 898.125 ;
        RECT 860.390 895.720 862.770 898.125 ;
        RECT 863.610 895.720 869.210 898.125 ;
        RECT 870.050 895.720 875.650 898.125 ;
        RECT 876.490 895.720 882.090 898.125 ;
        RECT 882.930 895.720 885.310 898.125 ;
        RECT 886.150 895.720 891.750 898.125 ;
        RECT 892.590 895.720 895.460 898.125 ;
        RECT 0.100 4.280 895.460 895.720 ;
        RECT 0.650 4.000 3.030 4.280 ;
        RECT 3.870 4.000 9.470 4.280 ;
        RECT 10.310 4.000 15.910 4.280 ;
        RECT 16.750 4.000 19.130 4.280 ;
        RECT 19.970 4.000 25.570 4.280 ;
        RECT 26.410 4.000 32.010 4.280 ;
        RECT 32.850 4.000 35.230 4.280 ;
        RECT 36.070 4.000 41.670 4.280 ;
        RECT 42.510 4.000 48.110 4.280 ;
        RECT 48.950 4.000 54.550 4.280 ;
        RECT 55.390 4.000 57.770 4.280 ;
        RECT 58.610 4.000 64.210 4.280 ;
        RECT 65.050 4.000 70.650 4.280 ;
        RECT 71.490 4.000 73.870 4.280 ;
        RECT 74.710 4.000 80.310 4.280 ;
        RECT 81.150 4.000 86.750 4.280 ;
        RECT 87.590 4.000 89.970 4.280 ;
        RECT 90.810 4.000 96.410 4.280 ;
        RECT 97.250 4.000 102.850 4.280 ;
        RECT 103.690 4.000 109.290 4.280 ;
        RECT 110.130 4.000 112.510 4.280 ;
        RECT 113.350 4.000 118.950 4.280 ;
        RECT 119.790 4.000 125.390 4.280 ;
        RECT 126.230 4.000 128.610 4.280 ;
        RECT 129.450 4.000 135.050 4.280 ;
        RECT 135.890 4.000 141.490 4.280 ;
        RECT 142.330 4.000 144.710 4.280 ;
        RECT 145.550 4.000 151.150 4.280 ;
        RECT 151.990 4.000 157.590 4.280 ;
        RECT 158.430 4.000 164.030 4.280 ;
        RECT 164.870 4.000 167.250 4.280 ;
        RECT 168.090 4.000 173.690 4.280 ;
        RECT 174.530 4.000 180.130 4.280 ;
        RECT 180.970 4.000 183.350 4.280 ;
        RECT 184.190 4.000 189.790 4.280 ;
        RECT 190.630 4.000 196.230 4.280 ;
        RECT 197.070 4.000 199.450 4.280 ;
        RECT 200.290 4.000 205.890 4.280 ;
        RECT 206.730 4.000 212.330 4.280 ;
        RECT 213.170 4.000 218.770 4.280 ;
        RECT 219.610 4.000 221.990 4.280 ;
        RECT 222.830 4.000 228.430 4.280 ;
        RECT 229.270 4.000 234.870 4.280 ;
        RECT 235.710 4.000 238.090 4.280 ;
        RECT 238.930 4.000 244.530 4.280 ;
        RECT 245.370 4.000 250.970 4.280 ;
        RECT 251.810 4.000 254.190 4.280 ;
        RECT 255.030 4.000 260.630 4.280 ;
        RECT 261.470 4.000 267.070 4.280 ;
        RECT 267.910 4.000 273.510 4.280 ;
        RECT 274.350 4.000 276.730 4.280 ;
        RECT 277.570 4.000 283.170 4.280 ;
        RECT 284.010 4.000 289.610 4.280 ;
        RECT 290.450 4.000 292.830 4.280 ;
        RECT 293.670 4.000 299.270 4.280 ;
        RECT 300.110 4.000 305.710 4.280 ;
        RECT 306.550 4.000 308.930 4.280 ;
        RECT 309.770 4.000 315.370 4.280 ;
        RECT 316.210 4.000 321.810 4.280 ;
        RECT 322.650 4.000 328.250 4.280 ;
        RECT 329.090 4.000 331.470 4.280 ;
        RECT 332.310 4.000 337.910 4.280 ;
        RECT 338.750 4.000 344.350 4.280 ;
        RECT 345.190 4.000 347.570 4.280 ;
        RECT 348.410 4.000 354.010 4.280 ;
        RECT 354.850 4.000 360.450 4.280 ;
        RECT 361.290 4.000 363.670 4.280 ;
        RECT 364.510 4.000 370.110 4.280 ;
        RECT 370.950 4.000 376.550 4.280 ;
        RECT 377.390 4.000 382.990 4.280 ;
        RECT 383.830 4.000 386.210 4.280 ;
        RECT 387.050 4.000 392.650 4.280 ;
        RECT 393.490 4.000 399.090 4.280 ;
        RECT 399.930 4.000 402.310 4.280 ;
        RECT 403.150 4.000 408.750 4.280 ;
        RECT 409.590 4.000 415.190 4.280 ;
        RECT 416.030 4.000 418.410 4.280 ;
        RECT 419.250 4.000 424.850 4.280 ;
        RECT 425.690 4.000 431.290 4.280 ;
        RECT 432.130 4.000 437.730 4.280 ;
        RECT 438.570 4.000 440.950 4.280 ;
        RECT 441.790 4.000 447.390 4.280 ;
        RECT 448.230 4.000 453.830 4.280 ;
        RECT 454.670 4.000 457.050 4.280 ;
        RECT 457.890 4.000 463.490 4.280 ;
        RECT 464.330 4.000 469.930 4.280 ;
        RECT 470.770 4.000 473.150 4.280 ;
        RECT 473.990 4.000 479.590 4.280 ;
        RECT 480.430 4.000 486.030 4.280 ;
        RECT 486.870 4.000 492.470 4.280 ;
        RECT 493.310 4.000 495.690 4.280 ;
        RECT 496.530 4.000 502.130 4.280 ;
        RECT 502.970 4.000 508.570 4.280 ;
        RECT 509.410 4.000 511.790 4.280 ;
        RECT 512.630 4.000 518.230 4.280 ;
        RECT 519.070 4.000 524.670 4.280 ;
        RECT 525.510 4.000 527.890 4.280 ;
        RECT 528.730 4.000 534.330 4.280 ;
        RECT 535.170 4.000 540.770 4.280 ;
        RECT 541.610 4.000 547.210 4.280 ;
        RECT 548.050 4.000 550.430 4.280 ;
        RECT 551.270 4.000 556.870 4.280 ;
        RECT 557.710 4.000 563.310 4.280 ;
        RECT 564.150 4.000 566.530 4.280 ;
        RECT 567.370 4.000 572.970 4.280 ;
        RECT 573.810 4.000 579.410 4.280 ;
        RECT 580.250 4.000 582.630 4.280 ;
        RECT 583.470 4.000 589.070 4.280 ;
        RECT 589.910 4.000 595.510 4.280 ;
        RECT 596.350 4.000 601.950 4.280 ;
        RECT 602.790 4.000 605.170 4.280 ;
        RECT 606.010 4.000 611.610 4.280 ;
        RECT 612.450 4.000 618.050 4.280 ;
        RECT 618.890 4.000 621.270 4.280 ;
        RECT 622.110 4.000 627.710 4.280 ;
        RECT 628.550 4.000 634.150 4.280 ;
        RECT 634.990 4.000 637.370 4.280 ;
        RECT 638.210 4.000 643.810 4.280 ;
        RECT 644.650 4.000 650.250 4.280 ;
        RECT 651.090 4.000 656.690 4.280 ;
        RECT 657.530 4.000 659.910 4.280 ;
        RECT 660.750 4.000 666.350 4.280 ;
        RECT 667.190 4.000 672.790 4.280 ;
        RECT 673.630 4.000 676.010 4.280 ;
        RECT 676.850 4.000 682.450 4.280 ;
        RECT 683.290 4.000 688.890 4.280 ;
        RECT 689.730 4.000 692.110 4.280 ;
        RECT 692.950 4.000 698.550 4.280 ;
        RECT 699.390 4.000 704.990 4.280 ;
        RECT 705.830 4.000 711.430 4.280 ;
        RECT 712.270 4.000 714.650 4.280 ;
        RECT 715.490 4.000 721.090 4.280 ;
        RECT 721.930 4.000 727.530 4.280 ;
        RECT 728.370 4.000 730.750 4.280 ;
        RECT 731.590 4.000 737.190 4.280 ;
        RECT 738.030 4.000 743.630 4.280 ;
        RECT 744.470 4.000 746.850 4.280 ;
        RECT 747.690 4.000 753.290 4.280 ;
        RECT 754.130 4.000 759.730 4.280 ;
        RECT 760.570 4.000 766.170 4.280 ;
        RECT 767.010 4.000 769.390 4.280 ;
        RECT 770.230 4.000 775.830 4.280 ;
        RECT 776.670 4.000 782.270 4.280 ;
        RECT 783.110 4.000 785.490 4.280 ;
        RECT 786.330 4.000 791.930 4.280 ;
        RECT 792.770 4.000 798.370 4.280 ;
        RECT 799.210 4.000 801.590 4.280 ;
        RECT 802.430 4.000 808.030 4.280 ;
        RECT 808.870 4.000 814.470 4.280 ;
        RECT 815.310 4.000 820.910 4.280 ;
        RECT 821.750 4.000 824.130 4.280 ;
        RECT 824.970 4.000 830.570 4.280 ;
        RECT 831.410 4.000 837.010 4.280 ;
        RECT 837.850 4.000 840.230 4.280 ;
        RECT 841.070 4.000 846.670 4.280 ;
        RECT 847.510 4.000 853.110 4.280 ;
        RECT 853.950 4.000 856.330 4.280 ;
        RECT 857.170 4.000 862.770 4.280 ;
        RECT 863.610 4.000 869.210 4.280 ;
        RECT 870.050 4.000 875.650 4.280 ;
        RECT 876.490 4.000 878.870 4.280 ;
        RECT 879.710 4.000 885.310 4.280 ;
        RECT 886.150 4.000 891.750 4.280 ;
        RECT 892.590 4.000 894.970 4.280 ;
      LAYER met3 ;
        RECT 3.990 897.240 895.600 898.105 ;
        RECT 3.990 895.240 896.000 897.240 ;
        RECT 4.400 893.840 896.000 895.240 ;
        RECT 3.990 891.840 896.000 893.840 ;
        RECT 3.990 890.440 895.600 891.840 ;
        RECT 3.990 888.440 896.000 890.440 ;
        RECT 4.400 887.040 896.000 888.440 ;
        RECT 3.990 885.040 896.000 887.040 ;
        RECT 4.400 883.640 895.600 885.040 ;
        RECT 3.990 881.640 896.000 883.640 ;
        RECT 3.990 880.240 895.600 881.640 ;
        RECT 3.990 878.240 896.000 880.240 ;
        RECT 4.400 876.840 896.000 878.240 ;
        RECT 3.990 874.840 896.000 876.840 ;
        RECT 3.990 873.440 895.600 874.840 ;
        RECT 3.990 871.440 896.000 873.440 ;
        RECT 4.400 870.040 896.000 871.440 ;
        RECT 3.990 868.040 896.000 870.040 ;
        RECT 4.400 866.640 895.600 868.040 ;
        RECT 3.990 861.240 896.000 866.640 ;
        RECT 4.400 859.840 895.600 861.240 ;
        RECT 3.990 857.840 896.000 859.840 ;
        RECT 3.990 856.440 895.600 857.840 ;
        RECT 3.990 854.440 896.000 856.440 ;
        RECT 4.400 853.040 896.000 854.440 ;
        RECT 3.990 851.040 896.000 853.040 ;
        RECT 3.990 849.640 895.600 851.040 ;
        RECT 3.990 847.640 896.000 849.640 ;
        RECT 4.400 846.240 896.000 847.640 ;
        RECT 3.990 844.240 896.000 846.240 ;
        RECT 4.400 842.840 895.600 844.240 ;
        RECT 3.990 840.840 896.000 842.840 ;
        RECT 3.990 839.440 895.600 840.840 ;
        RECT 3.990 837.440 896.000 839.440 ;
        RECT 4.400 836.040 896.000 837.440 ;
        RECT 3.990 834.040 896.000 836.040 ;
        RECT 3.990 832.640 895.600 834.040 ;
        RECT 3.990 830.640 896.000 832.640 ;
        RECT 4.400 829.240 896.000 830.640 ;
        RECT 3.990 827.240 896.000 829.240 ;
        RECT 4.400 825.840 895.600 827.240 ;
        RECT 3.990 823.840 896.000 825.840 ;
        RECT 3.990 822.440 895.600 823.840 ;
        RECT 3.990 820.440 896.000 822.440 ;
        RECT 4.400 819.040 896.000 820.440 ;
        RECT 3.990 817.040 896.000 819.040 ;
        RECT 3.990 815.640 895.600 817.040 ;
        RECT 3.990 813.640 896.000 815.640 ;
        RECT 4.400 812.240 896.000 813.640 ;
        RECT 3.990 810.240 896.000 812.240 ;
        RECT 4.400 808.840 895.600 810.240 ;
        RECT 3.990 803.440 896.000 808.840 ;
        RECT 4.400 802.040 895.600 803.440 ;
        RECT 3.990 800.040 896.000 802.040 ;
        RECT 3.990 798.640 895.600 800.040 ;
        RECT 3.990 796.640 896.000 798.640 ;
        RECT 4.400 795.240 896.000 796.640 ;
        RECT 3.990 793.240 896.000 795.240 ;
        RECT 3.990 791.840 895.600 793.240 ;
        RECT 3.990 789.840 896.000 791.840 ;
        RECT 4.400 788.440 896.000 789.840 ;
        RECT 3.990 786.440 896.000 788.440 ;
        RECT 4.400 785.040 895.600 786.440 ;
        RECT 3.990 783.040 896.000 785.040 ;
        RECT 3.990 781.640 895.600 783.040 ;
        RECT 3.990 779.640 896.000 781.640 ;
        RECT 4.400 778.240 896.000 779.640 ;
        RECT 3.990 776.240 896.000 778.240 ;
        RECT 3.990 774.840 895.600 776.240 ;
        RECT 3.990 772.840 896.000 774.840 ;
        RECT 4.400 771.440 896.000 772.840 ;
        RECT 3.990 769.440 896.000 771.440 ;
        RECT 4.400 768.040 895.600 769.440 ;
        RECT 3.990 766.040 896.000 768.040 ;
        RECT 3.990 764.640 895.600 766.040 ;
        RECT 3.990 762.640 896.000 764.640 ;
        RECT 4.400 761.240 896.000 762.640 ;
        RECT 3.990 759.240 896.000 761.240 ;
        RECT 3.990 757.840 895.600 759.240 ;
        RECT 3.990 755.840 896.000 757.840 ;
        RECT 4.400 754.440 896.000 755.840 ;
        RECT 3.990 752.440 896.000 754.440 ;
        RECT 4.400 751.040 895.600 752.440 ;
        RECT 3.990 745.640 896.000 751.040 ;
        RECT 4.400 744.240 895.600 745.640 ;
        RECT 3.990 742.240 896.000 744.240 ;
        RECT 3.990 740.840 895.600 742.240 ;
        RECT 3.990 738.840 896.000 740.840 ;
        RECT 4.400 737.440 896.000 738.840 ;
        RECT 3.990 735.440 896.000 737.440 ;
        RECT 3.990 734.040 895.600 735.440 ;
        RECT 3.990 732.040 896.000 734.040 ;
        RECT 4.400 730.640 896.000 732.040 ;
        RECT 3.990 728.640 896.000 730.640 ;
        RECT 4.400 727.240 895.600 728.640 ;
        RECT 3.990 725.240 896.000 727.240 ;
        RECT 3.990 723.840 895.600 725.240 ;
        RECT 3.990 721.840 896.000 723.840 ;
        RECT 4.400 720.440 896.000 721.840 ;
        RECT 3.990 718.440 896.000 720.440 ;
        RECT 3.990 717.040 895.600 718.440 ;
        RECT 3.990 715.040 896.000 717.040 ;
        RECT 4.400 713.640 896.000 715.040 ;
        RECT 3.990 711.640 896.000 713.640 ;
        RECT 4.400 710.240 895.600 711.640 ;
        RECT 3.990 708.240 896.000 710.240 ;
        RECT 3.990 706.840 895.600 708.240 ;
        RECT 3.990 704.840 896.000 706.840 ;
        RECT 4.400 703.440 896.000 704.840 ;
        RECT 3.990 701.440 896.000 703.440 ;
        RECT 3.990 700.040 895.600 701.440 ;
        RECT 3.990 698.040 896.000 700.040 ;
        RECT 4.400 696.640 896.000 698.040 ;
        RECT 3.990 694.640 896.000 696.640 ;
        RECT 4.400 693.240 895.600 694.640 ;
        RECT 3.990 687.840 896.000 693.240 ;
        RECT 4.400 686.440 895.600 687.840 ;
        RECT 3.990 684.440 896.000 686.440 ;
        RECT 3.990 683.040 895.600 684.440 ;
        RECT 3.990 681.040 896.000 683.040 ;
        RECT 4.400 679.640 896.000 681.040 ;
        RECT 3.990 677.640 896.000 679.640 ;
        RECT 3.990 676.240 895.600 677.640 ;
        RECT 3.990 674.240 896.000 676.240 ;
        RECT 4.400 672.840 896.000 674.240 ;
        RECT 3.990 670.840 896.000 672.840 ;
        RECT 4.400 669.440 895.600 670.840 ;
        RECT 3.990 667.440 896.000 669.440 ;
        RECT 3.990 666.040 895.600 667.440 ;
        RECT 3.990 664.040 896.000 666.040 ;
        RECT 4.400 662.640 896.000 664.040 ;
        RECT 3.990 660.640 896.000 662.640 ;
        RECT 3.990 659.240 895.600 660.640 ;
        RECT 3.990 657.240 896.000 659.240 ;
        RECT 4.400 655.840 896.000 657.240 ;
        RECT 3.990 653.840 896.000 655.840 ;
        RECT 4.400 652.440 895.600 653.840 ;
        RECT 3.990 650.440 896.000 652.440 ;
        RECT 3.990 649.040 895.600 650.440 ;
        RECT 3.990 647.040 896.000 649.040 ;
        RECT 4.400 645.640 896.000 647.040 ;
        RECT 3.990 643.640 896.000 645.640 ;
        RECT 3.990 642.240 895.600 643.640 ;
        RECT 3.990 640.240 896.000 642.240 ;
        RECT 4.400 638.840 896.000 640.240 ;
        RECT 3.990 636.840 896.000 638.840 ;
        RECT 4.400 635.440 895.600 636.840 ;
        RECT 3.990 630.040 896.000 635.440 ;
        RECT 4.400 628.640 895.600 630.040 ;
        RECT 3.990 626.640 896.000 628.640 ;
        RECT 3.990 625.240 895.600 626.640 ;
        RECT 3.990 623.240 896.000 625.240 ;
        RECT 4.400 621.840 896.000 623.240 ;
        RECT 3.990 619.840 896.000 621.840 ;
        RECT 3.990 618.440 895.600 619.840 ;
        RECT 3.990 616.440 896.000 618.440 ;
        RECT 4.400 615.040 896.000 616.440 ;
        RECT 3.990 613.040 896.000 615.040 ;
        RECT 4.400 611.640 895.600 613.040 ;
        RECT 3.990 609.640 896.000 611.640 ;
        RECT 3.990 608.240 895.600 609.640 ;
        RECT 3.990 606.240 896.000 608.240 ;
        RECT 4.400 604.840 896.000 606.240 ;
        RECT 3.990 602.840 896.000 604.840 ;
        RECT 3.990 601.440 895.600 602.840 ;
        RECT 3.990 599.440 896.000 601.440 ;
        RECT 4.400 598.040 896.000 599.440 ;
        RECT 3.990 596.040 896.000 598.040 ;
        RECT 4.400 594.640 895.600 596.040 ;
        RECT 3.990 592.640 896.000 594.640 ;
        RECT 3.990 591.240 895.600 592.640 ;
        RECT 3.990 589.240 896.000 591.240 ;
        RECT 4.400 587.840 896.000 589.240 ;
        RECT 3.990 585.840 896.000 587.840 ;
        RECT 3.990 584.440 895.600 585.840 ;
        RECT 3.990 582.440 896.000 584.440 ;
        RECT 4.400 581.040 896.000 582.440 ;
        RECT 3.990 579.040 896.000 581.040 ;
        RECT 4.400 577.640 895.600 579.040 ;
        RECT 3.990 572.240 896.000 577.640 ;
        RECT 4.400 570.840 895.600 572.240 ;
        RECT 3.990 568.840 896.000 570.840 ;
        RECT 3.990 567.440 895.600 568.840 ;
        RECT 3.990 565.440 896.000 567.440 ;
        RECT 4.400 564.040 896.000 565.440 ;
        RECT 3.990 562.040 896.000 564.040 ;
        RECT 3.990 560.640 895.600 562.040 ;
        RECT 3.990 558.640 896.000 560.640 ;
        RECT 4.400 557.240 896.000 558.640 ;
        RECT 3.990 555.240 896.000 557.240 ;
        RECT 4.400 553.840 895.600 555.240 ;
        RECT 3.990 551.840 896.000 553.840 ;
        RECT 3.990 550.440 895.600 551.840 ;
        RECT 3.990 548.440 896.000 550.440 ;
        RECT 4.400 547.040 896.000 548.440 ;
        RECT 3.990 545.040 896.000 547.040 ;
        RECT 3.990 543.640 895.600 545.040 ;
        RECT 3.990 541.640 896.000 543.640 ;
        RECT 4.400 540.240 896.000 541.640 ;
        RECT 3.990 538.240 896.000 540.240 ;
        RECT 4.400 536.840 895.600 538.240 ;
        RECT 3.990 534.840 896.000 536.840 ;
        RECT 3.990 533.440 895.600 534.840 ;
        RECT 3.990 531.440 896.000 533.440 ;
        RECT 4.400 530.040 896.000 531.440 ;
        RECT 3.990 528.040 896.000 530.040 ;
        RECT 3.990 526.640 895.600 528.040 ;
        RECT 3.990 524.640 896.000 526.640 ;
        RECT 4.400 523.240 896.000 524.640 ;
        RECT 3.990 521.240 896.000 523.240 ;
        RECT 4.400 519.840 895.600 521.240 ;
        RECT 3.990 514.440 896.000 519.840 ;
        RECT 4.400 513.040 895.600 514.440 ;
        RECT 3.990 511.040 896.000 513.040 ;
        RECT 3.990 509.640 895.600 511.040 ;
        RECT 3.990 507.640 896.000 509.640 ;
        RECT 4.400 506.240 896.000 507.640 ;
        RECT 3.990 504.240 896.000 506.240 ;
        RECT 3.990 502.840 895.600 504.240 ;
        RECT 3.990 500.840 896.000 502.840 ;
        RECT 4.400 499.440 896.000 500.840 ;
        RECT 3.990 497.440 896.000 499.440 ;
        RECT 4.400 496.040 895.600 497.440 ;
        RECT 3.990 494.040 896.000 496.040 ;
        RECT 3.990 492.640 895.600 494.040 ;
        RECT 3.990 490.640 896.000 492.640 ;
        RECT 4.400 489.240 896.000 490.640 ;
        RECT 3.990 487.240 896.000 489.240 ;
        RECT 3.990 485.840 895.600 487.240 ;
        RECT 3.990 483.840 896.000 485.840 ;
        RECT 4.400 482.440 896.000 483.840 ;
        RECT 3.990 480.440 896.000 482.440 ;
        RECT 4.400 479.040 895.600 480.440 ;
        RECT 3.990 477.040 896.000 479.040 ;
        RECT 3.990 475.640 895.600 477.040 ;
        RECT 3.990 473.640 896.000 475.640 ;
        RECT 4.400 472.240 896.000 473.640 ;
        RECT 3.990 470.240 896.000 472.240 ;
        RECT 3.990 468.840 895.600 470.240 ;
        RECT 3.990 466.840 896.000 468.840 ;
        RECT 4.400 465.440 896.000 466.840 ;
        RECT 3.990 463.440 896.000 465.440 ;
        RECT 4.400 462.040 895.600 463.440 ;
        RECT 3.990 456.640 896.000 462.040 ;
        RECT 4.400 455.240 895.600 456.640 ;
        RECT 3.990 453.240 896.000 455.240 ;
        RECT 3.990 451.840 895.600 453.240 ;
        RECT 3.990 449.840 896.000 451.840 ;
        RECT 4.400 448.440 896.000 449.840 ;
        RECT 3.990 446.440 896.000 448.440 ;
        RECT 3.990 445.040 895.600 446.440 ;
        RECT 3.990 443.040 896.000 445.040 ;
        RECT 4.400 441.640 896.000 443.040 ;
        RECT 3.990 439.640 896.000 441.640 ;
        RECT 4.400 438.240 895.600 439.640 ;
        RECT 3.990 436.240 896.000 438.240 ;
        RECT 3.990 434.840 895.600 436.240 ;
        RECT 3.990 432.840 896.000 434.840 ;
        RECT 4.400 431.440 896.000 432.840 ;
        RECT 3.990 429.440 896.000 431.440 ;
        RECT 3.990 428.040 895.600 429.440 ;
        RECT 3.990 426.040 896.000 428.040 ;
        RECT 4.400 424.640 896.000 426.040 ;
        RECT 3.990 422.640 896.000 424.640 ;
        RECT 4.400 421.240 895.600 422.640 ;
        RECT 3.990 419.240 896.000 421.240 ;
        RECT 3.990 417.840 895.600 419.240 ;
        RECT 3.990 415.840 896.000 417.840 ;
        RECT 4.400 414.440 896.000 415.840 ;
        RECT 3.990 412.440 896.000 414.440 ;
        RECT 3.990 411.040 895.600 412.440 ;
        RECT 3.990 409.040 896.000 411.040 ;
        RECT 4.400 407.640 896.000 409.040 ;
        RECT 3.990 405.640 896.000 407.640 ;
        RECT 4.400 404.240 895.600 405.640 ;
        RECT 3.990 398.840 896.000 404.240 ;
        RECT 4.400 397.440 895.600 398.840 ;
        RECT 3.990 395.440 896.000 397.440 ;
        RECT 3.990 394.040 895.600 395.440 ;
        RECT 3.990 392.040 896.000 394.040 ;
        RECT 4.400 390.640 896.000 392.040 ;
        RECT 3.990 388.640 896.000 390.640 ;
        RECT 3.990 387.240 895.600 388.640 ;
        RECT 3.990 385.240 896.000 387.240 ;
        RECT 4.400 383.840 896.000 385.240 ;
        RECT 3.990 381.840 896.000 383.840 ;
        RECT 4.400 380.440 895.600 381.840 ;
        RECT 3.990 378.440 896.000 380.440 ;
        RECT 3.990 377.040 895.600 378.440 ;
        RECT 3.990 375.040 896.000 377.040 ;
        RECT 4.400 373.640 896.000 375.040 ;
        RECT 3.990 371.640 896.000 373.640 ;
        RECT 3.990 370.240 895.600 371.640 ;
        RECT 3.990 368.240 896.000 370.240 ;
        RECT 4.400 366.840 896.000 368.240 ;
        RECT 3.990 364.840 896.000 366.840 ;
        RECT 4.400 363.440 895.600 364.840 ;
        RECT 3.990 361.440 896.000 363.440 ;
        RECT 3.990 360.040 895.600 361.440 ;
        RECT 3.990 358.040 896.000 360.040 ;
        RECT 4.400 356.640 896.000 358.040 ;
        RECT 3.990 354.640 896.000 356.640 ;
        RECT 3.990 353.240 895.600 354.640 ;
        RECT 3.990 351.240 896.000 353.240 ;
        RECT 4.400 349.840 896.000 351.240 ;
        RECT 3.990 347.840 896.000 349.840 ;
        RECT 4.400 346.440 895.600 347.840 ;
        RECT 3.990 341.040 896.000 346.440 ;
        RECT 4.400 339.640 895.600 341.040 ;
        RECT 3.990 337.640 896.000 339.640 ;
        RECT 3.990 336.240 895.600 337.640 ;
        RECT 3.990 334.240 896.000 336.240 ;
        RECT 4.400 332.840 896.000 334.240 ;
        RECT 3.990 330.840 896.000 332.840 ;
        RECT 3.990 329.440 895.600 330.840 ;
        RECT 3.990 327.440 896.000 329.440 ;
        RECT 4.400 326.040 896.000 327.440 ;
        RECT 3.990 324.040 896.000 326.040 ;
        RECT 4.400 322.640 895.600 324.040 ;
        RECT 3.990 320.640 896.000 322.640 ;
        RECT 3.990 319.240 895.600 320.640 ;
        RECT 3.990 317.240 896.000 319.240 ;
        RECT 4.400 315.840 896.000 317.240 ;
        RECT 3.990 313.840 896.000 315.840 ;
        RECT 3.990 312.440 895.600 313.840 ;
        RECT 3.990 310.440 896.000 312.440 ;
        RECT 4.400 309.040 896.000 310.440 ;
        RECT 3.990 307.040 896.000 309.040 ;
        RECT 4.400 305.640 895.600 307.040 ;
        RECT 3.990 303.640 896.000 305.640 ;
        RECT 3.990 302.240 895.600 303.640 ;
        RECT 3.990 300.240 896.000 302.240 ;
        RECT 4.400 298.840 896.000 300.240 ;
        RECT 3.990 296.840 896.000 298.840 ;
        RECT 3.990 295.440 895.600 296.840 ;
        RECT 3.990 293.440 896.000 295.440 ;
        RECT 4.400 292.040 896.000 293.440 ;
        RECT 3.990 290.040 896.000 292.040 ;
        RECT 4.400 288.640 895.600 290.040 ;
        RECT 3.990 283.240 896.000 288.640 ;
        RECT 4.400 281.840 895.600 283.240 ;
        RECT 3.990 279.840 896.000 281.840 ;
        RECT 3.990 278.440 895.600 279.840 ;
        RECT 3.990 276.440 896.000 278.440 ;
        RECT 4.400 275.040 896.000 276.440 ;
        RECT 3.990 273.040 896.000 275.040 ;
        RECT 3.990 271.640 895.600 273.040 ;
        RECT 3.990 269.640 896.000 271.640 ;
        RECT 4.400 268.240 896.000 269.640 ;
        RECT 3.990 266.240 896.000 268.240 ;
        RECT 4.400 264.840 895.600 266.240 ;
        RECT 3.990 262.840 896.000 264.840 ;
        RECT 3.990 261.440 895.600 262.840 ;
        RECT 3.990 259.440 896.000 261.440 ;
        RECT 4.400 258.040 896.000 259.440 ;
        RECT 3.990 256.040 896.000 258.040 ;
        RECT 3.990 254.640 895.600 256.040 ;
        RECT 3.990 252.640 896.000 254.640 ;
        RECT 4.400 251.240 896.000 252.640 ;
        RECT 3.990 249.240 896.000 251.240 ;
        RECT 4.400 247.840 895.600 249.240 ;
        RECT 3.990 242.440 896.000 247.840 ;
        RECT 4.400 241.040 895.600 242.440 ;
        RECT 3.990 239.040 896.000 241.040 ;
        RECT 3.990 237.640 895.600 239.040 ;
        RECT 3.990 235.640 896.000 237.640 ;
        RECT 4.400 234.240 896.000 235.640 ;
        RECT 3.990 232.240 896.000 234.240 ;
        RECT 4.400 230.840 895.600 232.240 ;
        RECT 3.990 225.440 896.000 230.840 ;
        RECT 4.400 224.040 895.600 225.440 ;
        RECT 3.990 222.040 896.000 224.040 ;
        RECT 3.990 220.640 895.600 222.040 ;
        RECT 3.990 218.640 896.000 220.640 ;
        RECT 4.400 217.240 896.000 218.640 ;
        RECT 3.990 215.240 896.000 217.240 ;
        RECT 3.990 213.840 895.600 215.240 ;
        RECT 3.990 211.840 896.000 213.840 ;
        RECT 4.400 210.440 896.000 211.840 ;
        RECT 3.990 208.440 896.000 210.440 ;
        RECT 4.400 207.040 895.600 208.440 ;
        RECT 3.990 205.040 896.000 207.040 ;
        RECT 3.990 203.640 895.600 205.040 ;
        RECT 3.990 201.640 896.000 203.640 ;
        RECT 4.400 200.240 896.000 201.640 ;
        RECT 3.990 198.240 896.000 200.240 ;
        RECT 3.990 196.840 895.600 198.240 ;
        RECT 3.990 194.840 896.000 196.840 ;
        RECT 4.400 193.440 896.000 194.840 ;
        RECT 3.990 191.440 896.000 193.440 ;
        RECT 4.400 190.040 895.600 191.440 ;
        RECT 3.990 184.640 896.000 190.040 ;
        RECT 4.400 183.240 895.600 184.640 ;
        RECT 3.990 181.240 896.000 183.240 ;
        RECT 3.990 179.840 895.600 181.240 ;
        RECT 3.990 177.840 896.000 179.840 ;
        RECT 4.400 176.440 896.000 177.840 ;
        RECT 3.990 174.440 896.000 176.440 ;
        RECT 4.400 173.040 895.600 174.440 ;
        RECT 3.990 167.640 896.000 173.040 ;
        RECT 4.400 166.240 895.600 167.640 ;
        RECT 3.990 164.240 896.000 166.240 ;
        RECT 3.990 162.840 895.600 164.240 ;
        RECT 3.990 160.840 896.000 162.840 ;
        RECT 4.400 159.440 896.000 160.840 ;
        RECT 3.990 157.440 896.000 159.440 ;
        RECT 3.990 156.040 895.600 157.440 ;
        RECT 3.990 154.040 896.000 156.040 ;
        RECT 4.400 152.640 896.000 154.040 ;
        RECT 3.990 150.640 896.000 152.640 ;
        RECT 4.400 149.240 895.600 150.640 ;
        RECT 3.990 147.240 896.000 149.240 ;
        RECT 3.990 145.840 895.600 147.240 ;
        RECT 3.990 143.840 896.000 145.840 ;
        RECT 4.400 142.440 896.000 143.840 ;
        RECT 3.990 140.440 896.000 142.440 ;
        RECT 3.990 139.040 895.600 140.440 ;
        RECT 3.990 137.040 896.000 139.040 ;
        RECT 4.400 135.640 896.000 137.040 ;
        RECT 3.990 133.640 896.000 135.640 ;
        RECT 4.400 132.240 895.600 133.640 ;
        RECT 3.990 126.840 896.000 132.240 ;
        RECT 4.400 125.440 895.600 126.840 ;
        RECT 3.990 123.440 896.000 125.440 ;
        RECT 3.990 122.040 895.600 123.440 ;
        RECT 3.990 120.040 896.000 122.040 ;
        RECT 4.400 118.640 896.000 120.040 ;
        RECT 3.990 116.640 896.000 118.640 ;
        RECT 4.400 115.240 895.600 116.640 ;
        RECT 3.990 109.840 896.000 115.240 ;
        RECT 4.400 108.440 895.600 109.840 ;
        RECT 3.990 106.440 896.000 108.440 ;
        RECT 3.990 105.040 895.600 106.440 ;
        RECT 3.990 103.040 896.000 105.040 ;
        RECT 4.400 101.640 896.000 103.040 ;
        RECT 3.990 99.640 896.000 101.640 ;
        RECT 3.990 98.240 895.600 99.640 ;
        RECT 3.990 96.240 896.000 98.240 ;
        RECT 4.400 94.840 896.000 96.240 ;
        RECT 3.990 92.840 896.000 94.840 ;
        RECT 4.400 91.440 895.600 92.840 ;
        RECT 3.990 89.440 896.000 91.440 ;
        RECT 3.990 88.040 895.600 89.440 ;
        RECT 3.990 86.040 896.000 88.040 ;
        RECT 4.400 84.640 896.000 86.040 ;
        RECT 3.990 82.640 896.000 84.640 ;
        RECT 3.990 81.240 895.600 82.640 ;
        RECT 3.990 79.240 896.000 81.240 ;
        RECT 4.400 77.840 896.000 79.240 ;
        RECT 3.990 75.840 896.000 77.840 ;
        RECT 4.400 74.440 895.600 75.840 ;
        RECT 3.990 69.040 896.000 74.440 ;
        RECT 4.400 67.640 895.600 69.040 ;
        RECT 3.990 65.640 896.000 67.640 ;
        RECT 3.990 64.240 895.600 65.640 ;
        RECT 3.990 62.240 896.000 64.240 ;
        RECT 4.400 60.840 896.000 62.240 ;
        RECT 3.990 58.840 896.000 60.840 ;
        RECT 4.400 57.440 895.600 58.840 ;
        RECT 3.990 52.040 896.000 57.440 ;
        RECT 4.400 50.640 895.600 52.040 ;
        RECT 3.990 48.640 896.000 50.640 ;
        RECT 3.990 47.240 895.600 48.640 ;
        RECT 3.990 45.240 896.000 47.240 ;
        RECT 4.400 43.840 896.000 45.240 ;
        RECT 3.990 41.840 896.000 43.840 ;
        RECT 3.990 40.440 895.600 41.840 ;
        RECT 3.990 38.440 896.000 40.440 ;
        RECT 4.400 37.040 896.000 38.440 ;
        RECT 3.990 35.040 896.000 37.040 ;
        RECT 4.400 33.640 895.600 35.040 ;
        RECT 3.990 31.640 896.000 33.640 ;
        RECT 3.990 30.240 895.600 31.640 ;
        RECT 3.990 28.240 896.000 30.240 ;
        RECT 4.400 26.840 896.000 28.240 ;
        RECT 3.990 24.840 896.000 26.840 ;
        RECT 3.990 23.440 895.600 24.840 ;
        RECT 3.990 21.440 896.000 23.440 ;
        RECT 4.400 20.040 896.000 21.440 ;
        RECT 3.990 18.040 896.000 20.040 ;
        RECT 4.400 16.640 895.600 18.040 ;
        RECT 3.990 11.240 896.000 16.640 ;
        RECT 4.400 9.840 895.600 11.240 ;
        RECT 3.990 7.840 896.000 9.840 ;
        RECT 3.990 6.975 895.600 7.840 ;
  END
END TOP_digital
END LIBRARY

